VERSION 5.8 ;
BUSBITCHARS "[]" ;
DIVIDERCHAR "/" ;
UNITS
    DATABASE MICRONS 1000 ;
END UNITS

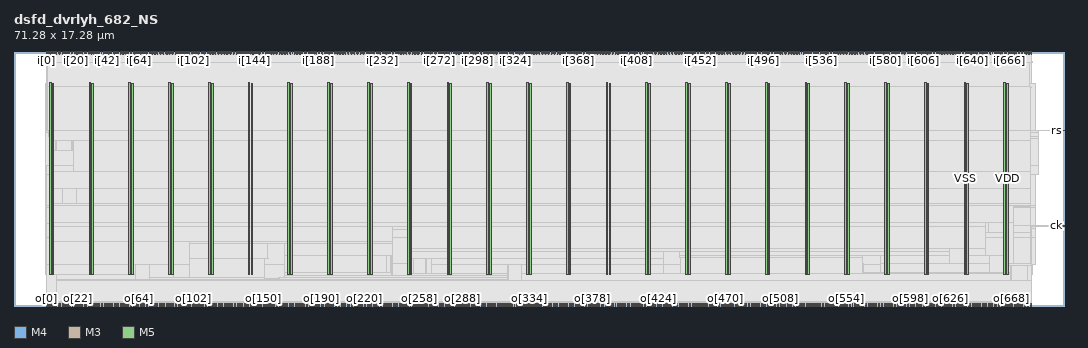
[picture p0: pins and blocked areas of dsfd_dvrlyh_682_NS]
MACRO dsfd_dvrlyh_682_NS
  FOREIGN dsfd_dvrlyh_682_NS 0 0 ;
  CLASS BLOCK ;
  SIZE 71.28 BY 17.28 ;
  PIN ck
    DIRECTION INPUT ;
    USE SIGNAL ;
    PORT
      LAYER M4 ;
        RECT  71.088 5.424 71.28 5.448 ;
    END
  END ck
  PIN ck_o
    DIRECTION OUTPUT ;
    USE SIGNAL ;
    PORT
      LAYER M3 ;
        RECT  69.048 0 69.066 0.144 ;
    END
  END ck_o
  PIN i[0]
    DIRECTION INPUT ;
    USE SIGNAL ;
    PORT
      LAYER M3 ;
        RECT  2.196 17.136 2.214 17.28 ;
    END
  END i[0]
  PIN i[100]
    DIRECTION INPUT ;
    USE SIGNAL ;
    PORT
      LAYER M3 ;
        RECT  12.024 17.136 12.042 17.28 ;
    END
  END i[100]
  PIN i[101]
    DIRECTION INPUT ;
    USE SIGNAL ;
    PORT
      LAYER M5 ;
        RECT  12.096 17.088 12.12 17.28 ;
    END
  END i[101]
  PIN i[102]
    DIRECTION INPUT ;
    USE SIGNAL ;
    PORT
      LAYER M3 ;
        RECT  12.204 17.136 12.222 17.28 ;
    END
  END i[102]
  PIN i[103]
    DIRECTION INPUT ;
    USE SIGNAL ;
    PORT
      LAYER M5 ;
        RECT  12.288 17.088 12.312 17.28 ;
    END
  END i[103]
  PIN i[104]
    DIRECTION INPUT ;
    USE SIGNAL ;
    PORT
      LAYER M3 ;
        RECT  12.42 17.136 12.438 17.28 ;
    END
  END i[104]
  PIN i[105]
    DIRECTION INPUT ;
    USE SIGNAL ;
    PORT
      LAYER M5 ;
        RECT  12.528 17.088 12.552 17.28 ;
    END
  END i[105]
  PIN i[106]
    DIRECTION INPUT ;
    USE SIGNAL ;
    PORT
      LAYER M3 ;
        RECT  12.6 17.136 12.618 17.28 ;
    END
  END i[106]
  PIN i[107]
    DIRECTION INPUT ;
    USE SIGNAL ;
    PORT
      LAYER M5 ;
        RECT  12.72 17.088 12.744 17.28 ;
    END
  END i[107]
  PIN i[108]
    DIRECTION INPUT ;
    USE SIGNAL ;
    PORT
      LAYER M3 ;
        RECT  12.816 17.136 12.834 17.28 ;
    END
  END i[108]
  PIN i[109]
    DIRECTION INPUT ;
    USE SIGNAL ;
    PORT
      LAYER M5 ;
        RECT  12.912 17.088 12.936 17.28 ;
    END
  END i[109]
  PIN i[10]
    DIRECTION INPUT ;
    USE SIGNAL ;
    PORT
      LAYER M3 ;
        RECT  3.168 17.136 3.186 17.28 ;
    END
  END i[10]
  PIN i[110]
    DIRECTION INPUT ;
    USE SIGNAL ;
    PORT
      LAYER M3 ;
        RECT  12.996 17.136 13.014 17.28 ;
    END
  END i[110]
  PIN i[111]
    DIRECTION INPUT ;
    USE SIGNAL ;
    PORT
      LAYER M5 ;
        RECT  13.104 17.088 13.128 17.28 ;
    END
  END i[111]
  PIN i[112]
    DIRECTION INPUT ;
    USE SIGNAL ;
    PORT
      LAYER M3 ;
        RECT  13.212 17.136 13.23 17.28 ;
    END
  END i[112]
  PIN i[113]
    DIRECTION INPUT ;
    USE SIGNAL ;
    PORT
      LAYER M5 ;
        RECT  13.296 17.088 13.32 17.28 ;
    END
  END i[113]
  PIN i[114]
    DIRECTION INPUT ;
    USE SIGNAL ;
    PORT
      LAYER M3 ;
        RECT  13.392 17.136 13.41 17.28 ;
    END
  END i[114]
  PIN i[115]
    DIRECTION INPUT ;
    USE SIGNAL ;
    PORT
      LAYER M5 ;
        RECT  13.488 17.088 13.512 17.28 ;
    END
  END i[115]
  PIN i[116]
    DIRECTION INPUT ;
    USE SIGNAL ;
    PORT
      LAYER M3 ;
        RECT  13.572 17.136 13.59 17.28 ;
    END
  END i[116]
  PIN i[117]
    DIRECTION INPUT ;
    USE SIGNAL ;
    PORT
      LAYER M5 ;
        RECT  13.68 17.088 13.704 17.28 ;
    END
  END i[117]
  PIN i[118]
    DIRECTION INPUT ;
    USE SIGNAL ;
    PORT
      LAYER M3 ;
        RECT  13.788 17.136 13.806 17.28 ;
    END
  END i[118]
  PIN i[119]
    DIRECTION INPUT ;
    USE SIGNAL ;
    PORT
      LAYER M5 ;
        RECT  13.872 17.088 13.896 17.28 ;
    END
  END i[119]
  PIN i[11]
    DIRECTION INPUT ;
    USE SIGNAL ;
    PORT
      LAYER M5 ;
        RECT  3.264 17.088 3.288 17.28 ;
    END
  END i[11]
  PIN i[120]
    DIRECTION INPUT ;
    USE SIGNAL ;
    PORT
      LAYER M3 ;
        RECT  13.968 17.136 13.986 17.28 ;
    END
  END i[120]
  PIN i[121]
    DIRECTION INPUT ;
    USE SIGNAL ;
    PORT
      LAYER M5 ;
        RECT  14.064 17.088 14.088 17.28 ;
    END
  END i[121]
  PIN i[122]
    DIRECTION INPUT ;
    USE SIGNAL ;
    PORT
      LAYER M3 ;
        RECT  14.184 17.136 14.202 17.28 ;
    END
  END i[122]
  PIN i[123]
    DIRECTION INPUT ;
    USE SIGNAL ;
    PORT
      LAYER M5 ;
        RECT  14.256 17.088 14.28 17.28 ;
    END
  END i[123]
  PIN i[124]
    DIRECTION INPUT ;
    USE SIGNAL ;
    PORT
      LAYER M3 ;
        RECT  14.364 17.136 14.382 17.28 ;
    END
  END i[124]
  PIN i[125]
    DIRECTION INPUT ;
    USE SIGNAL ;
    PORT
      LAYER M5 ;
        RECT  14.448 17.088 14.472 17.28 ;
    END
  END i[125]
  PIN i[126]
    DIRECTION INPUT ;
    USE SIGNAL ;
    PORT
      LAYER M3 ;
        RECT  14.58 17.136 14.598 17.28 ;
    END
  END i[126]
  PIN i[127]
    DIRECTION INPUT ;
    USE SIGNAL ;
    PORT
      LAYER M5 ;
        RECT  14.688 17.088 14.712 17.28 ;
    END
  END i[127]
  PIN i[128]
    DIRECTION INPUT ;
    USE SIGNAL ;
    PORT
      LAYER M3 ;
        RECT  14.76 17.136 14.778 17.28 ;
    END
  END i[128]
  PIN i[129]
    DIRECTION INPUT ;
    USE SIGNAL ;
    PORT
      LAYER M5 ;
        RECT  14.88 17.088 14.904 17.28 ;
    END
  END i[129]
  PIN i[12]
    DIRECTION INPUT ;
    USE SIGNAL ;
    PORT
      LAYER M3 ;
        RECT  3.384 17.136 3.402 17.28 ;
    END
  END i[12]
  PIN i[130]
    DIRECTION INPUT ;
    USE SIGNAL ;
    PORT
      LAYER M3 ;
        RECT  14.976 17.136 14.994 17.28 ;
    END
  END i[130]
  PIN i[131]
    DIRECTION INPUT ;
    USE SIGNAL ;
    PORT
      LAYER M5 ;
        RECT  15.072 17.088 15.096 17.28 ;
    END
  END i[131]
  PIN i[132]
    DIRECTION INPUT ;
    USE SIGNAL ;
    PORT
      LAYER M3 ;
        RECT  15.156 17.136 15.174 17.28 ;
    END
  END i[132]
  PIN i[133]
    DIRECTION INPUT ;
    USE SIGNAL ;
    PORT
      LAYER M5 ;
        RECT  15.264 17.088 15.288 17.28 ;
    END
  END i[133]
  PIN i[134]
    DIRECTION INPUT ;
    USE SIGNAL ;
    PORT
      LAYER M3 ;
        RECT  15.372 17.136 15.39 17.28 ;
    END
  END i[134]
  PIN i[135]
    DIRECTION INPUT ;
    USE SIGNAL ;
    PORT
      LAYER M5 ;
        RECT  15.456 17.088 15.48 17.28 ;
    END
  END i[135]
  PIN i[136]
    DIRECTION INPUT ;
    USE SIGNAL ;
    PORT
      LAYER M3 ;
        RECT  15.552 17.136 15.57 17.28 ;
    END
  END i[136]
  PIN i[137]
    DIRECTION INPUT ;
    USE SIGNAL ;
    PORT
      LAYER M5 ;
        RECT  15.648 17.088 15.672 17.28 ;
    END
  END i[137]
  PIN i[138]
    DIRECTION INPUT ;
    USE SIGNAL ;
    PORT
      LAYER M3 ;
        RECT  15.732 17.136 15.75 17.28 ;
    END
  END i[138]
  PIN i[139]
    DIRECTION INPUT ;
    USE SIGNAL ;
    PORT
      LAYER M5 ;
        RECT  15.84 17.088 15.864 17.28 ;
    END
  END i[139]
  PIN i[13]
    DIRECTION INPUT ;
    USE SIGNAL ;
    PORT
      LAYER M5 ;
        RECT  3.456 17.088 3.48 17.28 ;
    END
  END i[13]
  PIN i[140]
    DIRECTION INPUT ;
    USE SIGNAL ;
    PORT
      LAYER M3 ;
        RECT  15.948 17.136 15.966 17.28 ;
    END
  END i[140]
  PIN i[141]
    DIRECTION INPUT ;
    USE SIGNAL ;
    PORT
      LAYER M5 ;
        RECT  16.032 17.088 16.056 17.28 ;
    END
  END i[141]
  PIN i[142]
    DIRECTION INPUT ;
    USE SIGNAL ;
    PORT
      LAYER M3 ;
        RECT  16.128 17.136 16.146 17.28 ;
    END
  END i[142]
  PIN i[143]
    DIRECTION INPUT ;
    USE SIGNAL ;
    PORT
      LAYER M5 ;
        RECT  16.224 17.088 16.248 17.28 ;
    END
  END i[143]
  PIN i[144]
    DIRECTION INPUT ;
    USE SIGNAL ;
    PORT
      LAYER M3 ;
        RECT  16.344 17.136 16.362 17.28 ;
    END
  END i[144]
  PIN i[145]
    DIRECTION INPUT ;
    USE SIGNAL ;
    PORT
      LAYER M5 ;
        RECT  16.416 17.088 16.44 17.28 ;
    END
  END i[145]
  PIN i[146]
    DIRECTION INPUT ;
    USE SIGNAL ;
    PORT
      LAYER M3 ;
        RECT  16.524 17.136 16.542 17.28 ;
    END
  END i[146]
  PIN i[147]
    DIRECTION INPUT ;
    USE SIGNAL ;
    PORT
      LAYER M5 ;
        RECT  16.608 17.088 16.632 17.28 ;
    END
  END i[147]
  PIN i[148]
    DIRECTION INPUT ;
    USE SIGNAL ;
    PORT
      LAYER M3 ;
        RECT  16.74 17.136 16.758 17.28 ;
    END
  END i[148]
  PIN i[149]
    DIRECTION INPUT ;
    USE SIGNAL ;
    PORT
      LAYER M5 ;
        RECT  16.848 17.088 16.872 17.28 ;
    END
  END i[149]
  PIN i[14]
    DIRECTION INPUT ;
    USE SIGNAL ;
    PORT
      LAYER M3 ;
        RECT  3.564 17.136 3.582 17.28 ;
    END
  END i[14]
  PIN i[150]
    DIRECTION INPUT ;
    USE SIGNAL ;
    PORT
      LAYER M3 ;
        RECT  16.92 17.136 16.938 17.28 ;
    END
  END i[150]
  PIN i[151]
    DIRECTION INPUT ;
    USE SIGNAL ;
    PORT
      LAYER M5 ;
        RECT  17.04 17.088 17.064 17.28 ;
    END
  END i[151]
  PIN i[152]
    DIRECTION INPUT ;
    USE SIGNAL ;
    PORT
      LAYER M3 ;
        RECT  17.136 17.136 17.154 17.28 ;
    END
  END i[152]
  PIN i[153]
    DIRECTION INPUT ;
    USE SIGNAL ;
    PORT
      LAYER M5 ;
        RECT  17.232 17.088 17.256 17.28 ;
    END
  END i[153]
  PIN i[154]
    DIRECTION INPUT ;
    USE SIGNAL ;
    PORT
      LAYER M3 ;
        RECT  17.316 17.136 17.334 17.28 ;
    END
  END i[154]
  PIN i[155]
    DIRECTION INPUT ;
    USE SIGNAL ;
    PORT
      LAYER M5 ;
        RECT  17.424 17.088 17.448 17.28 ;
    END
  END i[155]
  PIN i[156]
    DIRECTION INPUT ;
    USE SIGNAL ;
    PORT
      LAYER M3 ;
        RECT  17.532 17.136 17.55 17.28 ;
    END
  END i[156]
  PIN i[157]
    DIRECTION INPUT ;
    USE SIGNAL ;
    PORT
      LAYER M5 ;
        RECT  17.616 17.088 17.64 17.28 ;
    END
  END i[157]
  PIN i[158]
    DIRECTION INPUT ;
    USE SIGNAL ;
    PORT
      LAYER M3 ;
        RECT  17.712 17.136 17.73 17.28 ;
    END
  END i[158]
  PIN i[159]
    DIRECTION INPUT ;
    USE SIGNAL ;
    PORT
      LAYER M5 ;
        RECT  17.808 17.088 17.832 17.28 ;
    END
  END i[159]
  PIN i[15]
    DIRECTION INPUT ;
    USE SIGNAL ;
    PORT
      LAYER M5 ;
        RECT  3.648 17.088 3.672 17.28 ;
    END
  END i[15]
  PIN i[160]
    DIRECTION INPUT ;
    USE SIGNAL ;
    PORT
      LAYER M3 ;
        RECT  17.892 17.136 17.91 17.28 ;
    END
  END i[160]
  PIN i[161]
    DIRECTION INPUT ;
    USE SIGNAL ;
    PORT
      LAYER M5 ;
        RECT  18 17.088 18.024 17.28 ;
    END
  END i[161]
  PIN i[162]
    DIRECTION INPUT ;
    USE SIGNAL ;
    PORT
      LAYER M3 ;
        RECT  18.108 17.136 18.126 17.28 ;
    END
  END i[162]
  PIN i[163]
    DIRECTION INPUT ;
    USE SIGNAL ;
    PORT
      LAYER M5 ;
        RECT  18.192 17.088 18.216 17.28 ;
    END
  END i[163]
  PIN i[164]
    DIRECTION INPUT ;
    USE SIGNAL ;
    PORT
      LAYER M3 ;
        RECT  18.288 17.136 18.306 17.28 ;
    END
  END i[164]
  PIN i[165]
    DIRECTION INPUT ;
    USE SIGNAL ;
    PORT
      LAYER M5 ;
        RECT  18.384 17.088 18.408 17.28 ;
    END
  END i[165]
  PIN i[166]
    DIRECTION INPUT ;
    USE SIGNAL ;
    PORT
      LAYER M3 ;
        RECT  18.504 17.136 18.522 17.28 ;
    END
  END i[166]
  PIN i[167]
    DIRECTION INPUT ;
    USE SIGNAL ;
    PORT
      LAYER M5 ;
        RECT  18.576 17.088 18.6 17.28 ;
    END
  END i[167]
  PIN i[168]
    DIRECTION INPUT ;
    USE SIGNAL ;
    PORT
      LAYER M3 ;
        RECT  18.684 17.136 18.702 17.28 ;
    END
  END i[168]
  PIN i[169]
    DIRECTION INPUT ;
    USE SIGNAL ;
    PORT
      LAYER M5 ;
        RECT  18.768 17.088 18.792 17.28 ;
    END
  END i[169]
  PIN i[16]
    DIRECTION INPUT ;
    USE SIGNAL ;
    PORT
      LAYER M3 ;
        RECT  3.78 17.136 3.798 17.28 ;
    END
  END i[16]
  PIN i[170]
    DIRECTION INPUT ;
    USE SIGNAL ;
    PORT
      LAYER M3 ;
        RECT  18.9 17.136 18.918 17.28 ;
    END
  END i[170]
  PIN i[171]
    DIRECTION INPUT ;
    USE SIGNAL ;
    PORT
      LAYER M5 ;
        RECT  19.008 17.088 19.032 17.28 ;
    END
  END i[171]
  PIN i[172]
    DIRECTION INPUT ;
    USE SIGNAL ;
    PORT
      LAYER M3 ;
        RECT  19.08 17.136 19.098 17.28 ;
    END
  END i[172]
  PIN i[173]
    DIRECTION INPUT ;
    USE SIGNAL ;
    PORT
      LAYER M5 ;
        RECT  19.2 17.088 19.224 17.28 ;
    END
  END i[173]
  PIN i[174]
    DIRECTION INPUT ;
    USE SIGNAL ;
    PORT
      LAYER M3 ;
        RECT  19.296 17.136 19.314 17.28 ;
    END
  END i[174]
  PIN i[175]
    DIRECTION INPUT ;
    USE SIGNAL ;
    PORT
      LAYER M5 ;
        RECT  19.392 17.088 19.416 17.28 ;
    END
  END i[175]
  PIN i[176]
    DIRECTION INPUT ;
    USE SIGNAL ;
    PORT
      LAYER M3 ;
        RECT  19.476 17.136 19.494 17.28 ;
    END
  END i[176]
  PIN i[177]
    DIRECTION INPUT ;
    USE SIGNAL ;
    PORT
      LAYER M5 ;
        RECT  19.584 17.088 19.608 17.28 ;
    END
  END i[177]
  PIN i[178]
    DIRECTION INPUT ;
    USE SIGNAL ;
    PORT
      LAYER M3 ;
        RECT  19.692 17.136 19.71 17.28 ;
    END
  END i[178]
  PIN i[179]
    DIRECTION INPUT ;
    USE SIGNAL ;
    PORT
      LAYER M5 ;
        RECT  19.776 17.088 19.8 17.28 ;
    END
  END i[179]
  PIN i[17]
    DIRECTION INPUT ;
    USE SIGNAL ;
    PORT
      LAYER M5 ;
        RECT  3.888 17.088 3.912 17.28 ;
    END
  END i[17]
  PIN i[180]
    DIRECTION INPUT ;
    USE SIGNAL ;
    PORT
      LAYER M3 ;
        RECT  19.872 17.136 19.89 17.28 ;
    END
  END i[180]
  PIN i[181]
    DIRECTION INPUT ;
    USE SIGNAL ;
    PORT
      LAYER M5 ;
        RECT  19.968 17.088 19.992 17.28 ;
    END
  END i[181]
  PIN i[182]
    DIRECTION INPUT ;
    USE SIGNAL ;
    PORT
      LAYER M3 ;
        RECT  20.052 17.136 20.07 17.28 ;
    END
  END i[182]
  PIN i[183]
    DIRECTION INPUT ;
    USE SIGNAL ;
    PORT
      LAYER M5 ;
        RECT  20.16 17.088 20.184 17.28 ;
    END
  END i[183]
  PIN i[184]
    DIRECTION INPUT ;
    USE SIGNAL ;
    PORT
      LAYER M3 ;
        RECT  20.268 17.136 20.286 17.28 ;
    END
  END i[184]
  PIN i[185]
    DIRECTION INPUT ;
    USE SIGNAL ;
    PORT
      LAYER M5 ;
        RECT  20.352 17.088 20.376 17.28 ;
    END
  END i[185]
  PIN i[186]
    DIRECTION INPUT ;
    USE SIGNAL ;
    PORT
      LAYER M3 ;
        RECT  20.448 17.136 20.466 17.28 ;
    END
  END i[186]
  PIN i[187]
    DIRECTION INPUT ;
    USE SIGNAL ;
    PORT
      LAYER M5 ;
        RECT  20.544 17.088 20.568 17.28 ;
    END
  END i[187]
  PIN i[188]
    DIRECTION INPUT ;
    USE SIGNAL ;
    PORT
      LAYER M3 ;
        RECT  20.664 17.136 20.682 17.28 ;
    END
  END i[188]
  PIN i[189]
    DIRECTION INPUT ;
    USE SIGNAL ;
    PORT
      LAYER M5 ;
        RECT  20.736 17.088 20.76 17.28 ;
    END
  END i[189]
  PIN i[18]
    DIRECTION INPUT ;
    USE SIGNAL ;
    PORT
      LAYER M3 ;
        RECT  3.96 17.136 3.978 17.28 ;
    END
  END i[18]
  PIN i[190]
    DIRECTION INPUT ;
    USE SIGNAL ;
    PORT
      LAYER M3 ;
        RECT  20.844 17.136 20.862 17.28 ;
    END
  END i[190]
  PIN i[191]
    DIRECTION INPUT ;
    USE SIGNAL ;
    PORT
      LAYER M5 ;
        RECT  20.928 17.088 20.952 17.28 ;
    END
  END i[191]
  PIN i[192]
    DIRECTION INPUT ;
    USE SIGNAL ;
    PORT
      LAYER M3 ;
        RECT  21.06 17.136 21.078 17.28 ;
    END
  END i[192]
  PIN i[193]
    DIRECTION INPUT ;
    USE SIGNAL ;
    PORT
      LAYER M5 ;
        RECT  21.168 17.088 21.192 17.28 ;
    END
  END i[193]
  PIN i[194]
    DIRECTION INPUT ;
    USE SIGNAL ;
    PORT
      LAYER M3 ;
        RECT  21.24 17.136 21.258 17.28 ;
    END
  END i[194]
  PIN i[195]
    DIRECTION INPUT ;
    USE SIGNAL ;
    PORT
      LAYER M5 ;
        RECT  21.36 17.088 21.384 17.28 ;
    END
  END i[195]
  PIN i[196]
    DIRECTION INPUT ;
    USE SIGNAL ;
    PORT
      LAYER M3 ;
        RECT  21.456 17.136 21.474 17.28 ;
    END
  END i[196]
  PIN i[197]
    DIRECTION INPUT ;
    USE SIGNAL ;
    PORT
      LAYER M5 ;
        RECT  21.552 17.088 21.576 17.28 ;
    END
  END i[197]
  PIN i[198]
    DIRECTION INPUT ;
    USE SIGNAL ;
    PORT
      LAYER M3 ;
        RECT  21.636 17.136 21.654 17.28 ;
    END
  END i[198]
  PIN i[199]
    DIRECTION INPUT ;
    USE SIGNAL ;
    PORT
      LAYER M5 ;
        RECT  21.744 17.088 21.768 17.28 ;
    END
  END i[199]
  PIN i[19]
    DIRECTION INPUT ;
    USE SIGNAL ;
    PORT
      LAYER M5 ;
        RECT  4.08 17.088 4.104 17.28 ;
    END
  END i[19]
  PIN i[1]
    DIRECTION INPUT ;
    USE SIGNAL ;
    PORT
      LAYER M5 ;
        RECT  2.304 17.088 2.328 17.28 ;
    END
  END i[1]
  PIN i[200]
    DIRECTION INPUT ;
    USE SIGNAL ;
    PORT
      LAYER M3 ;
        RECT  21.852 17.136 21.87 17.28 ;
    END
  END i[200]
  PIN i[201]
    DIRECTION INPUT ;
    USE SIGNAL ;
    PORT
      LAYER M5 ;
        RECT  21.936 17.088 21.96 17.28 ;
    END
  END i[201]
  PIN i[202]
    DIRECTION INPUT ;
    USE SIGNAL ;
    PORT
      LAYER M3 ;
        RECT  22.032 17.136 22.05 17.28 ;
    END
  END i[202]
  PIN i[203]
    DIRECTION INPUT ;
    USE SIGNAL ;
    PORT
      LAYER M5 ;
        RECT  22.128 17.088 22.152 17.28 ;
    END
  END i[203]
  PIN i[204]
    DIRECTION INPUT ;
    USE SIGNAL ;
    PORT
      LAYER M3 ;
        RECT  22.212 17.136 22.23 17.28 ;
    END
  END i[204]
  PIN i[205]
    DIRECTION INPUT ;
    USE SIGNAL ;
    PORT
      LAYER M5 ;
        RECT  22.32 17.088 22.344 17.28 ;
    END
  END i[205]
  PIN i[206]
    DIRECTION INPUT ;
    USE SIGNAL ;
    PORT
      LAYER M3 ;
        RECT  22.428 17.136 22.446 17.28 ;
    END
  END i[206]
  PIN i[207]
    DIRECTION INPUT ;
    USE SIGNAL ;
    PORT
      LAYER M5 ;
        RECT  22.512 17.088 22.536 17.28 ;
    END
  END i[207]
  PIN i[208]
    DIRECTION INPUT ;
    USE SIGNAL ;
    PORT
      LAYER M3 ;
        RECT  22.608 17.136 22.626 17.28 ;
    END
  END i[208]
  PIN i[209]
    DIRECTION INPUT ;
    USE SIGNAL ;
    PORT
      LAYER M5 ;
        RECT  22.704 17.088 22.728 17.28 ;
    END
  END i[209]
  PIN i[20]
    DIRECTION INPUT ;
    USE SIGNAL ;
    PORT
      LAYER M3 ;
        RECT  4.176 17.136 4.194 17.28 ;
    END
  END i[20]
  PIN i[210]
    DIRECTION INPUT ;
    USE SIGNAL ;
    PORT
      LAYER M3 ;
        RECT  22.824 17.136 22.842 17.28 ;
    END
  END i[210]
  PIN i[211]
    DIRECTION INPUT ;
    USE SIGNAL ;
    PORT
      LAYER M5 ;
        RECT  22.896 17.088 22.92 17.28 ;
    END
  END i[211]
  PIN i[212]
    DIRECTION INPUT ;
    USE SIGNAL ;
    PORT
      LAYER M3 ;
        RECT  23.004 17.136 23.022 17.28 ;
    END
  END i[212]
  PIN i[213]
    DIRECTION INPUT ;
    USE SIGNAL ;
    PORT
      LAYER M5 ;
        RECT  23.088 17.088 23.112 17.28 ;
    END
  END i[213]
  PIN i[214]
    DIRECTION INPUT ;
    USE SIGNAL ;
    PORT
      LAYER M3 ;
        RECT  23.22 17.136 23.238 17.28 ;
    END
  END i[214]
  PIN i[215]
    DIRECTION INPUT ;
    USE SIGNAL ;
    PORT
      LAYER M5 ;
        RECT  23.328 17.088 23.352 17.28 ;
    END
  END i[215]
  PIN i[216]
    DIRECTION INPUT ;
    USE SIGNAL ;
    PORT
      LAYER M3 ;
        RECT  23.4 17.136 23.418 17.28 ;
    END
  END i[216]
  PIN i[217]
    DIRECTION INPUT ;
    USE SIGNAL ;
    PORT
      LAYER M5 ;
        RECT  23.52 17.088 23.544 17.28 ;
    END
  END i[217]
  PIN i[218]
    DIRECTION INPUT ;
    USE SIGNAL ;
    PORT
      LAYER M3 ;
        RECT  23.616 17.136 23.634 17.28 ;
    END
  END i[218]
  PIN i[219]
    DIRECTION INPUT ;
    USE SIGNAL ;
    PORT
      LAYER M5 ;
        RECT  23.712 17.088 23.736 17.28 ;
    END
  END i[219]
  PIN i[21]
    DIRECTION INPUT ;
    USE SIGNAL ;
    PORT
      LAYER M5 ;
        RECT  4.272 17.088 4.296 17.28 ;
    END
  END i[21]
  PIN i[220]
    DIRECTION INPUT ;
    USE SIGNAL ;
    PORT
      LAYER M3 ;
        RECT  23.796 17.136 23.814 17.28 ;
    END
  END i[220]
  PIN i[221]
    DIRECTION INPUT ;
    USE SIGNAL ;
    PORT
      LAYER M5 ;
        RECT  23.904 17.088 23.928 17.28 ;
    END
  END i[221]
  PIN i[222]
    DIRECTION INPUT ;
    USE SIGNAL ;
    PORT
      LAYER M3 ;
        RECT  24.012 17.136 24.03 17.28 ;
    END
  END i[222]
  PIN i[223]
    DIRECTION INPUT ;
    USE SIGNAL ;
    PORT
      LAYER M5 ;
        RECT  24.096 17.088 24.12 17.28 ;
    END
  END i[223]
  PIN i[224]
    DIRECTION INPUT ;
    USE SIGNAL ;
    PORT
      LAYER M3 ;
        RECT  24.192 17.136 24.21 17.28 ;
    END
  END i[224]
  PIN i[225]
    DIRECTION INPUT ;
    USE SIGNAL ;
    PORT
      LAYER M5 ;
        RECT  24.288 17.088 24.312 17.28 ;
    END
  END i[225]
  PIN i[226]
    DIRECTION INPUT ;
    USE SIGNAL ;
    PORT
      LAYER M3 ;
        RECT  24.372 17.136 24.39 17.28 ;
    END
  END i[226]
  PIN i[227]
    DIRECTION INPUT ;
    USE SIGNAL ;
    PORT
      LAYER M5 ;
        RECT  24.48 17.088 24.504 17.28 ;
    END
  END i[227]
  PIN i[228]
    DIRECTION INPUT ;
    USE SIGNAL ;
    PORT
      LAYER M3 ;
        RECT  24.588 17.136 24.606 17.28 ;
    END
  END i[228]
  PIN i[229]
    DIRECTION INPUT ;
    USE SIGNAL ;
    PORT
      LAYER M5 ;
        RECT  24.672 17.088 24.696 17.28 ;
    END
  END i[229]
  PIN i[22]
    DIRECTION INPUT ;
    USE SIGNAL ;
    PORT
      LAYER M3 ;
        RECT  4.356 17.136 4.374 17.28 ;
    END
  END i[22]
  PIN i[230]
    DIRECTION INPUT ;
    USE SIGNAL ;
    PORT
      LAYER M3 ;
        RECT  24.768 17.136 24.786 17.28 ;
    END
  END i[230]
  PIN i[231]
    DIRECTION INPUT ;
    USE SIGNAL ;
    PORT
      LAYER M5 ;
        RECT  24.864 17.088 24.888 17.28 ;
    END
  END i[231]
  PIN i[232]
    DIRECTION INPUT ;
    USE SIGNAL ;
    PORT
      LAYER M3 ;
        RECT  24.984 17.136 25.002 17.28 ;
    END
  END i[232]
  PIN i[233]
    DIRECTION INPUT ;
    USE SIGNAL ;
    PORT
      LAYER M5 ;
        RECT  25.056 17.088 25.08 17.28 ;
    END
  END i[233]
  PIN i[234]
    DIRECTION INPUT ;
    USE SIGNAL ;
    PORT
      LAYER M3 ;
        RECT  25.164 17.136 25.182 17.28 ;
    END
  END i[234]
  PIN i[235]
    DIRECTION INPUT ;
    USE SIGNAL ;
    PORT
      LAYER M5 ;
        RECT  25.248 17.088 25.272 17.28 ;
    END
  END i[235]
  PIN i[236]
    DIRECTION INPUT ;
    USE SIGNAL ;
    PORT
      LAYER M3 ;
        RECT  25.38 17.136 25.398 17.28 ;
    END
  END i[236]
  PIN i[237]
    DIRECTION INPUT ;
    USE SIGNAL ;
    PORT
      LAYER M5 ;
        RECT  25.488 17.088 25.512 17.28 ;
    END
  END i[237]
  PIN i[238]
    DIRECTION INPUT ;
    USE SIGNAL ;
    PORT
      LAYER M3 ;
        RECT  25.56 17.136 25.578 17.28 ;
    END
  END i[238]
  PIN i[239]
    DIRECTION INPUT ;
    USE SIGNAL ;
    PORT
      LAYER M5 ;
        RECT  25.68 17.088 25.704 17.28 ;
    END
  END i[239]
  PIN i[23]
    DIRECTION INPUT ;
    USE SIGNAL ;
    PORT
      LAYER M5 ;
        RECT  4.464 17.088 4.488 17.28 ;
    END
  END i[23]
  PIN i[240]
    DIRECTION INPUT ;
    USE SIGNAL ;
    PORT
      LAYER M3 ;
        RECT  25.776 17.136 25.794 17.28 ;
    END
  END i[240]
  PIN i[241]
    DIRECTION INPUT ;
    USE SIGNAL ;
    PORT
      LAYER M5 ;
        RECT  25.872 17.088 25.896 17.28 ;
    END
  END i[241]
  PIN i[242]
    DIRECTION INPUT ;
    USE SIGNAL ;
    PORT
      LAYER M3 ;
        RECT  25.956 17.136 25.974 17.28 ;
    END
  END i[242]
  PIN i[243]
    DIRECTION INPUT ;
    USE SIGNAL ;
    PORT
      LAYER M5 ;
        RECT  26.064 17.088 26.088 17.28 ;
    END
  END i[243]
  PIN i[244]
    DIRECTION INPUT ;
    USE SIGNAL ;
    PORT
      LAYER M3 ;
        RECT  26.172 17.136 26.19 17.28 ;
    END
  END i[244]
  PIN i[245]
    DIRECTION INPUT ;
    USE SIGNAL ;
    PORT
      LAYER M5 ;
        RECT  26.256 17.088 26.28 17.28 ;
    END
  END i[245]
  PIN i[246]
    DIRECTION INPUT ;
    USE SIGNAL ;
    PORT
      LAYER M3 ;
        RECT  26.352 17.136 26.37 17.28 ;
    END
  END i[246]
  PIN i[247]
    DIRECTION INPUT ;
    USE SIGNAL ;
    PORT
      LAYER M5 ;
        RECT  26.448 17.088 26.472 17.28 ;
    END
  END i[247]
  PIN i[248]
    DIRECTION INPUT ;
    USE SIGNAL ;
    PORT
      LAYER M3 ;
        RECT  26.532 17.136 26.55 17.28 ;
    END
  END i[248]
  PIN i[249]
    DIRECTION INPUT ;
    USE SIGNAL ;
    PORT
      LAYER M5 ;
        RECT  26.64 17.088 26.664 17.28 ;
    END
  END i[249]
  PIN i[24]
    DIRECTION INPUT ;
    USE SIGNAL ;
    PORT
      LAYER M3 ;
        RECT  4.572 17.136 4.59 17.28 ;
    END
  END i[24]
  PIN i[250]
    DIRECTION INPUT ;
    USE SIGNAL ;
    PORT
      LAYER M3 ;
        RECT  26.748 17.136 26.766 17.28 ;
    END
  END i[250]
  PIN i[251]
    DIRECTION INPUT ;
    USE SIGNAL ;
    PORT
      LAYER M5 ;
        RECT  26.832 17.088 26.856 17.28 ;
    END
  END i[251]
  PIN i[252]
    DIRECTION INPUT ;
    USE SIGNAL ;
    PORT
      LAYER M3 ;
        RECT  26.928 17.136 26.946 17.28 ;
    END
  END i[252]
  PIN i[253]
    DIRECTION INPUT ;
    USE SIGNAL ;
    PORT
      LAYER M5 ;
        RECT  27.024 17.088 27.048 17.28 ;
    END
  END i[253]
  PIN i[254]
    DIRECTION INPUT ;
    USE SIGNAL ;
    PORT
      LAYER M3 ;
        RECT  27.144 17.136 27.162 17.28 ;
    END
  END i[254]
  PIN i[255]
    DIRECTION INPUT ;
    USE SIGNAL ;
    PORT
      LAYER M5 ;
        RECT  27.216 17.088 27.24 17.28 ;
    END
  END i[255]
  PIN i[256]
    DIRECTION INPUT ;
    USE SIGNAL ;
    PORT
      LAYER M3 ;
        RECT  27.324 17.136 27.342 17.28 ;
    END
  END i[256]
  PIN i[257]
    DIRECTION INPUT ;
    USE SIGNAL ;
    PORT
      LAYER M5 ;
        RECT  27.408 17.088 27.432 17.28 ;
    END
  END i[257]
  PIN i[258]
    DIRECTION INPUT ;
    USE SIGNAL ;
    PORT
      LAYER M3 ;
        RECT  27.54 17.136 27.558 17.28 ;
    END
  END i[258]
  PIN i[259]
    DIRECTION INPUT ;
    USE SIGNAL ;
    PORT
      LAYER M5 ;
        RECT  27.648 17.088 27.672 17.28 ;
    END
  END i[259]
  PIN i[25]
    DIRECTION INPUT ;
    USE SIGNAL ;
    PORT
      LAYER M5 ;
        RECT  4.656 17.088 4.68 17.28 ;
    END
  END i[25]
  PIN i[260]
    DIRECTION INPUT ;
    USE SIGNAL ;
    PORT
      LAYER M3 ;
        RECT  27.72 17.136 27.738 17.28 ;
    END
  END i[260]
  PIN i[261]
    DIRECTION INPUT ;
    USE SIGNAL ;
    PORT
      LAYER M5 ;
        RECT  27.84 17.088 27.864 17.28 ;
    END
  END i[261]
  PIN i[262]
    DIRECTION INPUT ;
    USE SIGNAL ;
    PORT
      LAYER M3 ;
        RECT  27.936 17.136 27.954 17.28 ;
    END
  END i[262]
  PIN i[263]
    DIRECTION INPUT ;
    USE SIGNAL ;
    PORT
      LAYER M5 ;
        RECT  28.032 17.088 28.056 17.28 ;
    END
  END i[263]
  PIN i[264]
    DIRECTION INPUT ;
    USE SIGNAL ;
    PORT
      LAYER M3 ;
        RECT  28.116 17.136 28.134 17.28 ;
    END
  END i[264]
  PIN i[265]
    DIRECTION INPUT ;
    USE SIGNAL ;
    PORT
      LAYER M5 ;
        RECT  28.224 17.088 28.248 17.28 ;
    END
  END i[265]
  PIN i[266]
    DIRECTION INPUT ;
    USE SIGNAL ;
    PORT
      LAYER M3 ;
        RECT  28.332 17.136 28.35 17.28 ;
    END
  END i[266]
  PIN i[267]
    DIRECTION INPUT ;
    USE SIGNAL ;
    PORT
      LAYER M5 ;
        RECT  28.416 17.088 28.44 17.28 ;
    END
  END i[267]
  PIN i[268]
    DIRECTION INPUT ;
    USE SIGNAL ;
    PORT
      LAYER M3 ;
        RECT  28.512 17.136 28.53 17.28 ;
    END
  END i[268]
  PIN i[269]
    DIRECTION INPUT ;
    USE SIGNAL ;
    PORT
      LAYER M5 ;
        RECT  28.608 17.088 28.632 17.28 ;
    END
  END i[269]
  PIN i[26]
    DIRECTION INPUT ;
    USE SIGNAL ;
    PORT
      LAYER M3 ;
        RECT  4.752 17.136 4.77 17.28 ;
    END
  END i[26]
  PIN i[270]
    DIRECTION INPUT ;
    USE SIGNAL ;
    PORT
      LAYER M3 ;
        RECT  28.692 17.136 28.71 17.28 ;
    END
  END i[270]
  PIN i[271]
    DIRECTION INPUT ;
    USE SIGNAL ;
    PORT
      LAYER M5 ;
        RECT  28.8 17.088 28.824 17.28 ;
    END
  END i[271]
  PIN i[272]
    DIRECTION INPUT ;
    USE SIGNAL ;
    PORT
      LAYER M3 ;
        RECT  28.908 17.136 28.926 17.28 ;
    END
  END i[272]
  PIN i[273]
    DIRECTION INPUT ;
    USE SIGNAL ;
    PORT
      LAYER M5 ;
        RECT  28.992 17.088 29.016 17.28 ;
    END
  END i[273]
  PIN i[274]
    DIRECTION INPUT ;
    USE SIGNAL ;
    PORT
      LAYER M3 ;
        RECT  29.088 17.136 29.106 17.28 ;
    END
  END i[274]
  PIN i[275]
    DIRECTION INPUT ;
    USE SIGNAL ;
    PORT
      LAYER M5 ;
        RECT  29.184 17.088 29.208 17.28 ;
    END
  END i[275]
  PIN i[276]
    DIRECTION INPUT ;
    USE SIGNAL ;
    PORT
      LAYER M3 ;
        RECT  29.304 17.136 29.322 17.28 ;
    END
  END i[276]
  PIN i[277]
    DIRECTION INPUT ;
    USE SIGNAL ;
    PORT
      LAYER M5 ;
        RECT  29.376 17.088 29.4 17.28 ;
    END
  END i[277]
  PIN i[278]
    DIRECTION INPUT ;
    USE SIGNAL ;
    PORT
      LAYER M3 ;
        RECT  29.484 17.136 29.502 17.28 ;
    END
  END i[278]
  PIN i[279]
    DIRECTION INPUT ;
    USE SIGNAL ;
    PORT
      LAYER M5 ;
        RECT  29.568 17.088 29.592 17.28 ;
    END
  END i[279]
  PIN i[27]
    DIRECTION INPUT ;
    USE SIGNAL ;
    PORT
      LAYER M5 ;
        RECT  4.848 17.088 4.872 17.28 ;
    END
  END i[27]
  PIN i[280]
    DIRECTION INPUT ;
    USE SIGNAL ;
    PORT
      LAYER M3 ;
        RECT  29.7 17.136 29.718 17.28 ;
    END
  END i[280]
  PIN i[281]
    DIRECTION INPUT ;
    USE SIGNAL ;
    PORT
      LAYER M5 ;
        RECT  29.808 17.088 29.832 17.28 ;
    END
  END i[281]
  PIN i[282]
    DIRECTION INPUT ;
    USE SIGNAL ;
    PORT
      LAYER M3 ;
        RECT  29.88 17.136 29.898 17.28 ;
    END
  END i[282]
  PIN i[283]
    DIRECTION INPUT ;
    USE SIGNAL ;
    PORT
      LAYER M5 ;
        RECT  30 17.088 30.024 17.28 ;
    END
  END i[283]
  PIN i[284]
    DIRECTION INPUT ;
    USE SIGNAL ;
    PORT
      LAYER M3 ;
        RECT  30.096 17.136 30.114 17.28 ;
    END
  END i[284]
  PIN i[285]
    DIRECTION INPUT ;
    USE SIGNAL ;
    PORT
      LAYER M5 ;
        RECT  30.192 17.088 30.216 17.28 ;
    END
  END i[285]
  PIN i[286]
    DIRECTION INPUT ;
    USE SIGNAL ;
    PORT
      LAYER M3 ;
        RECT  30.276 17.136 30.294 17.28 ;
    END
  END i[286]
  PIN i[287]
    DIRECTION INPUT ;
    USE SIGNAL ;
    PORT
      LAYER M5 ;
        RECT  30.384 17.088 30.408 17.28 ;
    END
  END i[287]
  PIN i[288]
    DIRECTION INPUT ;
    USE SIGNAL ;
    PORT
      LAYER M3 ;
        RECT  30.492 17.136 30.51 17.28 ;
    END
  END i[288]
  PIN i[289]
    DIRECTION INPUT ;
    USE SIGNAL ;
    PORT
      LAYER M5 ;
        RECT  30.576 17.088 30.6 17.28 ;
    END
  END i[289]
  PIN i[28]
    DIRECTION INPUT ;
    USE SIGNAL ;
    PORT
      LAYER M3 ;
        RECT  4.932 17.136 4.95 17.28 ;
    END
  END i[28]
  PIN i[290]
    DIRECTION INPUT ;
    USE SIGNAL ;
    PORT
      LAYER M3 ;
        RECT  30.672 17.136 30.69 17.28 ;
    END
  END i[290]
  PIN i[291]
    DIRECTION INPUT ;
    USE SIGNAL ;
    PORT
      LAYER M5 ;
        RECT  30.768 17.088 30.792 17.28 ;
    END
  END i[291]
  PIN i[292]
    DIRECTION INPUT ;
    USE SIGNAL ;
    PORT
      LAYER M3 ;
        RECT  30.852 17.136 30.87 17.28 ;
    END
  END i[292]
  PIN i[293]
    DIRECTION INPUT ;
    USE SIGNAL ;
    PORT
      LAYER M5 ;
        RECT  30.96 17.088 30.984 17.28 ;
    END
  END i[293]
  PIN i[294]
    DIRECTION INPUT ;
    USE SIGNAL ;
    PORT
      LAYER M3 ;
        RECT  31.068 17.136 31.086 17.28 ;
    END
  END i[294]
  PIN i[295]
    DIRECTION INPUT ;
    USE SIGNAL ;
    PORT
      LAYER M5 ;
        RECT  31.152 17.088 31.176 17.28 ;
    END
  END i[295]
  PIN i[296]
    DIRECTION INPUT ;
    USE SIGNAL ;
    PORT
      LAYER M3 ;
        RECT  31.248 17.136 31.266 17.28 ;
    END
  END i[296]
  PIN i[297]
    DIRECTION INPUT ;
    USE SIGNAL ;
    PORT
      LAYER M5 ;
        RECT  31.344 17.088 31.368 17.28 ;
    END
  END i[297]
  PIN i[298]
    DIRECTION INPUT ;
    USE SIGNAL ;
    PORT
      LAYER M3 ;
        RECT  31.464 17.136 31.482 17.28 ;
    END
  END i[298]
  PIN i[299]
    DIRECTION INPUT ;
    USE SIGNAL ;
    PORT
      LAYER M5 ;
        RECT  31.536 17.088 31.56 17.28 ;
    END
  END i[299]
  PIN i[29]
    DIRECTION INPUT ;
    USE SIGNAL ;
    PORT
      LAYER M5 ;
        RECT  5.04 17.088 5.064 17.28 ;
    END
  END i[29]
  PIN i[2]
    DIRECTION INPUT ;
    USE SIGNAL ;
    PORT
      LAYER M3 ;
        RECT  2.412 17.136 2.43 17.28 ;
    END
  END i[2]
  PIN i[300]
    DIRECTION INPUT ;
    USE SIGNAL ;
    PORT
      LAYER M3 ;
        RECT  31.644 17.136 31.662 17.28 ;
    END
  END i[300]
  PIN i[301]
    DIRECTION INPUT ;
    USE SIGNAL ;
    PORT
      LAYER M5 ;
        RECT  31.728 17.088 31.752 17.28 ;
    END
  END i[301]
  PIN i[302]
    DIRECTION INPUT ;
    USE SIGNAL ;
    PORT
      LAYER M3 ;
        RECT  31.86 17.136 31.878 17.28 ;
    END
  END i[302]
  PIN i[303]
    DIRECTION INPUT ;
    USE SIGNAL ;
    PORT
      LAYER M5 ;
        RECT  31.968 17.088 31.992 17.28 ;
    END
  END i[303]
  PIN i[304]
    DIRECTION INPUT ;
    USE SIGNAL ;
    PORT
      LAYER M3 ;
        RECT  32.04 17.136 32.058 17.28 ;
    END
  END i[304]
  PIN i[305]
    DIRECTION INPUT ;
    USE SIGNAL ;
    PORT
      LAYER M5 ;
        RECT  32.16 17.088 32.184 17.28 ;
    END
  END i[305]
  PIN i[306]
    DIRECTION INPUT ;
    USE SIGNAL ;
    PORT
      LAYER M3 ;
        RECT  32.256 17.136 32.274 17.28 ;
    END
  END i[306]
  PIN i[307]
    DIRECTION INPUT ;
    USE SIGNAL ;
    PORT
      LAYER M5 ;
        RECT  32.352 17.088 32.376 17.28 ;
    END
  END i[307]
  PIN i[308]
    DIRECTION INPUT ;
    USE SIGNAL ;
    PORT
      LAYER M3 ;
        RECT  32.436 17.136 32.454 17.28 ;
    END
  END i[308]
  PIN i[309]
    DIRECTION INPUT ;
    USE SIGNAL ;
    PORT
      LAYER M5 ;
        RECT  32.544 17.088 32.568 17.28 ;
    END
  END i[309]
  PIN i[30]
    DIRECTION INPUT ;
    USE SIGNAL ;
    PORT
      LAYER M3 ;
        RECT  5.148 17.136 5.166 17.28 ;
    END
  END i[30]
  PIN i[310]
    DIRECTION INPUT ;
    USE SIGNAL ;
    PORT
      LAYER M3 ;
        RECT  32.652 17.136 32.67 17.28 ;
    END
  END i[310]
  PIN i[311]
    DIRECTION INPUT ;
    USE SIGNAL ;
    PORT
      LAYER M5 ;
        RECT  32.736 17.088 32.76 17.28 ;
    END
  END i[311]
  PIN i[312]
    DIRECTION INPUT ;
    USE SIGNAL ;
    PORT
      LAYER M3 ;
        RECT  32.832 17.136 32.85 17.28 ;
    END
  END i[312]
  PIN i[313]
    DIRECTION INPUT ;
    USE SIGNAL ;
    PORT
      LAYER M5 ;
        RECT  32.928 17.088 32.952 17.28 ;
    END
  END i[313]
  PIN i[314]
    DIRECTION INPUT ;
    USE SIGNAL ;
    PORT
      LAYER M3 ;
        RECT  33.012 17.136 33.03 17.28 ;
    END
  END i[314]
  PIN i[315]
    DIRECTION INPUT ;
    USE SIGNAL ;
    PORT
      LAYER M5 ;
        RECT  33.12 17.088 33.144 17.28 ;
    END
  END i[315]
  PIN i[316]
    DIRECTION INPUT ;
    USE SIGNAL ;
    PORT
      LAYER M3 ;
        RECT  33.228 17.136 33.246 17.28 ;
    END
  END i[316]
  PIN i[317]
    DIRECTION INPUT ;
    USE SIGNAL ;
    PORT
      LAYER M5 ;
        RECT  33.312 17.088 33.336 17.28 ;
    END
  END i[317]
  PIN i[318]
    DIRECTION INPUT ;
    USE SIGNAL ;
    PORT
      LAYER M3 ;
        RECT  33.408 17.136 33.426 17.28 ;
    END
  END i[318]
  PIN i[319]
    DIRECTION INPUT ;
    USE SIGNAL ;
    PORT
      LAYER M5 ;
        RECT  33.504 17.088 33.528 17.28 ;
    END
  END i[319]
  PIN i[31]
    DIRECTION INPUT ;
    USE SIGNAL ;
    PORT
      LAYER M5 ;
        RECT  5.232 17.088 5.256 17.28 ;
    END
  END i[31]
  PIN i[320]
    DIRECTION INPUT ;
    USE SIGNAL ;
    PORT
      LAYER M3 ;
        RECT  33.624 17.136 33.642 17.28 ;
    END
  END i[320]
  PIN i[321]
    DIRECTION INPUT ;
    USE SIGNAL ;
    PORT
      LAYER M5 ;
        RECT  33.696 17.088 33.72 17.28 ;
    END
  END i[321]
  PIN i[322]
    DIRECTION INPUT ;
    USE SIGNAL ;
    PORT
      LAYER M3 ;
        RECT  33.804 17.136 33.822 17.28 ;
    END
  END i[322]
  PIN i[323]
    DIRECTION INPUT ;
    USE SIGNAL ;
    PORT
      LAYER M5 ;
        RECT  33.888 17.088 33.912 17.28 ;
    END
  END i[323]
  PIN i[324]
    DIRECTION INPUT ;
    USE SIGNAL ;
    PORT
      LAYER M3 ;
        RECT  34.02 17.136 34.038 17.28 ;
    END
  END i[324]
  PIN i[325]
    DIRECTION INPUT ;
    USE SIGNAL ;
    PORT
      LAYER M5 ;
        RECT  34.128 17.088 34.152 17.28 ;
    END
  END i[325]
  PIN i[326]
    DIRECTION INPUT ;
    USE SIGNAL ;
    PORT
      LAYER M3 ;
        RECT  34.2 17.136 34.218 17.28 ;
    END
  END i[326]
  PIN i[327]
    DIRECTION INPUT ;
    USE SIGNAL ;
    PORT
      LAYER M5 ;
        RECT  34.32 17.088 34.344 17.28 ;
    END
  END i[327]
  PIN i[328]
    DIRECTION INPUT ;
    USE SIGNAL ;
    PORT
      LAYER M3 ;
        RECT  34.416 17.136 34.434 17.28 ;
    END
  END i[328]
  PIN i[329]
    DIRECTION INPUT ;
    USE SIGNAL ;
    PORT
      LAYER M5 ;
        RECT  34.512 17.088 34.536 17.28 ;
    END
  END i[329]
  PIN i[32]
    DIRECTION INPUT ;
    USE SIGNAL ;
    PORT
      LAYER M3 ;
        RECT  5.328 17.136 5.346 17.28 ;
    END
  END i[32]
  PIN i[330]
    DIRECTION INPUT ;
    USE SIGNAL ;
    PORT
      LAYER M3 ;
        RECT  34.596 17.136 34.614 17.28 ;
    END
  END i[330]
  PIN i[331]
    DIRECTION INPUT ;
    USE SIGNAL ;
    PORT
      LAYER M5 ;
        RECT  34.704 17.088 34.728 17.28 ;
    END
  END i[331]
  PIN i[332]
    DIRECTION INPUT ;
    USE SIGNAL ;
    PORT
      LAYER M3 ;
        RECT  34.812 17.136 34.83 17.28 ;
    END
  END i[332]
  PIN i[333]
    DIRECTION INPUT ;
    USE SIGNAL ;
    PORT
      LAYER M5 ;
        RECT  34.896 17.088 34.92 17.28 ;
    END
  END i[333]
  PIN i[334]
    DIRECTION INPUT ;
    USE SIGNAL ;
    PORT
      LAYER M3 ;
        RECT  34.992 17.136 35.01 17.28 ;
    END
  END i[334]
  PIN i[335]
    DIRECTION INPUT ;
    USE SIGNAL ;
    PORT
      LAYER M5 ;
        RECT  35.088 17.088 35.112 17.28 ;
    END
  END i[335]
  PIN i[336]
    DIRECTION INPUT ;
    USE SIGNAL ;
    PORT
      LAYER M3 ;
        RECT  35.172 17.136 35.19 17.28 ;
    END
  END i[336]
  PIN i[337]
    DIRECTION INPUT ;
    USE SIGNAL ;
    PORT
      LAYER M5 ;
        RECT  35.28 17.088 35.304 17.28 ;
    END
  END i[337]
  PIN i[338]
    DIRECTION INPUT ;
    USE SIGNAL ;
    PORT
      LAYER M3 ;
        RECT  35.388 17.136 35.406 17.28 ;
    END
  END i[338]
  PIN i[339]
    DIRECTION INPUT ;
    USE SIGNAL ;
    PORT
      LAYER M5 ;
        RECT  35.472 17.088 35.496 17.28 ;
    END
  END i[339]
  PIN i[33]
    DIRECTION INPUT ;
    USE SIGNAL ;
    PORT
      LAYER M5 ;
        RECT  5.424 17.088 5.448 17.28 ;
    END
  END i[33]
  PIN i[340]
    DIRECTION INPUT ;
    USE SIGNAL ;
    PORT
      LAYER M3 ;
        RECT  35.568 17.136 35.586 17.28 ;
    END
  END i[340]
  PIN i[341]
    DIRECTION INPUT ;
    USE SIGNAL ;
    PORT
      LAYER M5 ;
        RECT  35.664 17.088 35.688 17.28 ;
    END
  END i[341]
  PIN i[342]
    DIRECTION INPUT ;
    USE SIGNAL ;
    PORT
      LAYER M3 ;
        RECT  35.784 17.136 35.802 17.28 ;
    END
  END i[342]
  PIN i[343]
    DIRECTION INPUT ;
    USE SIGNAL ;
    PORT
      LAYER M5 ;
        RECT  35.856 17.088 35.88 17.28 ;
    END
  END i[343]
  PIN i[344]
    DIRECTION INPUT ;
    USE SIGNAL ;
    PORT
      LAYER M3 ;
        RECT  35.964 17.136 35.982 17.28 ;
    END
  END i[344]
  PIN i[345]
    DIRECTION INPUT ;
    USE SIGNAL ;
    PORT
      LAYER M5 ;
        RECT  36.048 17.088 36.072 17.28 ;
    END
  END i[345]
  PIN i[346]
    DIRECTION INPUT ;
    USE SIGNAL ;
    PORT
      LAYER M3 ;
        RECT  36.18 17.136 36.198 17.28 ;
    END
  END i[346]
  PIN i[347]
    DIRECTION INPUT ;
    USE SIGNAL ;
    PORT
      LAYER M5 ;
        RECT  36.288 17.088 36.312 17.28 ;
    END
  END i[347]
  PIN i[348]
    DIRECTION INPUT ;
    USE SIGNAL ;
    PORT
      LAYER M3 ;
        RECT  36.36 17.136 36.378 17.28 ;
    END
  END i[348]
  PIN i[349]
    DIRECTION INPUT ;
    USE SIGNAL ;
    PORT
      LAYER M5 ;
        RECT  36.48 17.088 36.504 17.28 ;
    END
  END i[349]
  PIN i[34]
    DIRECTION INPUT ;
    USE SIGNAL ;
    PORT
      LAYER M3 ;
        RECT  5.544 17.136 5.562 17.28 ;
    END
  END i[34]
  PIN i[350]
    DIRECTION INPUT ;
    USE SIGNAL ;
    PORT
      LAYER M3 ;
        RECT  36.576 17.136 36.594 17.28 ;
    END
  END i[350]
  PIN i[351]
    DIRECTION INPUT ;
    USE SIGNAL ;
    PORT
      LAYER M5 ;
        RECT  36.672 17.088 36.696 17.28 ;
    END
  END i[351]
  PIN i[352]
    DIRECTION INPUT ;
    USE SIGNAL ;
    PORT
      LAYER M3 ;
        RECT  36.756 17.136 36.774 17.28 ;
    END
  END i[352]
  PIN i[353]
    DIRECTION INPUT ;
    USE SIGNAL ;
    PORT
      LAYER M5 ;
        RECT  36.864 17.088 36.888 17.28 ;
    END
  END i[353]
  PIN i[354]
    DIRECTION INPUT ;
    USE SIGNAL ;
    PORT
      LAYER M3 ;
        RECT  36.972 17.136 36.99 17.28 ;
    END
  END i[354]
  PIN i[355]
    DIRECTION INPUT ;
    USE SIGNAL ;
    PORT
      LAYER M5 ;
        RECT  37.056 17.088 37.08 17.28 ;
    END
  END i[355]
  PIN i[356]
    DIRECTION INPUT ;
    USE SIGNAL ;
    PORT
      LAYER M3 ;
        RECT  37.152 17.136 37.17 17.28 ;
    END
  END i[356]
  PIN i[357]
    DIRECTION INPUT ;
    USE SIGNAL ;
    PORT
      LAYER M5 ;
        RECT  37.248 17.088 37.272 17.28 ;
    END
  END i[357]
  PIN i[358]
    DIRECTION INPUT ;
    USE SIGNAL ;
    PORT
      LAYER M3 ;
        RECT  37.332 17.136 37.35 17.28 ;
    END
  END i[358]
  PIN i[359]
    DIRECTION INPUT ;
    USE SIGNAL ;
    PORT
      LAYER M5 ;
        RECT  37.44 17.088 37.464 17.28 ;
    END
  END i[359]
  PIN i[35]
    DIRECTION INPUT ;
    USE SIGNAL ;
    PORT
      LAYER M5 ;
        RECT  5.616 17.088 5.64 17.28 ;
    END
  END i[35]
  PIN i[360]
    DIRECTION INPUT ;
    USE SIGNAL ;
    PORT
      LAYER M3 ;
        RECT  37.548 17.136 37.566 17.28 ;
    END
  END i[360]
  PIN i[361]
    DIRECTION INPUT ;
    USE SIGNAL ;
    PORT
      LAYER M5 ;
        RECT  37.632 17.088 37.656 17.28 ;
    END
  END i[361]
  PIN i[362]
    DIRECTION INPUT ;
    USE SIGNAL ;
    PORT
      LAYER M3 ;
        RECT  37.728 17.136 37.746 17.28 ;
    END
  END i[362]
  PIN i[363]
    DIRECTION INPUT ;
    USE SIGNAL ;
    PORT
      LAYER M5 ;
        RECT  37.824 17.088 37.848 17.28 ;
    END
  END i[363]
  PIN i[364]
    DIRECTION INPUT ;
    USE SIGNAL ;
    PORT
      LAYER M3 ;
        RECT  37.944 17.136 37.962 17.28 ;
    END
  END i[364]
  PIN i[365]
    DIRECTION INPUT ;
    USE SIGNAL ;
    PORT
      LAYER M5 ;
        RECT  38.016 17.088 38.04 17.28 ;
    END
  END i[365]
  PIN i[366]
    DIRECTION INPUT ;
    USE SIGNAL ;
    PORT
      LAYER M3 ;
        RECT  38.124 17.136 38.142 17.28 ;
    END
  END i[366]
  PIN i[367]
    DIRECTION INPUT ;
    USE SIGNAL ;
    PORT
      LAYER M5 ;
        RECT  38.208 17.088 38.232 17.28 ;
    END
  END i[367]
  PIN i[368]
    DIRECTION INPUT ;
    USE SIGNAL ;
    PORT
      LAYER M3 ;
        RECT  38.34 17.136 38.358 17.28 ;
    END
  END i[368]
  PIN i[369]
    DIRECTION INPUT ;
    USE SIGNAL ;
    PORT
      LAYER M5 ;
        RECT  38.448 17.088 38.472 17.28 ;
    END
  END i[369]
  PIN i[36]
    DIRECTION INPUT ;
    USE SIGNAL ;
    PORT
      LAYER M3 ;
        RECT  5.724 17.136 5.742 17.28 ;
    END
  END i[36]
  PIN i[370]
    DIRECTION INPUT ;
    USE SIGNAL ;
    PORT
      LAYER M3 ;
        RECT  38.52 17.136 38.538 17.28 ;
    END
  END i[370]
  PIN i[371]
    DIRECTION INPUT ;
    USE SIGNAL ;
    PORT
      LAYER M5 ;
        RECT  38.64 17.088 38.664 17.28 ;
    END
  END i[371]
  PIN i[372]
    DIRECTION INPUT ;
    USE SIGNAL ;
    PORT
      LAYER M3 ;
        RECT  38.736 17.136 38.754 17.28 ;
    END
  END i[372]
  PIN i[373]
    DIRECTION INPUT ;
    USE SIGNAL ;
    PORT
      LAYER M5 ;
        RECT  38.832 17.088 38.856 17.28 ;
    END
  END i[373]
  PIN i[374]
    DIRECTION INPUT ;
    USE SIGNAL ;
    PORT
      LAYER M3 ;
        RECT  38.916 17.136 38.934 17.28 ;
    END
  END i[374]
  PIN i[375]
    DIRECTION INPUT ;
    USE SIGNAL ;
    PORT
      LAYER M5 ;
        RECT  39.024 17.088 39.048 17.28 ;
    END
  END i[375]
  PIN i[376]
    DIRECTION INPUT ;
    USE SIGNAL ;
    PORT
      LAYER M3 ;
        RECT  39.132 17.136 39.15 17.28 ;
    END
  END i[376]
  PIN i[377]
    DIRECTION INPUT ;
    USE SIGNAL ;
    PORT
      LAYER M5 ;
        RECT  39.216 17.088 39.24 17.28 ;
    END
  END i[377]
  PIN i[378]
    DIRECTION INPUT ;
    USE SIGNAL ;
    PORT
      LAYER M3 ;
        RECT  39.312 17.136 39.33 17.28 ;
    END
  END i[378]
  PIN i[379]
    DIRECTION INPUT ;
    USE SIGNAL ;
    PORT
      LAYER M5 ;
        RECT  39.408 17.088 39.432 17.28 ;
    END
  END i[379]
  PIN i[37]
    DIRECTION INPUT ;
    USE SIGNAL ;
    PORT
      LAYER M5 ;
        RECT  5.808 17.088 5.832 17.28 ;
    END
  END i[37]
  PIN i[380]
    DIRECTION INPUT ;
    USE SIGNAL ;
    PORT
      LAYER M3 ;
        RECT  39.492 17.136 39.51 17.28 ;
    END
  END i[380]
  PIN i[381]
    DIRECTION INPUT ;
    USE SIGNAL ;
    PORT
      LAYER M5 ;
        RECT  39.6 17.088 39.624 17.28 ;
    END
  END i[381]
  PIN i[382]
    DIRECTION INPUT ;
    USE SIGNAL ;
    PORT
      LAYER M3 ;
        RECT  39.708 17.136 39.726 17.28 ;
    END
  END i[382]
  PIN i[383]
    DIRECTION INPUT ;
    USE SIGNAL ;
    PORT
      LAYER M5 ;
        RECT  39.792 17.088 39.816 17.28 ;
    END
  END i[383]
  PIN i[384]
    DIRECTION INPUT ;
    USE SIGNAL ;
    PORT
      LAYER M3 ;
        RECT  39.888 17.136 39.906 17.28 ;
    END
  END i[384]
  PIN i[385]
    DIRECTION INPUT ;
    USE SIGNAL ;
    PORT
      LAYER M5 ;
        RECT  39.984 17.088 40.008 17.28 ;
    END
  END i[385]
  PIN i[386]
    DIRECTION INPUT ;
    USE SIGNAL ;
    PORT
      LAYER M3 ;
        RECT  40.104 17.136 40.122 17.28 ;
    END
  END i[386]
  PIN i[387]
    DIRECTION INPUT ;
    USE SIGNAL ;
    PORT
      LAYER M5 ;
        RECT  40.176 17.088 40.2 17.28 ;
    END
  END i[387]
  PIN i[388]
    DIRECTION INPUT ;
    USE SIGNAL ;
    PORT
      LAYER M3 ;
        RECT  40.284 17.136 40.302 17.28 ;
    END
  END i[388]
  PIN i[389]
    DIRECTION INPUT ;
    USE SIGNAL ;
    PORT
      LAYER M5 ;
        RECT  40.368 17.088 40.392 17.28 ;
    END
  END i[389]
  PIN i[38]
    DIRECTION INPUT ;
    USE SIGNAL ;
    PORT
      LAYER M3 ;
        RECT  5.94 17.136 5.958 17.28 ;
    END
  END i[38]
  PIN i[390]
    DIRECTION INPUT ;
    USE SIGNAL ;
    PORT
      LAYER M3 ;
        RECT  40.5 17.136 40.518 17.28 ;
    END
  END i[390]
  PIN i[391]
    DIRECTION INPUT ;
    USE SIGNAL ;
    PORT
      LAYER M5 ;
        RECT  40.608 17.088 40.632 17.28 ;
    END
  END i[391]
  PIN i[392]
    DIRECTION INPUT ;
    USE SIGNAL ;
    PORT
      LAYER M3 ;
        RECT  40.68 17.136 40.698 17.28 ;
    END
  END i[392]
  PIN i[393]
    DIRECTION INPUT ;
    USE SIGNAL ;
    PORT
      LAYER M5 ;
        RECT  40.8 17.088 40.824 17.28 ;
    END
  END i[393]
  PIN i[394]
    DIRECTION INPUT ;
    USE SIGNAL ;
    PORT
      LAYER M3 ;
        RECT  40.896 17.136 40.914 17.28 ;
    END
  END i[394]
  PIN i[395]
    DIRECTION INPUT ;
    USE SIGNAL ;
    PORT
      LAYER M5 ;
        RECT  40.992 17.088 41.016 17.28 ;
    END
  END i[395]
  PIN i[396]
    DIRECTION INPUT ;
    USE SIGNAL ;
    PORT
      LAYER M3 ;
        RECT  41.076 17.136 41.094 17.28 ;
    END
  END i[396]
  PIN i[397]
    DIRECTION INPUT ;
    USE SIGNAL ;
    PORT
      LAYER M5 ;
        RECT  41.184 17.088 41.208 17.28 ;
    END
  END i[397]
  PIN i[398]
    DIRECTION INPUT ;
    USE SIGNAL ;
    PORT
      LAYER M3 ;
        RECT  41.292 17.136 41.31 17.28 ;
    END
  END i[398]
  PIN i[399]
    DIRECTION INPUT ;
    USE SIGNAL ;
    PORT
      LAYER M5 ;
        RECT  41.376 17.088 41.4 17.28 ;
    END
  END i[399]
  PIN i[39]
    DIRECTION INPUT ;
    USE SIGNAL ;
    PORT
      LAYER M5 ;
        RECT  6.048 17.088 6.072 17.28 ;
    END
  END i[39]
  PIN i[3]
    DIRECTION INPUT ;
    USE SIGNAL ;
    PORT
      LAYER M5 ;
        RECT  2.496 17.088 2.52 17.28 ;
    END
  END i[3]
  PIN i[400]
    DIRECTION INPUT ;
    USE SIGNAL ;
    PORT
      LAYER M3 ;
        RECT  41.472 17.136 41.49 17.28 ;
    END
  END i[400]
  PIN i[401]
    DIRECTION INPUT ;
    USE SIGNAL ;
    PORT
      LAYER M5 ;
        RECT  41.568 17.088 41.592 17.28 ;
    END
  END i[401]
  PIN i[402]
    DIRECTION INPUT ;
    USE SIGNAL ;
    PORT
      LAYER M3 ;
        RECT  41.652 17.136 41.67 17.28 ;
    END
  END i[402]
  PIN i[403]
    DIRECTION INPUT ;
    USE SIGNAL ;
    PORT
      LAYER M5 ;
        RECT  41.76 17.088 41.784 17.28 ;
    END
  END i[403]
  PIN i[404]
    DIRECTION INPUT ;
    USE SIGNAL ;
    PORT
      LAYER M3 ;
        RECT  41.868 17.136 41.886 17.28 ;
    END
  END i[404]
  PIN i[405]
    DIRECTION INPUT ;
    USE SIGNAL ;
    PORT
      LAYER M5 ;
        RECT  41.952 17.088 41.976 17.28 ;
    END
  END i[405]
  PIN i[406]
    DIRECTION INPUT ;
    USE SIGNAL ;
    PORT
      LAYER M3 ;
        RECT  42.048 17.136 42.066 17.28 ;
    END
  END i[406]
  PIN i[407]
    DIRECTION INPUT ;
    USE SIGNAL ;
    PORT
      LAYER M5 ;
        RECT  42.144 17.088 42.168 17.28 ;
    END
  END i[407]
  PIN i[408]
    DIRECTION INPUT ;
    USE SIGNAL ;
    PORT
      LAYER M3 ;
        RECT  42.264 17.136 42.282 17.28 ;
    END
  END i[408]
  PIN i[409]
    DIRECTION INPUT ;
    USE SIGNAL ;
    PORT
      LAYER M5 ;
        RECT  42.336 17.088 42.36 17.28 ;
    END
  END i[409]
  PIN i[40]
    DIRECTION INPUT ;
    USE SIGNAL ;
    PORT
      LAYER M3 ;
        RECT  6.12 17.136 6.138 17.28 ;
    END
  END i[40]
  PIN i[410]
    DIRECTION INPUT ;
    USE SIGNAL ;
    PORT
      LAYER M3 ;
        RECT  42.444 17.136 42.462 17.28 ;
    END
  END i[410]
  PIN i[411]
    DIRECTION INPUT ;
    USE SIGNAL ;
    PORT
      LAYER M5 ;
        RECT  42.528 17.088 42.552 17.28 ;
    END
  END i[411]
  PIN i[412]
    DIRECTION INPUT ;
    USE SIGNAL ;
    PORT
      LAYER M3 ;
        RECT  42.66 17.136 42.678 17.28 ;
    END
  END i[412]
  PIN i[413]
    DIRECTION INPUT ;
    USE SIGNAL ;
    PORT
      LAYER M5 ;
        RECT  42.768 17.088 42.792 17.28 ;
    END
  END i[413]
  PIN i[414]
    DIRECTION INPUT ;
    USE SIGNAL ;
    PORT
      LAYER M3 ;
        RECT  42.84 17.136 42.858 17.28 ;
    END
  END i[414]
  PIN i[415]
    DIRECTION INPUT ;
    USE SIGNAL ;
    PORT
      LAYER M5 ;
        RECT  42.96 17.088 42.984 17.28 ;
    END
  END i[415]
  PIN i[416]
    DIRECTION INPUT ;
    USE SIGNAL ;
    PORT
      LAYER M3 ;
        RECT  43.056 17.136 43.074 17.28 ;
    END
  END i[416]
  PIN i[417]
    DIRECTION INPUT ;
    USE SIGNAL ;
    PORT
      LAYER M5 ;
        RECT  43.152 17.088 43.176 17.28 ;
    END
  END i[417]
  PIN i[418]
    DIRECTION INPUT ;
    USE SIGNAL ;
    PORT
      LAYER M3 ;
        RECT  43.236 17.136 43.254 17.28 ;
    END
  END i[418]
  PIN i[419]
    DIRECTION INPUT ;
    USE SIGNAL ;
    PORT
      LAYER M5 ;
        RECT  43.344 17.088 43.368 17.28 ;
    END
  END i[419]
  PIN i[41]
    DIRECTION INPUT ;
    USE SIGNAL ;
    PORT
      LAYER M5 ;
        RECT  6.24 17.088 6.264 17.28 ;
    END
  END i[41]
  PIN i[420]
    DIRECTION INPUT ;
    USE SIGNAL ;
    PORT
      LAYER M3 ;
        RECT  43.452 17.136 43.47 17.28 ;
    END
  END i[420]
  PIN i[421]
    DIRECTION INPUT ;
    USE SIGNAL ;
    PORT
      LAYER M5 ;
        RECT  43.536 17.088 43.56 17.28 ;
    END
  END i[421]
  PIN i[422]
    DIRECTION INPUT ;
    USE SIGNAL ;
    PORT
      LAYER M3 ;
        RECT  43.632 17.136 43.65 17.28 ;
    END
  END i[422]
  PIN i[423]
    DIRECTION INPUT ;
    USE SIGNAL ;
    PORT
      LAYER M5 ;
        RECT  43.728 17.088 43.752 17.28 ;
    END
  END i[423]
  PIN i[424]
    DIRECTION INPUT ;
    USE SIGNAL ;
    PORT
      LAYER M3 ;
        RECT  43.812 17.136 43.83 17.28 ;
    END
  END i[424]
  PIN i[425]
    DIRECTION INPUT ;
    USE SIGNAL ;
    PORT
      LAYER M5 ;
        RECT  43.92 17.088 43.944 17.28 ;
    END
  END i[425]
  PIN i[426]
    DIRECTION INPUT ;
    USE SIGNAL ;
    PORT
      LAYER M3 ;
        RECT  44.028 17.136 44.046 17.28 ;
    END
  END i[426]
  PIN i[427]
    DIRECTION INPUT ;
    USE SIGNAL ;
    PORT
      LAYER M5 ;
        RECT  44.112 17.088 44.136 17.28 ;
    END
  END i[427]
  PIN i[428]
    DIRECTION INPUT ;
    USE SIGNAL ;
    PORT
      LAYER M3 ;
        RECT  44.208 17.136 44.226 17.28 ;
    END
  END i[428]
  PIN i[429]
    DIRECTION INPUT ;
    USE SIGNAL ;
    PORT
      LAYER M5 ;
        RECT  44.304 17.088 44.328 17.28 ;
    END
  END i[429]
  PIN i[42]
    DIRECTION INPUT ;
    USE SIGNAL ;
    PORT
      LAYER M3 ;
        RECT  6.336 17.136 6.354 17.28 ;
    END
  END i[42]
  PIN i[430]
    DIRECTION INPUT ;
    USE SIGNAL ;
    PORT
      LAYER M3 ;
        RECT  44.424 17.136 44.442 17.28 ;
    END
  END i[430]
  PIN i[431]
    DIRECTION INPUT ;
    USE SIGNAL ;
    PORT
      LAYER M5 ;
        RECT  44.496 17.088 44.52 17.28 ;
    END
  END i[431]
  PIN i[432]
    DIRECTION INPUT ;
    USE SIGNAL ;
    PORT
      LAYER M3 ;
        RECT  44.604 17.136 44.622 17.28 ;
    END
  END i[432]
  PIN i[433]
    DIRECTION INPUT ;
    USE SIGNAL ;
    PORT
      LAYER M5 ;
        RECT  44.688 17.088 44.712 17.28 ;
    END
  END i[433]
  PIN i[434]
    DIRECTION INPUT ;
    USE SIGNAL ;
    PORT
      LAYER M3 ;
        RECT  44.82 17.136 44.838 17.28 ;
    END
  END i[434]
  PIN i[435]
    DIRECTION INPUT ;
    USE SIGNAL ;
    PORT
      LAYER M5 ;
        RECT  44.928 17.088 44.952 17.28 ;
    END
  END i[435]
  PIN i[436]
    DIRECTION INPUT ;
    USE SIGNAL ;
    PORT
      LAYER M3 ;
        RECT  45 17.136 45.018 17.28 ;
    END
  END i[436]
  PIN i[437]
    DIRECTION INPUT ;
    USE SIGNAL ;
    PORT
      LAYER M5 ;
        RECT  45.12 17.088 45.144 17.28 ;
    END
  END i[437]
  PIN i[438]
    DIRECTION INPUT ;
    USE SIGNAL ;
    PORT
      LAYER M3 ;
        RECT  45.216 17.136 45.234 17.28 ;
    END
  END i[438]
  PIN i[439]
    DIRECTION INPUT ;
    USE SIGNAL ;
    PORT
      LAYER M5 ;
        RECT  45.312 17.088 45.336 17.28 ;
    END
  END i[439]
  PIN i[43]
    DIRECTION INPUT ;
    USE SIGNAL ;
    PORT
      LAYER M5 ;
        RECT  6.432 17.088 6.456 17.28 ;
    END
  END i[43]
  PIN i[440]
    DIRECTION INPUT ;
    USE SIGNAL ;
    PORT
      LAYER M3 ;
        RECT  45.396 17.136 45.414 17.28 ;
    END
  END i[440]
  PIN i[441]
    DIRECTION INPUT ;
    USE SIGNAL ;
    PORT
      LAYER M5 ;
        RECT  45.504 17.088 45.528 17.28 ;
    END
  END i[441]
  PIN i[442]
    DIRECTION INPUT ;
    USE SIGNAL ;
    PORT
      LAYER M3 ;
        RECT  45.612 17.136 45.63 17.28 ;
    END
  END i[442]
  PIN i[443]
    DIRECTION INPUT ;
    USE SIGNAL ;
    PORT
      LAYER M5 ;
        RECT  45.696 17.088 45.72 17.28 ;
    END
  END i[443]
  PIN i[444]
    DIRECTION INPUT ;
    USE SIGNAL ;
    PORT
      LAYER M3 ;
        RECT  45.792 17.136 45.81 17.28 ;
    END
  END i[444]
  PIN i[445]
    DIRECTION INPUT ;
    USE SIGNAL ;
    PORT
      LAYER M5 ;
        RECT  45.888 17.088 45.912 17.28 ;
    END
  END i[445]
  PIN i[446]
    DIRECTION INPUT ;
    USE SIGNAL ;
    PORT
      LAYER M3 ;
        RECT  45.972 17.136 45.99 17.28 ;
    END
  END i[446]
  PIN i[447]
    DIRECTION INPUT ;
    USE SIGNAL ;
    PORT
      LAYER M5 ;
        RECT  46.08 17.088 46.104 17.28 ;
    END
  END i[447]
  PIN i[448]
    DIRECTION INPUT ;
    USE SIGNAL ;
    PORT
      LAYER M3 ;
        RECT  46.188 17.136 46.206 17.28 ;
    END
  END i[448]
  PIN i[449]
    DIRECTION INPUT ;
    USE SIGNAL ;
    PORT
      LAYER M5 ;
        RECT  46.272 17.088 46.296 17.28 ;
    END
  END i[449]
  PIN i[44]
    DIRECTION INPUT ;
    USE SIGNAL ;
    PORT
      LAYER M3 ;
        RECT  6.516 17.136 6.534 17.28 ;
    END
  END i[44]
  PIN i[450]
    DIRECTION INPUT ;
    USE SIGNAL ;
    PORT
      LAYER M3 ;
        RECT  46.368 17.136 46.386 17.28 ;
    END
  END i[450]
  PIN i[451]
    DIRECTION INPUT ;
    USE SIGNAL ;
    PORT
      LAYER M5 ;
        RECT  46.464 17.088 46.488 17.28 ;
    END
  END i[451]
  PIN i[452]
    DIRECTION INPUT ;
    USE SIGNAL ;
    PORT
      LAYER M3 ;
        RECT  46.584 17.136 46.602 17.28 ;
    END
  END i[452]
  PIN i[453]
    DIRECTION INPUT ;
    USE SIGNAL ;
    PORT
      LAYER M5 ;
        RECT  46.656 17.088 46.68 17.28 ;
    END
  END i[453]
  PIN i[454]
    DIRECTION INPUT ;
    USE SIGNAL ;
    PORT
      LAYER M3 ;
        RECT  46.764 17.136 46.782 17.28 ;
    END
  END i[454]
  PIN i[455]
    DIRECTION INPUT ;
    USE SIGNAL ;
    PORT
      LAYER M5 ;
        RECT  46.848 17.088 46.872 17.28 ;
    END
  END i[455]
  PIN i[456]
    DIRECTION INPUT ;
    USE SIGNAL ;
    PORT
      LAYER M3 ;
        RECT  46.98 17.136 46.998 17.28 ;
    END
  END i[456]
  PIN i[457]
    DIRECTION INPUT ;
    USE SIGNAL ;
    PORT
      LAYER M5 ;
        RECT  47.088 17.088 47.112 17.28 ;
    END
  END i[457]
  PIN i[458]
    DIRECTION INPUT ;
    USE SIGNAL ;
    PORT
      LAYER M3 ;
        RECT  47.16 17.136 47.178 17.28 ;
    END
  END i[458]
  PIN i[459]
    DIRECTION INPUT ;
    USE SIGNAL ;
    PORT
      LAYER M5 ;
        RECT  47.28 17.088 47.304 17.28 ;
    END
  END i[459]
  PIN i[45]
    DIRECTION INPUT ;
    USE SIGNAL ;
    PORT
      LAYER M5 ;
        RECT  6.624 17.088 6.648 17.28 ;
    END
  END i[45]
  PIN i[460]
    DIRECTION INPUT ;
    USE SIGNAL ;
    PORT
      LAYER M3 ;
        RECT  47.376 17.136 47.394 17.28 ;
    END
  END i[460]
  PIN i[461]
    DIRECTION INPUT ;
    USE SIGNAL ;
    PORT
      LAYER M5 ;
        RECT  47.472 17.088 47.496 17.28 ;
    END
  END i[461]
  PIN i[462]
    DIRECTION INPUT ;
    USE SIGNAL ;
    PORT
      LAYER M3 ;
        RECT  47.556 17.136 47.574 17.28 ;
    END
  END i[462]
  PIN i[463]
    DIRECTION INPUT ;
    USE SIGNAL ;
    PORT
      LAYER M5 ;
        RECT  47.664 17.088 47.688 17.28 ;
    END
  END i[463]
  PIN i[464]
    DIRECTION INPUT ;
    USE SIGNAL ;
    PORT
      LAYER M3 ;
        RECT  47.772 17.136 47.79 17.28 ;
    END
  END i[464]
  PIN i[465]
    DIRECTION INPUT ;
    USE SIGNAL ;
    PORT
      LAYER M5 ;
        RECT  47.856 17.088 47.88 17.28 ;
    END
  END i[465]
  PIN i[466]
    DIRECTION INPUT ;
    USE SIGNAL ;
    PORT
      LAYER M3 ;
        RECT  47.952 17.136 47.97 17.28 ;
    END
  END i[466]
  PIN i[467]
    DIRECTION INPUT ;
    USE SIGNAL ;
    PORT
      LAYER M5 ;
        RECT  48.048 17.088 48.072 17.28 ;
    END
  END i[467]
  PIN i[468]
    DIRECTION INPUT ;
    USE SIGNAL ;
    PORT
      LAYER M3 ;
        RECT  48.132 17.136 48.15 17.28 ;
    END
  END i[468]
  PIN i[469]
    DIRECTION INPUT ;
    USE SIGNAL ;
    PORT
      LAYER M5 ;
        RECT  48.24 17.088 48.264 17.28 ;
    END
  END i[469]
  PIN i[46]
    DIRECTION INPUT ;
    USE SIGNAL ;
    PORT
      LAYER M3 ;
        RECT  6.732 17.136 6.75 17.28 ;
    END
  END i[46]
  PIN i[470]
    DIRECTION INPUT ;
    USE SIGNAL ;
    PORT
      LAYER M3 ;
        RECT  48.348 17.136 48.366 17.28 ;
    END
  END i[470]
  PIN i[471]
    DIRECTION INPUT ;
    USE SIGNAL ;
    PORT
      LAYER M5 ;
        RECT  48.432 17.088 48.456 17.28 ;
    END
  END i[471]
  PIN i[472]
    DIRECTION INPUT ;
    USE SIGNAL ;
    PORT
      LAYER M3 ;
        RECT  48.528 17.136 48.546 17.28 ;
    END
  END i[472]
  PIN i[473]
    DIRECTION INPUT ;
    USE SIGNAL ;
    PORT
      LAYER M5 ;
        RECT  48.624 17.088 48.648 17.28 ;
    END
  END i[473]
  PIN i[474]
    DIRECTION INPUT ;
    USE SIGNAL ;
    PORT
      LAYER M3 ;
        RECT  48.744 17.136 48.762 17.28 ;
    END
  END i[474]
  PIN i[475]
    DIRECTION INPUT ;
    USE SIGNAL ;
    PORT
      LAYER M5 ;
        RECT  48.816 17.088 48.84 17.28 ;
    END
  END i[475]
  PIN i[476]
    DIRECTION INPUT ;
    USE SIGNAL ;
    PORT
      LAYER M3 ;
        RECT  48.924 17.136 48.942 17.28 ;
    END
  END i[476]
  PIN i[477]
    DIRECTION INPUT ;
    USE SIGNAL ;
    PORT
      LAYER M5 ;
        RECT  49.008 17.088 49.032 17.28 ;
    END
  END i[477]
  PIN i[478]
    DIRECTION INPUT ;
    USE SIGNAL ;
    PORT
      LAYER M3 ;
        RECT  49.14 17.136 49.158 17.28 ;
    END
  END i[478]
  PIN i[479]
    DIRECTION INPUT ;
    USE SIGNAL ;
    PORT
      LAYER M5 ;
        RECT  49.248 17.088 49.272 17.28 ;
    END
  END i[479]
  PIN i[47]
    DIRECTION INPUT ;
    USE SIGNAL ;
    PORT
      LAYER M5 ;
        RECT  6.816 17.088 6.84 17.28 ;
    END
  END i[47]
  PIN i[480]
    DIRECTION INPUT ;
    USE SIGNAL ;
    PORT
      LAYER M3 ;
        RECT  49.32 17.136 49.338 17.28 ;
    END
  END i[480]
  PIN i[481]
    DIRECTION INPUT ;
    USE SIGNAL ;
    PORT
      LAYER M5 ;
        RECT  49.44 17.088 49.464 17.28 ;
    END
  END i[481]
  PIN i[482]
    DIRECTION INPUT ;
    USE SIGNAL ;
    PORT
      LAYER M3 ;
        RECT  49.536 17.136 49.554 17.28 ;
    END
  END i[482]
  PIN i[483]
    DIRECTION INPUT ;
    USE SIGNAL ;
    PORT
      LAYER M5 ;
        RECT  49.632 17.088 49.656 17.28 ;
    END
  END i[483]
  PIN i[484]
    DIRECTION INPUT ;
    USE SIGNAL ;
    PORT
      LAYER M3 ;
        RECT  49.716 17.136 49.734 17.28 ;
    END
  END i[484]
  PIN i[485]
    DIRECTION INPUT ;
    USE SIGNAL ;
    PORT
      LAYER M5 ;
        RECT  49.824 17.088 49.848 17.28 ;
    END
  END i[485]
  PIN i[486]
    DIRECTION INPUT ;
    USE SIGNAL ;
    PORT
      LAYER M3 ;
        RECT  49.932 17.136 49.95 17.28 ;
    END
  END i[486]
  PIN i[487]
    DIRECTION INPUT ;
    USE SIGNAL ;
    PORT
      LAYER M5 ;
        RECT  50.016 17.088 50.04 17.28 ;
    END
  END i[487]
  PIN i[488]
    DIRECTION INPUT ;
    USE SIGNAL ;
    PORT
      LAYER M3 ;
        RECT  50.112 17.136 50.13 17.28 ;
    END
  END i[488]
  PIN i[489]
    DIRECTION INPUT ;
    USE SIGNAL ;
    PORT
      LAYER M5 ;
        RECT  50.208 17.088 50.232 17.28 ;
    END
  END i[489]
  PIN i[48]
    DIRECTION INPUT ;
    USE SIGNAL ;
    PORT
      LAYER M3 ;
        RECT  6.912 17.136 6.93 17.28 ;
    END
  END i[48]
  PIN i[490]
    DIRECTION INPUT ;
    USE SIGNAL ;
    PORT
      LAYER M3 ;
        RECT  50.292 17.136 50.31 17.28 ;
    END
  END i[490]
  PIN i[491]
    DIRECTION INPUT ;
    USE SIGNAL ;
    PORT
      LAYER M5 ;
        RECT  50.4 17.088 50.424 17.28 ;
    END
  END i[491]
  PIN i[492]
    DIRECTION INPUT ;
    USE SIGNAL ;
    PORT
      LAYER M3 ;
        RECT  50.508 17.136 50.526 17.28 ;
    END
  END i[492]
  PIN i[493]
    DIRECTION INPUT ;
    USE SIGNAL ;
    PORT
      LAYER M5 ;
        RECT  50.592 17.088 50.616 17.28 ;
    END
  END i[493]
  PIN i[494]
    DIRECTION INPUT ;
    USE SIGNAL ;
    PORT
      LAYER M3 ;
        RECT  50.688 17.136 50.706 17.28 ;
    END
  END i[494]
  PIN i[495]
    DIRECTION INPUT ;
    USE SIGNAL ;
    PORT
      LAYER M5 ;
        RECT  50.784 17.088 50.808 17.28 ;
    END
  END i[495]
  PIN i[496]
    DIRECTION INPUT ;
    USE SIGNAL ;
    PORT
      LAYER M3 ;
        RECT  50.904 17.136 50.922 17.28 ;
    END
  END i[496]
  PIN i[497]
    DIRECTION INPUT ;
    USE SIGNAL ;
    PORT
      LAYER M5 ;
        RECT  50.976 17.088 51 17.28 ;
    END
  END i[497]
  PIN i[498]
    DIRECTION INPUT ;
    USE SIGNAL ;
    PORT
      LAYER M3 ;
        RECT  51.084 17.136 51.102 17.28 ;
    END
  END i[498]
  PIN i[499]
    DIRECTION INPUT ;
    USE SIGNAL ;
    PORT
      LAYER M5 ;
        RECT  51.168 17.088 51.192 17.28 ;
    END
  END i[499]
  PIN i[49]
    DIRECTION INPUT ;
    USE SIGNAL ;
    PORT
      LAYER M5 ;
        RECT  7.008 17.088 7.032 17.28 ;
    END
  END i[49]
  PIN i[4]
    DIRECTION INPUT ;
    USE SIGNAL ;
    PORT
      LAYER M3 ;
        RECT  2.592 17.136 2.61 17.28 ;
    END
  END i[4]
  PIN i[500]
    DIRECTION INPUT ;
    USE SIGNAL ;
    PORT
      LAYER M3 ;
        RECT  51.3 17.136 51.318 17.28 ;
    END
  END i[500]
  PIN i[501]
    DIRECTION INPUT ;
    USE SIGNAL ;
    PORT
      LAYER M5 ;
        RECT  51.408 17.088 51.432 17.28 ;
    END
  END i[501]
  PIN i[502]
    DIRECTION INPUT ;
    USE SIGNAL ;
    PORT
      LAYER M3 ;
        RECT  51.48 17.136 51.498 17.28 ;
    END
  END i[502]
  PIN i[503]
    DIRECTION INPUT ;
    USE SIGNAL ;
    PORT
      LAYER M5 ;
        RECT  51.6 17.088 51.624 17.28 ;
    END
  END i[503]
  PIN i[504]
    DIRECTION INPUT ;
    USE SIGNAL ;
    PORT
      LAYER M3 ;
        RECT  51.696 17.136 51.714 17.28 ;
    END
  END i[504]
  PIN i[505]
    DIRECTION INPUT ;
    USE SIGNAL ;
    PORT
      LAYER M5 ;
        RECT  51.792 17.088 51.816 17.28 ;
    END
  END i[505]
  PIN i[506]
    DIRECTION INPUT ;
    USE SIGNAL ;
    PORT
      LAYER M3 ;
        RECT  51.876 17.136 51.894 17.28 ;
    END
  END i[506]
  PIN i[507]
    DIRECTION INPUT ;
    USE SIGNAL ;
    PORT
      LAYER M5 ;
        RECT  51.984 17.088 52.008 17.28 ;
    END
  END i[507]
  PIN i[508]
    DIRECTION INPUT ;
    USE SIGNAL ;
    PORT
      LAYER M3 ;
        RECT  52.092 17.136 52.11 17.28 ;
    END
  END i[508]
  PIN i[509]
    DIRECTION INPUT ;
    USE SIGNAL ;
    PORT
      LAYER M5 ;
        RECT  52.176 17.088 52.2 17.28 ;
    END
  END i[509]
  PIN i[50]
    DIRECTION INPUT ;
    USE SIGNAL ;
    PORT
      LAYER M3 ;
        RECT  7.092 17.136 7.11 17.28 ;
    END
  END i[50]
  PIN i[510]
    DIRECTION INPUT ;
    USE SIGNAL ;
    PORT
      LAYER M3 ;
        RECT  52.272 17.136 52.29 17.28 ;
    END
  END i[510]
  PIN i[511]
    DIRECTION INPUT ;
    USE SIGNAL ;
    PORT
      LAYER M5 ;
        RECT  52.368 17.088 52.392 17.28 ;
    END
  END i[511]
  PIN i[512]
    DIRECTION INPUT ;
    USE SIGNAL ;
    PORT
      LAYER M3 ;
        RECT  52.452 17.136 52.47 17.28 ;
    END
  END i[512]
  PIN i[513]
    DIRECTION INPUT ;
    USE SIGNAL ;
    PORT
      LAYER M5 ;
        RECT  52.56 17.088 52.584 17.28 ;
    END
  END i[513]
  PIN i[514]
    DIRECTION INPUT ;
    USE SIGNAL ;
    PORT
      LAYER M3 ;
        RECT  52.668 17.136 52.686 17.28 ;
    END
  END i[514]
  PIN i[515]
    DIRECTION INPUT ;
    USE SIGNAL ;
    PORT
      LAYER M5 ;
        RECT  52.752 17.088 52.776 17.28 ;
    END
  END i[515]
  PIN i[516]
    DIRECTION INPUT ;
    USE SIGNAL ;
    PORT
      LAYER M3 ;
        RECT  52.848 17.136 52.866 17.28 ;
    END
  END i[516]
  PIN i[517]
    DIRECTION INPUT ;
    USE SIGNAL ;
    PORT
      LAYER M5 ;
        RECT  52.944 17.088 52.968 17.28 ;
    END
  END i[517]
  PIN i[518]
    DIRECTION INPUT ;
    USE SIGNAL ;
    PORT
      LAYER M3 ;
        RECT  53.064 17.136 53.082 17.28 ;
    END
  END i[518]
  PIN i[519]
    DIRECTION INPUT ;
    USE SIGNAL ;
    PORT
      LAYER M5 ;
        RECT  53.136 17.088 53.16 17.28 ;
    END
  END i[519]
  PIN i[51]
    DIRECTION INPUT ;
    USE SIGNAL ;
    PORT
      LAYER M5 ;
        RECT  7.2 17.088 7.224 17.28 ;
    END
  END i[51]
  PIN i[520]
    DIRECTION INPUT ;
    USE SIGNAL ;
    PORT
      LAYER M3 ;
        RECT  53.244 17.136 53.262 17.28 ;
    END
  END i[520]
  PIN i[521]
    DIRECTION INPUT ;
    USE SIGNAL ;
    PORT
      LAYER M5 ;
        RECT  53.328 17.088 53.352 17.28 ;
    END
  END i[521]
  PIN i[522]
    DIRECTION INPUT ;
    USE SIGNAL ;
    PORT
      LAYER M3 ;
        RECT  53.46 17.136 53.478 17.28 ;
    END
  END i[522]
  PIN i[523]
    DIRECTION INPUT ;
    USE SIGNAL ;
    PORT
      LAYER M5 ;
        RECT  53.568 17.088 53.592 17.28 ;
    END
  END i[523]
  PIN i[524]
    DIRECTION INPUT ;
    USE SIGNAL ;
    PORT
      LAYER M3 ;
        RECT  53.64 17.136 53.658 17.28 ;
    END
  END i[524]
  PIN i[525]
    DIRECTION INPUT ;
    USE SIGNAL ;
    PORT
      LAYER M5 ;
        RECT  53.76 17.088 53.784 17.28 ;
    END
  END i[525]
  PIN i[526]
    DIRECTION INPUT ;
    USE SIGNAL ;
    PORT
      LAYER M3 ;
        RECT  53.856 17.136 53.874 17.28 ;
    END
  END i[526]
  PIN i[527]
    DIRECTION INPUT ;
    USE SIGNAL ;
    PORT
      LAYER M5 ;
        RECT  53.952 17.088 53.976 17.28 ;
    END
  END i[527]
  PIN i[528]
    DIRECTION INPUT ;
    USE SIGNAL ;
    PORT
      LAYER M3 ;
        RECT  54.036 17.136 54.054 17.28 ;
    END
  END i[528]
  PIN i[529]
    DIRECTION INPUT ;
    USE SIGNAL ;
    PORT
      LAYER M5 ;
        RECT  54.144 17.088 54.168 17.28 ;
    END
  END i[529]
  PIN i[52]
    DIRECTION INPUT ;
    USE SIGNAL ;
    PORT
      LAYER M3 ;
        RECT  7.308 17.136 7.326 17.28 ;
    END
  END i[52]
  PIN i[530]
    DIRECTION INPUT ;
    USE SIGNAL ;
    PORT
      LAYER M3 ;
        RECT  54.252 17.136 54.27 17.28 ;
    END
  END i[530]
  PIN i[531]
    DIRECTION INPUT ;
    USE SIGNAL ;
    PORT
      LAYER M5 ;
        RECT  54.336 17.088 54.36 17.28 ;
    END
  END i[531]
  PIN i[532]
    DIRECTION INPUT ;
    USE SIGNAL ;
    PORT
      LAYER M3 ;
        RECT  54.432 17.136 54.45 17.28 ;
    END
  END i[532]
  PIN i[533]
    DIRECTION INPUT ;
    USE SIGNAL ;
    PORT
      LAYER M5 ;
        RECT  54.528 17.088 54.552 17.28 ;
    END
  END i[533]
  PIN i[534]
    DIRECTION INPUT ;
    USE SIGNAL ;
    PORT
      LAYER M3 ;
        RECT  54.612 17.136 54.63 17.28 ;
    END
  END i[534]
  PIN i[535]
    DIRECTION INPUT ;
    USE SIGNAL ;
    PORT
      LAYER M5 ;
        RECT  54.72 17.088 54.744 17.28 ;
    END
  END i[535]
  PIN i[536]
    DIRECTION INPUT ;
    USE SIGNAL ;
    PORT
      LAYER M3 ;
        RECT  54.828 17.136 54.846 17.28 ;
    END
  END i[536]
  PIN i[537]
    DIRECTION INPUT ;
    USE SIGNAL ;
    PORT
      LAYER M5 ;
        RECT  54.912 17.088 54.936 17.28 ;
    END
  END i[537]
  PIN i[538]
    DIRECTION INPUT ;
    USE SIGNAL ;
    PORT
      LAYER M3 ;
        RECT  55.008 17.136 55.026 17.28 ;
    END
  END i[538]
  PIN i[539]
    DIRECTION INPUT ;
    USE SIGNAL ;
    PORT
      LAYER M5 ;
        RECT  55.104 17.088 55.128 17.28 ;
    END
  END i[539]
  PIN i[53]
    DIRECTION INPUT ;
    USE SIGNAL ;
    PORT
      LAYER M5 ;
        RECT  7.392 17.088 7.416 17.28 ;
    END
  END i[53]
  PIN i[540]
    DIRECTION INPUT ;
    USE SIGNAL ;
    PORT
      LAYER M3 ;
        RECT  55.224 17.136 55.242 17.28 ;
    END
  END i[540]
  PIN i[541]
    DIRECTION INPUT ;
    USE SIGNAL ;
    PORT
      LAYER M5 ;
        RECT  55.296 17.088 55.32 17.28 ;
    END
  END i[541]
  PIN i[542]
    DIRECTION INPUT ;
    USE SIGNAL ;
    PORT
      LAYER M3 ;
        RECT  55.404 17.136 55.422 17.28 ;
    END
  END i[542]
  PIN i[543]
    DIRECTION INPUT ;
    USE SIGNAL ;
    PORT
      LAYER M5 ;
        RECT  55.488 17.088 55.512 17.28 ;
    END
  END i[543]
  PIN i[544]
    DIRECTION INPUT ;
    USE SIGNAL ;
    PORT
      LAYER M3 ;
        RECT  55.62 17.136 55.638 17.28 ;
    END
  END i[544]
  PIN i[545]
    DIRECTION INPUT ;
    USE SIGNAL ;
    PORT
      LAYER M5 ;
        RECT  55.728 17.088 55.752 17.28 ;
    END
  END i[545]
  PIN i[546]
    DIRECTION INPUT ;
    USE SIGNAL ;
    PORT
      LAYER M3 ;
        RECT  55.8 17.136 55.818 17.28 ;
    END
  END i[546]
  PIN i[547]
    DIRECTION INPUT ;
    USE SIGNAL ;
    PORT
      LAYER M5 ;
        RECT  55.92 17.088 55.944 17.28 ;
    END
  END i[547]
  PIN i[548]
    DIRECTION INPUT ;
    USE SIGNAL ;
    PORT
      LAYER M3 ;
        RECT  56.016 17.136 56.034 17.28 ;
    END
  END i[548]
  PIN i[549]
    DIRECTION INPUT ;
    USE SIGNAL ;
    PORT
      LAYER M5 ;
        RECT  56.112 17.088 56.136 17.28 ;
    END
  END i[549]
  PIN i[54]
    DIRECTION INPUT ;
    USE SIGNAL ;
    PORT
      LAYER M3 ;
        RECT  7.488 17.136 7.506 17.28 ;
    END
  END i[54]
  PIN i[550]
    DIRECTION INPUT ;
    USE SIGNAL ;
    PORT
      LAYER M3 ;
        RECT  56.196 17.136 56.214 17.28 ;
    END
  END i[550]
  PIN i[551]
    DIRECTION INPUT ;
    USE SIGNAL ;
    PORT
      LAYER M5 ;
        RECT  56.304 17.088 56.328 17.28 ;
    END
  END i[551]
  PIN i[552]
    DIRECTION INPUT ;
    USE SIGNAL ;
    PORT
      LAYER M3 ;
        RECT  56.412 17.136 56.43 17.28 ;
    END
  END i[552]
  PIN i[553]
    DIRECTION INPUT ;
    USE SIGNAL ;
    PORT
      LAYER M5 ;
        RECT  56.496 17.088 56.52 17.28 ;
    END
  END i[553]
  PIN i[554]
    DIRECTION INPUT ;
    USE SIGNAL ;
    PORT
      LAYER M3 ;
        RECT  56.592 17.136 56.61 17.28 ;
    END
  END i[554]
  PIN i[555]
    DIRECTION INPUT ;
    USE SIGNAL ;
    PORT
      LAYER M5 ;
        RECT  56.688 17.088 56.712 17.28 ;
    END
  END i[555]
  PIN i[556]
    DIRECTION INPUT ;
    USE SIGNAL ;
    PORT
      LAYER M3 ;
        RECT  56.772 17.136 56.79 17.28 ;
    END
  END i[556]
  PIN i[557]
    DIRECTION INPUT ;
    USE SIGNAL ;
    PORT
      LAYER M5 ;
        RECT  56.88 17.088 56.904 17.28 ;
    END
  END i[557]
  PIN i[558]
    DIRECTION INPUT ;
    USE SIGNAL ;
    PORT
      LAYER M3 ;
        RECT  56.988 17.136 57.006 17.28 ;
    END
  END i[558]
  PIN i[559]
    DIRECTION INPUT ;
    USE SIGNAL ;
    PORT
      LAYER M5 ;
        RECT  57.072 17.088 57.096 17.28 ;
    END
  END i[559]
  PIN i[55]
    DIRECTION INPUT ;
    USE SIGNAL ;
    PORT
      LAYER M5 ;
        RECT  7.584 17.088 7.608 17.28 ;
    END
  END i[55]
  PIN i[560]
    DIRECTION INPUT ;
    USE SIGNAL ;
    PORT
      LAYER M3 ;
        RECT  57.168 17.136 57.186 17.28 ;
    END
  END i[560]
  PIN i[561]
    DIRECTION INPUT ;
    USE SIGNAL ;
    PORT
      LAYER M5 ;
        RECT  57.264 17.088 57.288 17.28 ;
    END
  END i[561]
  PIN i[562]
    DIRECTION INPUT ;
    USE SIGNAL ;
    PORT
      LAYER M3 ;
        RECT  57.384 17.136 57.402 17.28 ;
    END
  END i[562]
  PIN i[563]
    DIRECTION INPUT ;
    USE SIGNAL ;
    PORT
      LAYER M5 ;
        RECT  57.456 17.088 57.48 17.28 ;
    END
  END i[563]
  PIN i[564]
    DIRECTION INPUT ;
    USE SIGNAL ;
    PORT
      LAYER M3 ;
        RECT  57.564 17.136 57.582 17.28 ;
    END
  END i[564]
  PIN i[565]
    DIRECTION INPUT ;
    USE SIGNAL ;
    PORT
      LAYER M5 ;
        RECT  57.648 17.088 57.672 17.28 ;
    END
  END i[565]
  PIN i[566]
    DIRECTION INPUT ;
    USE SIGNAL ;
    PORT
      LAYER M3 ;
        RECT  57.78 17.136 57.798 17.28 ;
    END
  END i[566]
  PIN i[567]
    DIRECTION INPUT ;
    USE SIGNAL ;
    PORT
      LAYER M5 ;
        RECT  57.888 17.088 57.912 17.28 ;
    END
  END i[567]
  PIN i[568]
    DIRECTION INPUT ;
    USE SIGNAL ;
    PORT
      LAYER M3 ;
        RECT  57.96 17.136 57.978 17.28 ;
    END
  END i[568]
  PIN i[569]
    DIRECTION INPUT ;
    USE SIGNAL ;
    PORT
      LAYER M5 ;
        RECT  58.08 17.088 58.104 17.28 ;
    END
  END i[569]
  PIN i[56]
    DIRECTION INPUT ;
    USE SIGNAL ;
    PORT
      LAYER M3 ;
        RECT  7.704 17.136 7.722 17.28 ;
    END
  END i[56]
  PIN i[570]
    DIRECTION INPUT ;
    USE SIGNAL ;
    PORT
      LAYER M3 ;
        RECT  58.176 17.136 58.194 17.28 ;
    END
  END i[570]
  PIN i[571]
    DIRECTION INPUT ;
    USE SIGNAL ;
    PORT
      LAYER M5 ;
        RECT  58.272 17.088 58.296 17.28 ;
    END
  END i[571]
  PIN i[572]
    DIRECTION INPUT ;
    USE SIGNAL ;
    PORT
      LAYER M3 ;
        RECT  58.356 17.136 58.374 17.28 ;
    END
  END i[572]
  PIN i[573]
    DIRECTION INPUT ;
    USE SIGNAL ;
    PORT
      LAYER M5 ;
        RECT  58.464 17.088 58.488 17.28 ;
    END
  END i[573]
  PIN i[574]
    DIRECTION INPUT ;
    USE SIGNAL ;
    PORT
      LAYER M3 ;
        RECT  58.572 17.136 58.59 17.28 ;
    END
  END i[574]
  PIN i[575]
    DIRECTION INPUT ;
    USE SIGNAL ;
    PORT
      LAYER M5 ;
        RECT  58.656 17.088 58.68 17.28 ;
    END
  END i[575]
  PIN i[576]
    DIRECTION INPUT ;
    USE SIGNAL ;
    PORT
      LAYER M3 ;
        RECT  58.752 17.136 58.77 17.28 ;
    END
  END i[576]
  PIN i[577]
    DIRECTION INPUT ;
    USE SIGNAL ;
    PORT
      LAYER M5 ;
        RECT  58.848 17.088 58.872 17.28 ;
    END
  END i[577]
  PIN i[578]
    DIRECTION INPUT ;
    USE SIGNAL ;
    PORT
      LAYER M3 ;
        RECT  58.932 17.136 58.95 17.28 ;
    END
  END i[578]
  PIN i[579]
    DIRECTION INPUT ;
    USE SIGNAL ;
    PORT
      LAYER M5 ;
        RECT  59.04 17.088 59.064 17.28 ;
    END
  END i[579]
  PIN i[57]
    DIRECTION INPUT ;
    USE SIGNAL ;
    PORT
      LAYER M5 ;
        RECT  7.776 17.088 7.8 17.28 ;
    END
  END i[57]
  PIN i[580]
    DIRECTION INPUT ;
    USE SIGNAL ;
    PORT
      LAYER M3 ;
        RECT  59.148 17.136 59.166 17.28 ;
    END
  END i[580]
  PIN i[581]
    DIRECTION INPUT ;
    USE SIGNAL ;
    PORT
      LAYER M5 ;
        RECT  59.232 17.088 59.256 17.28 ;
    END
  END i[581]
  PIN i[582]
    DIRECTION INPUT ;
    USE SIGNAL ;
    PORT
      LAYER M3 ;
        RECT  59.328 17.136 59.346 17.28 ;
    END
  END i[582]
  PIN i[583]
    DIRECTION INPUT ;
    USE SIGNAL ;
    PORT
      LAYER M5 ;
        RECT  59.424 17.088 59.448 17.28 ;
    END
  END i[583]
  PIN i[584]
    DIRECTION INPUT ;
    USE SIGNAL ;
    PORT
      LAYER M3 ;
        RECT  59.544 17.136 59.562 17.28 ;
    END
  END i[584]
  PIN i[585]
    DIRECTION INPUT ;
    USE SIGNAL ;
    PORT
      LAYER M5 ;
        RECT  59.616 17.088 59.64 17.28 ;
    END
  END i[585]
  PIN i[586]
    DIRECTION INPUT ;
    USE SIGNAL ;
    PORT
      LAYER M3 ;
        RECT  59.724 17.136 59.742 17.28 ;
    END
  END i[586]
  PIN i[587]
    DIRECTION INPUT ;
    USE SIGNAL ;
    PORT
      LAYER M5 ;
        RECT  59.808 17.088 59.832 17.28 ;
    END
  END i[587]
  PIN i[588]
    DIRECTION INPUT ;
    USE SIGNAL ;
    PORT
      LAYER M3 ;
        RECT  59.94 17.136 59.958 17.28 ;
    END
  END i[588]
  PIN i[589]
    DIRECTION INPUT ;
    USE SIGNAL ;
    PORT
      LAYER M5 ;
        RECT  60.048 17.088 60.072 17.28 ;
    END
  END i[589]
  PIN i[58]
    DIRECTION INPUT ;
    USE SIGNAL ;
    PORT
      LAYER M3 ;
        RECT  7.884 17.136 7.902 17.28 ;
    END
  END i[58]
  PIN i[590]
    DIRECTION INPUT ;
    USE SIGNAL ;
    PORT
      LAYER M3 ;
        RECT  60.12 17.136 60.138 17.28 ;
    END
  END i[590]
  PIN i[591]
    DIRECTION INPUT ;
    USE SIGNAL ;
    PORT
      LAYER M5 ;
        RECT  60.24 17.088 60.264 17.28 ;
    END
  END i[591]
  PIN i[592]
    DIRECTION INPUT ;
    USE SIGNAL ;
    PORT
      LAYER M3 ;
        RECT  60.336 17.136 60.354 17.28 ;
    END
  END i[592]
  PIN i[593]
    DIRECTION INPUT ;
    USE SIGNAL ;
    PORT
      LAYER M5 ;
        RECT  60.432 17.088 60.456 17.28 ;
    END
  END i[593]
  PIN i[594]
    DIRECTION INPUT ;
    USE SIGNAL ;
    PORT
      LAYER M3 ;
        RECT  60.516 17.136 60.534 17.28 ;
    END
  END i[594]
  PIN i[595]
    DIRECTION INPUT ;
    USE SIGNAL ;
    PORT
      LAYER M5 ;
        RECT  60.624 17.088 60.648 17.28 ;
    END
  END i[595]
  PIN i[596]
    DIRECTION INPUT ;
    USE SIGNAL ;
    PORT
      LAYER M3 ;
        RECT  60.732 17.136 60.75 17.28 ;
    END
  END i[596]
  PIN i[597]
    DIRECTION INPUT ;
    USE SIGNAL ;
    PORT
      LAYER M5 ;
        RECT  60.816 17.088 60.84 17.28 ;
    END
  END i[597]
  PIN i[598]
    DIRECTION INPUT ;
    USE SIGNAL ;
    PORT
      LAYER M3 ;
        RECT  60.912 17.136 60.93 17.28 ;
    END
  END i[598]
  PIN i[599]
    DIRECTION INPUT ;
    USE SIGNAL ;
    PORT
      LAYER M5 ;
        RECT  61.008 17.088 61.032 17.28 ;
    END
  END i[599]
  PIN i[59]
    DIRECTION INPUT ;
    USE SIGNAL ;
    PORT
      LAYER M5 ;
        RECT  7.968 17.088 7.992 17.28 ;
    END
  END i[59]
  PIN i[5]
    DIRECTION INPUT ;
    USE SIGNAL ;
    PORT
      LAYER M5 ;
        RECT  2.688 17.088 2.712 17.28 ;
    END
  END i[5]
  PIN i[600]
    DIRECTION INPUT ;
    USE SIGNAL ;
    PORT
      LAYER M3 ;
        RECT  61.092 17.136 61.11 17.28 ;
    END
  END i[600]
  PIN i[601]
    DIRECTION INPUT ;
    USE SIGNAL ;
    PORT
      LAYER M5 ;
        RECT  61.2 17.088 61.224 17.28 ;
    END
  END i[601]
  PIN i[602]
    DIRECTION INPUT ;
    USE SIGNAL ;
    PORT
      LAYER M3 ;
        RECT  61.308 17.136 61.326 17.28 ;
    END
  END i[602]
  PIN i[603]
    DIRECTION INPUT ;
    USE SIGNAL ;
    PORT
      LAYER M5 ;
        RECT  61.392 17.088 61.416 17.28 ;
    END
  END i[603]
  PIN i[604]
    DIRECTION INPUT ;
    USE SIGNAL ;
    PORT
      LAYER M3 ;
        RECT  61.488 17.136 61.506 17.28 ;
    END
  END i[604]
  PIN i[605]
    DIRECTION INPUT ;
    USE SIGNAL ;
    PORT
      LAYER M5 ;
        RECT  61.584 17.088 61.608 17.28 ;
    END
  END i[605]
  PIN i[606]
    DIRECTION INPUT ;
    USE SIGNAL ;
    PORT
      LAYER M3 ;
        RECT  61.704 17.136 61.722 17.28 ;
    END
  END i[606]
  PIN i[607]
    DIRECTION INPUT ;
    USE SIGNAL ;
    PORT
      LAYER M5 ;
        RECT  61.776 17.088 61.8 17.28 ;
    END
  END i[607]
  PIN i[608]
    DIRECTION INPUT ;
    USE SIGNAL ;
    PORT
      LAYER M3 ;
        RECT  61.884 17.136 61.902 17.28 ;
    END
  END i[608]
  PIN i[609]
    DIRECTION INPUT ;
    USE SIGNAL ;
    PORT
      LAYER M5 ;
        RECT  61.968 17.088 61.992 17.28 ;
    END
  END i[609]
  PIN i[60]
    DIRECTION INPUT ;
    USE SIGNAL ;
    PORT
      LAYER M3 ;
        RECT  8.1 17.136 8.118 17.28 ;
    END
  END i[60]
  PIN i[610]
    DIRECTION INPUT ;
    USE SIGNAL ;
    PORT
      LAYER M3 ;
        RECT  62.1 17.136 62.118 17.28 ;
    END
  END i[610]
  PIN i[611]
    DIRECTION INPUT ;
    USE SIGNAL ;
    PORT
      LAYER M5 ;
        RECT  62.208 17.088 62.232 17.28 ;
    END
  END i[611]
  PIN i[612]
    DIRECTION INPUT ;
    USE SIGNAL ;
    PORT
      LAYER M3 ;
        RECT  62.28 17.136 62.298 17.28 ;
    END
  END i[612]
  PIN i[613]
    DIRECTION INPUT ;
    USE SIGNAL ;
    PORT
      LAYER M5 ;
        RECT  62.4 17.088 62.424 17.28 ;
    END
  END i[613]
  PIN i[614]
    DIRECTION INPUT ;
    USE SIGNAL ;
    PORT
      LAYER M3 ;
        RECT  62.496 17.136 62.514 17.28 ;
    END
  END i[614]
  PIN i[615]
    DIRECTION INPUT ;
    USE SIGNAL ;
    PORT
      LAYER M5 ;
        RECT  62.592 17.088 62.616 17.28 ;
    END
  END i[615]
  PIN i[616]
    DIRECTION INPUT ;
    USE SIGNAL ;
    PORT
      LAYER M3 ;
        RECT  62.676 17.136 62.694 17.28 ;
    END
  END i[616]
  PIN i[617]
    DIRECTION INPUT ;
    USE SIGNAL ;
    PORT
      LAYER M5 ;
        RECT  62.784 17.088 62.808 17.28 ;
    END
  END i[617]
  PIN i[618]
    DIRECTION INPUT ;
    USE SIGNAL ;
    PORT
      LAYER M3 ;
        RECT  62.892 17.136 62.91 17.28 ;
    END
  END i[618]
  PIN i[619]
    DIRECTION INPUT ;
    USE SIGNAL ;
    PORT
      LAYER M5 ;
        RECT  62.976 17.088 63 17.28 ;
    END
  END i[619]
  PIN i[61]
    DIRECTION INPUT ;
    USE SIGNAL ;
    PORT
      LAYER M5 ;
        RECT  8.208 17.088 8.232 17.28 ;
    END
  END i[61]
  PIN i[620]
    DIRECTION INPUT ;
    USE SIGNAL ;
    PORT
      LAYER M3 ;
        RECT  63.072 17.136 63.09 17.28 ;
    END
  END i[620]
  PIN i[621]
    DIRECTION INPUT ;
    USE SIGNAL ;
    PORT
      LAYER M5 ;
        RECT  63.168 17.088 63.192 17.28 ;
    END
  END i[621]
  PIN i[622]
    DIRECTION INPUT ;
    USE SIGNAL ;
    PORT
      LAYER M3 ;
        RECT  63.252 17.136 63.27 17.28 ;
    END
  END i[622]
  PIN i[623]
    DIRECTION INPUT ;
    USE SIGNAL ;
    PORT
      LAYER M5 ;
        RECT  63.36 17.088 63.384 17.28 ;
    END
  END i[623]
  PIN i[624]
    DIRECTION INPUT ;
    USE SIGNAL ;
    PORT
      LAYER M3 ;
        RECT  63.468 17.136 63.486 17.28 ;
    END
  END i[624]
  PIN i[625]
    DIRECTION INPUT ;
    USE SIGNAL ;
    PORT
      LAYER M5 ;
        RECT  63.552 17.088 63.576 17.28 ;
    END
  END i[625]
  PIN i[626]
    DIRECTION INPUT ;
    USE SIGNAL ;
    PORT
      LAYER M3 ;
        RECT  63.648 17.136 63.666 17.28 ;
    END
  END i[626]
  PIN i[627]
    DIRECTION INPUT ;
    USE SIGNAL ;
    PORT
      LAYER M5 ;
        RECT  63.744 17.088 63.768 17.28 ;
    END
  END i[627]
  PIN i[628]
    DIRECTION INPUT ;
    USE SIGNAL ;
    PORT
      LAYER M3 ;
        RECT  63.864 17.136 63.882 17.28 ;
    END
  END i[628]
  PIN i[629]
    DIRECTION INPUT ;
    USE SIGNAL ;
    PORT
      LAYER M5 ;
        RECT  63.936 17.088 63.96 17.28 ;
    END
  END i[629]
  PIN i[62]
    DIRECTION INPUT ;
    USE SIGNAL ;
    PORT
      LAYER M3 ;
        RECT  8.28 17.136 8.298 17.28 ;
    END
  END i[62]
  PIN i[630]
    DIRECTION INPUT ;
    USE SIGNAL ;
    PORT
      LAYER M3 ;
        RECT  64.044 17.136 64.062 17.28 ;
    END
  END i[630]
  PIN i[631]
    DIRECTION INPUT ;
    USE SIGNAL ;
    PORT
      LAYER M5 ;
        RECT  64.128 17.088 64.152 17.28 ;
    END
  END i[631]
  PIN i[632]
    DIRECTION INPUT ;
    USE SIGNAL ;
    PORT
      LAYER M3 ;
        RECT  64.26 17.136 64.278 17.28 ;
    END
  END i[632]
  PIN i[633]
    DIRECTION INPUT ;
    USE SIGNAL ;
    PORT
      LAYER M5 ;
        RECT  64.368 17.088 64.392 17.28 ;
    END
  END i[633]
  PIN i[634]
    DIRECTION INPUT ;
    USE SIGNAL ;
    PORT
      LAYER M3 ;
        RECT  64.44 17.136 64.458 17.28 ;
    END
  END i[634]
  PIN i[635]
    DIRECTION INPUT ;
    USE SIGNAL ;
    PORT
      LAYER M5 ;
        RECT  64.56 17.088 64.584 17.28 ;
    END
  END i[635]
  PIN i[636]
    DIRECTION INPUT ;
    USE SIGNAL ;
    PORT
      LAYER M3 ;
        RECT  64.656 17.136 64.674 17.28 ;
    END
  END i[636]
  PIN i[637]
    DIRECTION INPUT ;
    USE SIGNAL ;
    PORT
      LAYER M5 ;
        RECT  64.752 17.088 64.776 17.28 ;
    END
  END i[637]
  PIN i[638]
    DIRECTION INPUT ;
    USE SIGNAL ;
    PORT
      LAYER M3 ;
        RECT  64.836 17.136 64.854 17.28 ;
    END
  END i[638]
  PIN i[639]
    DIRECTION INPUT ;
    USE SIGNAL ;
    PORT
      LAYER M5 ;
        RECT  64.944 17.088 64.968 17.28 ;
    END
  END i[639]
  PIN i[63]
    DIRECTION INPUT ;
    USE SIGNAL ;
    PORT
      LAYER M5 ;
        RECT  8.4 17.088 8.424 17.28 ;
    END
  END i[63]
  PIN i[640]
    DIRECTION INPUT ;
    USE SIGNAL ;
    PORT
      LAYER M3 ;
        RECT  65.052 17.136 65.07 17.28 ;
    END
  END i[640]
  PIN i[641]
    DIRECTION INPUT ;
    USE SIGNAL ;
    PORT
      LAYER M5 ;
        RECT  65.136 17.088 65.16 17.28 ;
    END
  END i[641]
  PIN i[642]
    DIRECTION INPUT ;
    USE SIGNAL ;
    PORT
      LAYER M3 ;
        RECT  65.232 17.136 65.25 17.28 ;
    END
  END i[642]
  PIN i[643]
    DIRECTION INPUT ;
    USE SIGNAL ;
    PORT
      LAYER M5 ;
        RECT  65.328 17.088 65.352 17.28 ;
    END
  END i[643]
  PIN i[644]
    DIRECTION INPUT ;
    USE SIGNAL ;
    PORT
      LAYER M3 ;
        RECT  65.412 17.136 65.43 17.28 ;
    END
  END i[644]
  PIN i[645]
    DIRECTION INPUT ;
    USE SIGNAL ;
    PORT
      LAYER M5 ;
        RECT  65.52 17.088 65.544 17.28 ;
    END
  END i[645]
  PIN i[646]
    DIRECTION INPUT ;
    USE SIGNAL ;
    PORT
      LAYER M3 ;
        RECT  65.628 17.136 65.646 17.28 ;
    END
  END i[646]
  PIN i[647]
    DIRECTION INPUT ;
    USE SIGNAL ;
    PORT
      LAYER M5 ;
        RECT  65.712 17.088 65.736 17.28 ;
    END
  END i[647]
  PIN i[648]
    DIRECTION INPUT ;
    USE SIGNAL ;
    PORT
      LAYER M3 ;
        RECT  65.808 17.136 65.826 17.28 ;
    END
  END i[648]
  PIN i[649]
    DIRECTION INPUT ;
    USE SIGNAL ;
    PORT
      LAYER M5 ;
        RECT  65.904 17.088 65.928 17.28 ;
    END
  END i[649]
  PIN i[64]
    DIRECTION INPUT ;
    USE SIGNAL ;
    PORT
      LAYER M3 ;
        RECT  8.496 17.136 8.514 17.28 ;
    END
  END i[64]
  PIN i[650]
    DIRECTION INPUT ;
    USE SIGNAL ;
    PORT
      LAYER M3 ;
        RECT  66.024 17.136 66.042 17.28 ;
    END
  END i[650]
  PIN i[651]
    DIRECTION INPUT ;
    USE SIGNAL ;
    PORT
      LAYER M5 ;
        RECT  66.096 17.088 66.12 17.28 ;
    END
  END i[651]
  PIN i[652]
    DIRECTION INPUT ;
    USE SIGNAL ;
    PORT
      LAYER M3 ;
        RECT  66.204 17.136 66.222 17.28 ;
    END
  END i[652]
  PIN i[653]
    DIRECTION INPUT ;
    USE SIGNAL ;
    PORT
      LAYER M5 ;
        RECT  66.288 17.088 66.312 17.28 ;
    END
  END i[653]
  PIN i[654]
    DIRECTION INPUT ;
    USE SIGNAL ;
    PORT
      LAYER M3 ;
        RECT  66.42 17.136 66.438 17.28 ;
    END
  END i[654]
  PIN i[655]
    DIRECTION INPUT ;
    USE SIGNAL ;
    PORT
      LAYER M5 ;
        RECT  66.528 17.088 66.552 17.28 ;
    END
  END i[655]
  PIN i[656]
    DIRECTION INPUT ;
    USE SIGNAL ;
    PORT
      LAYER M3 ;
        RECT  66.6 17.136 66.618 17.28 ;
    END
  END i[656]
  PIN i[657]
    DIRECTION INPUT ;
    USE SIGNAL ;
    PORT
      LAYER M5 ;
        RECT  66.72 17.088 66.744 17.28 ;
    END
  END i[657]
  PIN i[658]
    DIRECTION INPUT ;
    USE SIGNAL ;
    PORT
      LAYER M3 ;
        RECT  66.816 17.136 66.834 17.28 ;
    END
  END i[658]
  PIN i[659]
    DIRECTION INPUT ;
    USE SIGNAL ;
    PORT
      LAYER M5 ;
        RECT  66.912 17.088 66.936 17.28 ;
    END
  END i[659]
  PIN i[65]
    DIRECTION INPUT ;
    USE SIGNAL ;
    PORT
      LAYER M5 ;
        RECT  8.592 17.088 8.616 17.28 ;
    END
  END i[65]
  PIN i[660]
    DIRECTION INPUT ;
    USE SIGNAL ;
    PORT
      LAYER M3 ;
        RECT  66.996 17.136 67.014 17.28 ;
    END
  END i[660]
  PIN i[661]
    DIRECTION INPUT ;
    USE SIGNAL ;
    PORT
      LAYER M5 ;
        RECT  67.104 17.088 67.128 17.28 ;
    END
  END i[661]
  PIN i[662]
    DIRECTION INPUT ;
    USE SIGNAL ;
    PORT
      LAYER M3 ;
        RECT  67.212 17.136 67.23 17.28 ;
    END
  END i[662]
  PIN i[663]
    DIRECTION INPUT ;
    USE SIGNAL ;
    PORT
      LAYER M5 ;
        RECT  67.296 17.088 67.32 17.28 ;
    END
  END i[663]
  PIN i[664]
    DIRECTION INPUT ;
    USE SIGNAL ;
    PORT
      LAYER M3 ;
        RECT  67.392 17.136 67.41 17.28 ;
    END
  END i[664]
  PIN i[665]
    DIRECTION INPUT ;
    USE SIGNAL ;
    PORT
      LAYER M5 ;
        RECT  67.488 17.088 67.512 17.28 ;
    END
  END i[665]
  PIN i[666]
    DIRECTION INPUT ;
    USE SIGNAL ;
    PORT
      LAYER M3 ;
        RECT  67.572 17.136 67.59 17.28 ;
    END
  END i[666]
  PIN i[667]
    DIRECTION INPUT ;
    USE SIGNAL ;
    PORT
      LAYER M5 ;
        RECT  67.68 17.088 67.704 17.28 ;
    END
  END i[667]
  PIN i[668]
    DIRECTION INPUT ;
    USE SIGNAL ;
    PORT
      LAYER M3 ;
        RECT  67.788 17.136 67.806 17.28 ;
    END
  END i[668]
  PIN i[669]
    DIRECTION INPUT ;
    USE SIGNAL ;
    PORT
      LAYER M5 ;
        RECT  67.872 17.088 67.896 17.28 ;
    END
  END i[669]
  PIN i[66]
    DIRECTION INPUT ;
    USE SIGNAL ;
    PORT
      LAYER M3 ;
        RECT  8.676 17.136 8.694 17.28 ;
    END
  END i[66]
  PIN i[670]
    DIRECTION INPUT ;
    USE SIGNAL ;
    PORT
      LAYER M3 ;
        RECT  67.968 17.136 67.986 17.28 ;
    END
  END i[670]
  PIN i[671]
    DIRECTION INPUT ;
    USE SIGNAL ;
    PORT
      LAYER M5 ;
        RECT  68.064 17.088 68.088 17.28 ;
    END
  END i[671]
  PIN i[672]
    DIRECTION INPUT ;
    USE SIGNAL ;
    PORT
      LAYER M3 ;
        RECT  68.184 17.136 68.202 17.28 ;
    END
  END i[672]
  PIN i[673]
    DIRECTION INPUT ;
    USE SIGNAL ;
    PORT
      LAYER M5 ;
        RECT  68.256 17.088 68.28 17.28 ;
    END
  END i[673]
  PIN i[674]
    DIRECTION INPUT ;
    USE SIGNAL ;
    PORT
      LAYER M3 ;
        RECT  68.364 17.136 68.382 17.28 ;
    END
  END i[674]
  PIN i[675]
    DIRECTION INPUT ;
    USE SIGNAL ;
    PORT
      LAYER M5 ;
        RECT  68.448 17.088 68.472 17.28 ;
    END
  END i[675]
  PIN i[676]
    DIRECTION INPUT ;
    USE SIGNAL ;
    PORT
      LAYER M3 ;
        RECT  68.58 17.136 68.598 17.28 ;
    END
  END i[676]
  PIN i[677]
    DIRECTION INPUT ;
    USE SIGNAL ;
    PORT
      LAYER M5 ;
        RECT  68.688 17.088 68.712 17.28 ;
    END
  END i[677]
  PIN i[678]
    DIRECTION INPUT ;
    USE SIGNAL ;
    PORT
      LAYER M3 ;
        RECT  68.76 17.136 68.778 17.28 ;
    END
  END i[678]
  PIN i[679]
    DIRECTION INPUT ;
    USE SIGNAL ;
    PORT
      LAYER M5 ;
        RECT  68.88 17.088 68.904 17.28 ;
    END
  END i[679]
  PIN i[67]
    DIRECTION INPUT ;
    USE SIGNAL ;
    PORT
      LAYER M5 ;
        RECT  8.784 17.088 8.808 17.28 ;
    END
  END i[67]
  PIN i[680]
    DIRECTION INPUT ;
    USE SIGNAL ;
    PORT
      LAYER M3 ;
        RECT  68.976 17.136 68.994 17.28 ;
    END
  END i[680]
  PIN i[681]
    DIRECTION INPUT ;
    USE SIGNAL ;
    PORT
      LAYER M5 ;
        RECT  69.072 17.088 69.096 17.28 ;
    END
  END i[681]
  PIN i[68]
    DIRECTION INPUT ;
    USE SIGNAL ;
    PORT
      LAYER M3 ;
        RECT  8.892 17.136 8.91 17.28 ;
    END
  END i[68]
  PIN i[69]
    DIRECTION INPUT ;
    USE SIGNAL ;
    PORT
      LAYER M5 ;
        RECT  8.976 17.088 9 17.28 ;
    END
  END i[69]
  PIN i[6]
    DIRECTION INPUT ;
    USE SIGNAL ;
    PORT
      LAYER M3 ;
        RECT  2.772 17.136 2.79 17.28 ;
    END
  END i[6]
  PIN i[70]
    DIRECTION INPUT ;
    USE SIGNAL ;
    PORT
      LAYER M3 ;
        RECT  9.072 17.136 9.09 17.28 ;
    END
  END i[70]
  PIN i[71]
    DIRECTION INPUT ;
    USE SIGNAL ;
    PORT
      LAYER M5 ;
        RECT  9.168 17.088 9.192 17.28 ;
    END
  END i[71]
  PIN i[72]
    DIRECTION INPUT ;
    USE SIGNAL ;
    PORT
      LAYER M3 ;
        RECT  9.252 17.136 9.27 17.28 ;
    END
  END i[72]
  PIN i[73]
    DIRECTION INPUT ;
    USE SIGNAL ;
    PORT
      LAYER M5 ;
        RECT  9.36 17.088 9.384 17.28 ;
    END
  END i[73]
  PIN i[74]
    DIRECTION INPUT ;
    USE SIGNAL ;
    PORT
      LAYER M3 ;
        RECT  9.468 17.136 9.486 17.28 ;
    END
  END i[74]
  PIN i[75]
    DIRECTION INPUT ;
    USE SIGNAL ;
    PORT
      LAYER M5 ;
        RECT  9.552 17.088 9.576 17.28 ;
    END
  END i[75]
  PIN i[76]
    DIRECTION INPUT ;
    USE SIGNAL ;
    PORT
      LAYER M3 ;
        RECT  9.648 17.136 9.666 17.28 ;
    END
  END i[76]
  PIN i[77]
    DIRECTION INPUT ;
    USE SIGNAL ;
    PORT
      LAYER M5 ;
        RECT  9.744 17.088 9.768 17.28 ;
    END
  END i[77]
  PIN i[78]
    DIRECTION INPUT ;
    USE SIGNAL ;
    PORT
      LAYER M3 ;
        RECT  9.864 17.136 9.882 17.28 ;
    END
  END i[78]
  PIN i[79]
    DIRECTION INPUT ;
    USE SIGNAL ;
    PORT
      LAYER M5 ;
        RECT  9.936 17.088 9.96 17.28 ;
    END
  END i[79]
  PIN i[7]
    DIRECTION INPUT ;
    USE SIGNAL ;
    PORT
      LAYER M5 ;
        RECT  2.88 17.088 2.904 17.28 ;
    END
  END i[7]
  PIN i[80]
    DIRECTION INPUT ;
    USE SIGNAL ;
    PORT
      LAYER M3 ;
        RECT  10.044 17.136 10.062 17.28 ;
    END
  END i[80]
  PIN i[81]
    DIRECTION INPUT ;
    USE SIGNAL ;
    PORT
      LAYER M5 ;
        RECT  10.128 17.088 10.152 17.28 ;
    END
  END i[81]
  PIN i[82]
    DIRECTION INPUT ;
    USE SIGNAL ;
    PORT
      LAYER M3 ;
        RECT  10.26 17.136 10.278 17.28 ;
    END
  END i[82]
  PIN i[83]
    DIRECTION INPUT ;
    USE SIGNAL ;
    PORT
      LAYER M5 ;
        RECT  10.368 17.088 10.392 17.28 ;
    END
  END i[83]
  PIN i[84]
    DIRECTION INPUT ;
    USE SIGNAL ;
    PORT
      LAYER M3 ;
        RECT  10.44 17.136 10.458 17.28 ;
    END
  END i[84]
  PIN i[85]
    DIRECTION INPUT ;
    USE SIGNAL ;
    PORT
      LAYER M5 ;
        RECT  10.56 17.088 10.584 17.28 ;
    END
  END i[85]
  PIN i[86]
    DIRECTION INPUT ;
    USE SIGNAL ;
    PORT
      LAYER M3 ;
        RECT  10.656 17.136 10.674 17.28 ;
    END
  END i[86]
  PIN i[87]
    DIRECTION INPUT ;
    USE SIGNAL ;
    PORT
      LAYER M5 ;
        RECT  10.752 17.088 10.776 17.28 ;
    END
  END i[87]
  PIN i[88]
    DIRECTION INPUT ;
    USE SIGNAL ;
    PORT
      LAYER M3 ;
        RECT  10.836 17.136 10.854 17.28 ;
    END
  END i[88]
  PIN i[89]
    DIRECTION INPUT ;
    USE SIGNAL ;
    PORT
      LAYER M5 ;
        RECT  10.944 17.088 10.968 17.28 ;
    END
  END i[89]
  PIN i[8]
    DIRECTION INPUT ;
    USE SIGNAL ;
    PORT
      LAYER M3 ;
        RECT  2.988 17.136 3.006 17.28 ;
    END
  END i[8]
  PIN i[90]
    DIRECTION INPUT ;
    USE SIGNAL ;
    PORT
      LAYER M3 ;
        RECT  11.052 17.136 11.07 17.28 ;
    END
  END i[90]
  PIN i[91]
    DIRECTION INPUT ;
    USE SIGNAL ;
    PORT
      LAYER M5 ;
        RECT  11.136 17.088 11.16 17.28 ;
    END
  END i[91]
  PIN i[92]
    DIRECTION INPUT ;
    USE SIGNAL ;
    PORT
      LAYER M3 ;
        RECT  11.232 17.136 11.25 17.28 ;
    END
  END i[92]
  PIN i[93]
    DIRECTION INPUT ;
    USE SIGNAL ;
    PORT
      LAYER M5 ;
        RECT  11.328 17.088 11.352 17.28 ;
    END
  END i[93]
  PIN i[94]
    DIRECTION INPUT ;
    USE SIGNAL ;
    PORT
      LAYER M3 ;
        RECT  11.412 17.136 11.43 17.28 ;
    END
  END i[94]
  PIN i[95]
    DIRECTION INPUT ;
    USE SIGNAL ;
    PORT
      LAYER M5 ;
        RECT  11.52 17.088 11.544 17.28 ;
    END
  END i[95]
  PIN i[96]
    DIRECTION INPUT ;
    USE SIGNAL ;
    PORT
      LAYER M3 ;
        RECT  11.628 17.136 11.646 17.28 ;
    END
  END i[96]
  PIN i[97]
    DIRECTION INPUT ;
    USE SIGNAL ;
    PORT
      LAYER M5 ;
        RECT  11.712 17.088 11.736 17.28 ;
    END
  END i[97]
  PIN i[98]
    DIRECTION INPUT ;
    USE SIGNAL ;
    PORT
      LAYER M3 ;
        RECT  11.808 17.136 11.826 17.28 ;
    END
  END i[98]
  PIN i[99]
    DIRECTION INPUT ;
    USE SIGNAL ;
    PORT
      LAYER M5 ;
        RECT  11.904 17.088 11.928 17.28 ;
    END
  END i[99]
  PIN i[9]
    DIRECTION INPUT ;
    USE SIGNAL ;
    PORT
      LAYER M5 ;
        RECT  3.072 17.088 3.096 17.28 ;
    END
  END i[9]
  PIN o[0]
    DIRECTION OUTPUT ;
    USE SIGNAL ;
    PORT
      LAYER M3 ;
        RECT  2.196 0 2.214 0.144 ;
    END
  END o[0]
  PIN o[100]
    DIRECTION OUTPUT ;
    USE SIGNAL ;
    PORT
      LAYER M3 ;
        RECT  11.988 0 12.006 0.144 ;
    END
  END o[100]
  PIN o[101]
    DIRECTION OUTPUT ;
    USE SIGNAL ;
    PORT
      LAYER M5 ;
        RECT  12.096 0 12.12 0.192 ;
    END
  END o[101]
  PIN o[102]
    DIRECTION OUTPUT ;
    USE SIGNAL ;
    PORT
      LAYER M3 ;
        RECT  12.204 0 12.222 0.144 ;
    END
  END o[102]
  PIN o[103]
    DIRECTION OUTPUT ;
    USE SIGNAL ;
    PORT
      LAYER M5 ;
        RECT  12.288 0 12.312 0.192 ;
    END
  END o[103]
  PIN o[104]
    DIRECTION OUTPUT ;
    USE SIGNAL ;
    PORT
      LAYER M3 ;
        RECT  12.384 0 12.402 0.144 ;
    END
  END o[104]
  PIN o[105]
    DIRECTION OUTPUT ;
    USE SIGNAL ;
    PORT
      LAYER M5 ;
        RECT  12.48 0 12.504 0.192 ;
    END
  END o[105]
  PIN o[106]
    DIRECTION OUTPUT ;
    USE SIGNAL ;
    PORT
      LAYER M3 ;
        RECT  12.6 0 12.618 0.144 ;
    END
  END o[106]
  PIN o[107]
    DIRECTION OUTPUT ;
    USE SIGNAL ;
    PORT
      LAYER M5 ;
        RECT  12.672 0 12.696 0.192 ;
    END
  END o[107]
  PIN o[108]
    DIRECTION OUTPUT ;
    USE SIGNAL ;
    PORT
      LAYER M3 ;
        RECT  12.78 0 12.798 0.144 ;
    END
  END o[108]
  PIN o[109]
    DIRECTION OUTPUT ;
    USE SIGNAL ;
    PORT
      LAYER M5 ;
        RECT  12.864 0 12.888 0.192 ;
    END
  END o[109]
  PIN o[10]
    DIRECTION OUTPUT ;
    USE SIGNAL ;
    PORT
      LAYER M3 ;
        RECT  3.168 0 3.186 0.144 ;
    END
  END o[10]
  PIN o[110]
    DIRECTION OUTPUT ;
    USE SIGNAL ;
    PORT
      LAYER M3 ;
        RECT  12.996 0 13.014 0.144 ;
    END
  END o[110]
  PIN o[111]
    DIRECTION OUTPUT ;
    USE SIGNAL ;
    PORT
      LAYER M5 ;
        RECT  13.056 0 13.08 0.192 ;
    END
  END o[111]
  PIN o[112]
    DIRECTION OUTPUT ;
    USE SIGNAL ;
    PORT
      LAYER M3 ;
        RECT  13.176 0 13.194 0.144 ;
    END
  END o[112]
  PIN o[113]
    DIRECTION OUTPUT ;
    USE SIGNAL ;
    PORT
      LAYER M5 ;
        RECT  13.296 0 13.32 0.192 ;
    END
  END o[113]
  PIN o[114]
    DIRECTION OUTPUT ;
    USE SIGNAL ;
    PORT
      LAYER M3 ;
        RECT  13.392 0 13.41 0.144 ;
    END
  END o[114]
  PIN o[115]
    DIRECTION OUTPUT ;
    USE SIGNAL ;
    PORT
      LAYER M5 ;
        RECT  13.488 0 13.512 0.192 ;
    END
  END o[115]
  PIN o[116]
    DIRECTION OUTPUT ;
    USE SIGNAL ;
    PORT
      LAYER M3 ;
        RECT  13.572 0 13.59 0.144 ;
    END
  END o[116]
  PIN o[117]
    DIRECTION OUTPUT ;
    USE SIGNAL ;
    PORT
      LAYER M5 ;
        RECT  13.68 0 13.704 0.192 ;
    END
  END o[117]
  PIN o[118]
    DIRECTION OUTPUT ;
    USE SIGNAL ;
    PORT
      LAYER M3 ;
        RECT  13.752 0 13.77 0.144 ;
    END
  END o[118]
  PIN o[119]
    DIRECTION OUTPUT ;
    USE SIGNAL ;
    PORT
      LAYER M5 ;
        RECT  13.872 0 13.896 0.192 ;
    END
  END o[119]
  PIN o[11]
    DIRECTION OUTPUT ;
    USE SIGNAL ;
    PORT
      LAYER M5 ;
        RECT  3.264 0 3.288 0.192 ;
    END
  END o[11]
  PIN o[120]
    DIRECTION OUTPUT ;
    USE SIGNAL ;
    PORT
      LAYER M3 ;
        RECT  13.968 0 13.986 0.144 ;
    END
  END o[120]
  PIN o[121]
    DIRECTION OUTPUT ;
    USE SIGNAL ;
    PORT
      LAYER M5 ;
        RECT  14.064 0 14.088 0.192 ;
    END
  END o[121]
  PIN o[122]
    DIRECTION OUTPUT ;
    USE SIGNAL ;
    PORT
      LAYER M3 ;
        RECT  14.148 0 14.166 0.144 ;
    END
  END o[122]
  PIN o[123]
    DIRECTION OUTPUT ;
    USE SIGNAL ;
    PORT
      LAYER M5 ;
        RECT  14.256 0 14.28 0.192 ;
    END
  END o[123]
  PIN o[124]
    DIRECTION OUTPUT ;
    USE SIGNAL ;
    PORT
      LAYER M3 ;
        RECT  14.364 0 14.382 0.144 ;
    END
  END o[124]
  PIN o[125]
    DIRECTION OUTPUT ;
    USE SIGNAL ;
    PORT
      LAYER M5 ;
        RECT  14.448 0 14.472 0.192 ;
    END
  END o[125]
  PIN o[126]
    DIRECTION OUTPUT ;
    USE SIGNAL ;
    PORT
      LAYER M3 ;
        RECT  14.544 0 14.562 0.144 ;
    END
  END o[126]
  PIN o[127]
    DIRECTION OUTPUT ;
    USE SIGNAL ;
    PORT
      LAYER M5 ;
        RECT  14.64 0 14.664 0.192 ;
    END
  END o[127]
  PIN o[128]
    DIRECTION OUTPUT ;
    USE SIGNAL ;
    PORT
      LAYER M3 ;
        RECT  14.76 0 14.778 0.144 ;
    END
  END o[128]
  PIN o[129]
    DIRECTION OUTPUT ;
    USE SIGNAL ;
    PORT
      LAYER M5 ;
        RECT  14.832 0 14.856 0.192 ;
    END
  END o[129]
  PIN o[12]
    DIRECTION OUTPUT ;
    USE SIGNAL ;
    PORT
      LAYER M3 ;
        RECT  3.384 0 3.402 0.144 ;
    END
  END o[12]
  PIN o[130]
    DIRECTION OUTPUT ;
    USE SIGNAL ;
    PORT
      LAYER M3 ;
        RECT  14.94 0 14.958 0.144 ;
    END
  END o[130]
  PIN o[131]
    DIRECTION OUTPUT ;
    USE SIGNAL ;
    PORT
      LAYER M5 ;
        RECT  15.024 0 15.048 0.192 ;
    END
  END o[131]
  PIN o[132]
    DIRECTION OUTPUT ;
    USE SIGNAL ;
    PORT
      LAYER M3 ;
        RECT  15.156 0 15.174 0.144 ;
    END
  END o[132]
  PIN o[133]
    DIRECTION OUTPUT ;
    USE SIGNAL ;
    PORT
      LAYER M5 ;
        RECT  15.216 0 15.24 0.192 ;
    END
  END o[133]
  PIN o[134]
    DIRECTION OUTPUT ;
    USE SIGNAL ;
    PORT
      LAYER M3 ;
        RECT  15.336 0 15.354 0.144 ;
    END
  END o[134]
  PIN o[135]
    DIRECTION OUTPUT ;
    USE SIGNAL ;
    PORT
      LAYER M5 ;
        RECT  15.456 0 15.48 0.192 ;
    END
  END o[135]
  PIN o[136]
    DIRECTION OUTPUT ;
    USE SIGNAL ;
    PORT
      LAYER M3 ;
        RECT  15.516 0 15.534 0.144 ;
    END
  END o[136]
  PIN o[137]
    DIRECTION OUTPUT ;
    USE SIGNAL ;
    PORT
      LAYER M5 ;
        RECT  15.648 0 15.672 0.192 ;
    END
  END o[137]
  PIN o[138]
    DIRECTION OUTPUT ;
    USE SIGNAL ;
    PORT
      LAYER M3 ;
        RECT  15.732 0 15.75 0.144 ;
    END
  END o[138]
  PIN o[139]
    DIRECTION OUTPUT ;
    USE SIGNAL ;
    PORT
      LAYER M5 ;
        RECT  15.84 0 15.864 0.192 ;
    END
  END o[139]
  PIN o[13]
    DIRECTION OUTPUT ;
    USE SIGNAL ;
    PORT
      LAYER M5 ;
        RECT  3.456 0 3.48 0.192 ;
    END
  END o[13]
  PIN o[140]
    DIRECTION OUTPUT ;
    USE SIGNAL ;
    PORT
      LAYER M3 ;
        RECT  15.912 0 15.93 0.144 ;
    END
  END o[140]
  PIN o[141]
    DIRECTION OUTPUT ;
    USE SIGNAL ;
    PORT
      LAYER M5 ;
        RECT  16.032 0 16.056 0.192 ;
    END
  END o[141]
  PIN o[142]
    DIRECTION OUTPUT ;
    USE SIGNAL ;
    PORT
      LAYER M3 ;
        RECT  16.128 0 16.146 0.144 ;
    END
  END o[142]
  PIN o[143]
    DIRECTION OUTPUT ;
    USE SIGNAL ;
    PORT
      LAYER M5 ;
        RECT  16.224 0 16.248 0.192 ;
    END
  END o[143]
  PIN o[144]
    DIRECTION OUTPUT ;
    USE SIGNAL ;
    PORT
      LAYER M3 ;
        RECT  16.308 0 16.326 0.144 ;
    END
  END o[144]
  PIN o[145]
    DIRECTION OUTPUT ;
    USE SIGNAL ;
    PORT
      LAYER M5 ;
        RECT  16.416 0 16.44 0.192 ;
    END
  END o[145]
  PIN o[146]
    DIRECTION OUTPUT ;
    USE SIGNAL ;
    PORT
      LAYER M3 ;
        RECT  16.524 0 16.542 0.144 ;
    END
  END o[146]
  PIN o[147]
    DIRECTION OUTPUT ;
    USE SIGNAL ;
    PORT
      LAYER M5 ;
        RECT  16.608 0 16.632 0.192 ;
    END
  END o[147]
  PIN o[148]
    DIRECTION OUTPUT ;
    USE SIGNAL ;
    PORT
      LAYER M3 ;
        RECT  16.704 0 16.722 0.144 ;
    END
  END o[148]
  PIN o[149]
    DIRECTION OUTPUT ;
    USE SIGNAL ;
    PORT
      LAYER M5 ;
        RECT  16.8 0 16.824 0.192 ;
    END
  END o[149]
  PIN o[14]
    DIRECTION OUTPUT ;
    USE SIGNAL ;
    PORT
      LAYER M3 ;
        RECT  3.564 0 3.582 0.144 ;
    END
  END o[14]
  PIN o[150]
    DIRECTION OUTPUT ;
    USE SIGNAL ;
    PORT
      LAYER M3 ;
        RECT  16.92 0 16.938 0.144 ;
    END
  END o[150]
  PIN o[151]
    DIRECTION OUTPUT ;
    USE SIGNAL ;
    PORT
      LAYER M5 ;
        RECT  16.992 0 17.016 0.192 ;
    END
  END o[151]
  PIN o[152]
    DIRECTION OUTPUT ;
    USE SIGNAL ;
    PORT
      LAYER M3 ;
        RECT  17.1 0 17.118 0.144 ;
    END
  END o[152]
  PIN o[153]
    DIRECTION OUTPUT ;
    USE SIGNAL ;
    PORT
      LAYER M5 ;
        RECT  17.184 0 17.208 0.192 ;
    END
  END o[153]
  PIN o[154]
    DIRECTION OUTPUT ;
    USE SIGNAL ;
    PORT
      LAYER M3 ;
        RECT  17.28 0 17.298 0.144 ;
    END
  END o[154]
  PIN o[155]
    DIRECTION OUTPUT ;
    USE SIGNAL ;
    PORT
      LAYER M5 ;
        RECT  17.376 0 17.4 0.192 ;
    END
  END o[155]
  PIN o[156]
    DIRECTION OUTPUT ;
    USE SIGNAL ;
    PORT
      LAYER M3 ;
        RECT  17.496 0 17.514 0.144 ;
    END
  END o[156]
  PIN o[157]
    DIRECTION OUTPUT ;
    USE SIGNAL ;
    PORT
      LAYER M5 ;
        RECT  17.568 0 17.592 0.192 ;
    END
  END o[157]
  PIN o[158]
    DIRECTION OUTPUT ;
    USE SIGNAL ;
    PORT
      LAYER M3 ;
        RECT  17.676 0 17.694 0.144 ;
    END
  END o[158]
  PIN o[159]
    DIRECTION OUTPUT ;
    USE SIGNAL ;
    PORT
      LAYER M5 ;
        RECT  17.808 0 17.832 0.192 ;
    END
  END o[159]
  PIN o[15]
    DIRECTION OUTPUT ;
    USE SIGNAL ;
    PORT
      LAYER M5 ;
        RECT  3.648 0 3.672 0.192 ;
    END
  END o[15]
  PIN o[160]
    DIRECTION OUTPUT ;
    USE SIGNAL ;
    PORT
      LAYER M3 ;
        RECT  17.892 0 17.91 0.144 ;
    END
  END o[160]
  PIN o[161]
    DIRECTION OUTPUT ;
    USE SIGNAL ;
    PORT
      LAYER M5 ;
        RECT  18 0 18.024 0.192 ;
    END
  END o[161]
  PIN o[162]
    DIRECTION OUTPUT ;
    USE SIGNAL ;
    PORT
      LAYER M3 ;
        RECT  18.072 0 18.09 0.144 ;
    END
  END o[162]
  PIN o[163]
    DIRECTION OUTPUT ;
    USE SIGNAL ;
    PORT
      LAYER M5 ;
        RECT  18.192 0 18.216 0.192 ;
    END
  END o[163]
  PIN o[164]
    DIRECTION OUTPUT ;
    USE SIGNAL ;
    PORT
      LAYER M3 ;
        RECT  18.288 0 18.306 0.144 ;
    END
  END o[164]
  PIN o[165]
    DIRECTION OUTPUT ;
    USE SIGNAL ;
    PORT
      LAYER M5 ;
        RECT  18.384 0 18.408 0.192 ;
    END
  END o[165]
  PIN o[166]
    DIRECTION OUTPUT ;
    USE SIGNAL ;
    PORT
      LAYER M3 ;
        RECT  18.468 0 18.486 0.144 ;
    END
  END o[166]
  PIN o[167]
    DIRECTION OUTPUT ;
    USE SIGNAL ;
    PORT
      LAYER M5 ;
        RECT  18.576 0 18.6 0.192 ;
    END
  END o[167]
  PIN o[168]
    DIRECTION OUTPUT ;
    USE SIGNAL ;
    PORT
      LAYER M3 ;
        RECT  18.684 0 18.702 0.144 ;
    END
  END o[168]
  PIN o[169]
    DIRECTION OUTPUT ;
    USE SIGNAL ;
    PORT
      LAYER M5 ;
        RECT  18.768 0 18.792 0.192 ;
    END
  END o[169]
  PIN o[16]
    DIRECTION OUTPUT ;
    USE SIGNAL ;
    PORT
      LAYER M3 ;
        RECT  3.78 0 3.798 0.144 ;
    END
  END o[16]
  PIN o[170]
    DIRECTION OUTPUT ;
    USE SIGNAL ;
    PORT
      LAYER M3 ;
        RECT  18.864 0 18.882 0.144 ;
    END
  END o[170]
  PIN o[171]
    DIRECTION OUTPUT ;
    USE SIGNAL ;
    PORT
      LAYER M5 ;
        RECT  18.96 0 18.984 0.192 ;
    END
  END o[171]
  PIN o[172]
    DIRECTION OUTPUT ;
    USE SIGNAL ;
    PORT
      LAYER M3 ;
        RECT  19.08 0 19.098 0.144 ;
    END
  END o[172]
  PIN o[173]
    DIRECTION OUTPUT ;
    USE SIGNAL ;
    PORT
      LAYER M5 ;
        RECT  19.152 0 19.176 0.192 ;
    END
  END o[173]
  PIN o[174]
    DIRECTION OUTPUT ;
    USE SIGNAL ;
    PORT
      LAYER M3 ;
        RECT  19.26 0 19.278 0.144 ;
    END
  END o[174]
  PIN o[175]
    DIRECTION OUTPUT ;
    USE SIGNAL ;
    PORT
      LAYER M5 ;
        RECT  19.344 0 19.368 0.192 ;
    END
  END o[175]
  PIN o[176]
    DIRECTION OUTPUT ;
    USE SIGNAL ;
    PORT
      LAYER M3 ;
        RECT  19.44 0 19.458 0.144 ;
    END
  END o[176]
  PIN o[177]
    DIRECTION OUTPUT ;
    USE SIGNAL ;
    PORT
      LAYER M5 ;
        RECT  19.536 0 19.56 0.192 ;
    END
  END o[177]
  PIN o[178]
    DIRECTION OUTPUT ;
    USE SIGNAL ;
    PORT
      LAYER M3 ;
        RECT  19.656 0 19.674 0.144 ;
    END
  END o[178]
  PIN o[179]
    DIRECTION OUTPUT ;
    USE SIGNAL ;
    PORT
      LAYER M5 ;
        RECT  19.728 0 19.752 0.192 ;
    END
  END o[179]
  PIN o[17]
    DIRECTION OUTPUT ;
    USE SIGNAL ;
    PORT
      LAYER M5 ;
        RECT  3.84 0 3.864 0.192 ;
    END
  END o[17]
  PIN o[180]
    DIRECTION OUTPUT ;
    USE SIGNAL ;
    PORT
      LAYER M3 ;
        RECT  19.836 0 19.854 0.144 ;
    END
  END o[180]
  PIN o[181]
    DIRECTION OUTPUT ;
    USE SIGNAL ;
    PORT
      LAYER M5 ;
        RECT  19.92 0 19.944 0.192 ;
    END
  END o[181]
  PIN o[182]
    DIRECTION OUTPUT ;
    USE SIGNAL ;
    PORT
      LAYER M3 ;
        RECT  20.052 0 20.07 0.144 ;
    END
  END o[182]
  PIN o[183]
    DIRECTION OUTPUT ;
    USE SIGNAL ;
    PORT
      LAYER M5 ;
        RECT  20.16 0 20.184 0.192 ;
    END
  END o[183]
  PIN o[184]
    DIRECTION OUTPUT ;
    USE SIGNAL ;
    PORT
      LAYER M3 ;
        RECT  20.232 0 20.25 0.144 ;
    END
  END o[184]
  PIN o[185]
    DIRECTION OUTPUT ;
    USE SIGNAL ;
    PORT
      LAYER M5 ;
        RECT  20.352 0 20.376 0.192 ;
    END
  END o[185]
  PIN o[186]
    DIRECTION OUTPUT ;
    USE SIGNAL ;
    PORT
      LAYER M3 ;
        RECT  20.448 0 20.466 0.144 ;
    END
  END o[186]
  PIN o[187]
    DIRECTION OUTPUT ;
    USE SIGNAL ;
    PORT
      LAYER M5 ;
        RECT  20.544 0 20.568 0.192 ;
    END
  END o[187]
  PIN o[188]
    DIRECTION OUTPUT ;
    USE SIGNAL ;
    PORT
      LAYER M3 ;
        RECT  20.628 0 20.646 0.144 ;
    END
  END o[188]
  PIN o[189]
    DIRECTION OUTPUT ;
    USE SIGNAL ;
    PORT
      LAYER M5 ;
        RECT  20.736 0 20.76 0.192 ;
    END
  END o[189]
  PIN o[18]
    DIRECTION OUTPUT ;
    USE SIGNAL ;
    PORT
      LAYER M3 ;
        RECT  3.96 0 3.978 0.144 ;
    END
  END o[18]
  PIN o[190]
    DIRECTION OUTPUT ;
    USE SIGNAL ;
    PORT
      LAYER M3 ;
        RECT  20.844 0 20.862 0.144 ;
    END
  END o[190]
  PIN o[191]
    DIRECTION OUTPUT ;
    USE SIGNAL ;
    PORT
      LAYER M5 ;
        RECT  20.928 0 20.952 0.192 ;
    END
  END o[191]
  PIN o[192]
    DIRECTION OUTPUT ;
    USE SIGNAL ;
    PORT
      LAYER M3 ;
        RECT  21.024 0 21.042 0.144 ;
    END
  END o[192]
  PIN o[193]
    DIRECTION OUTPUT ;
    USE SIGNAL ;
    PORT
      LAYER M5 ;
        RECT  21.12 0 21.144 0.192 ;
    END
  END o[193]
  PIN o[194]
    DIRECTION OUTPUT ;
    USE SIGNAL ;
    PORT
      LAYER M3 ;
        RECT  21.204 0 21.222 0.144 ;
    END
  END o[194]
  PIN o[195]
    DIRECTION OUTPUT ;
    USE SIGNAL ;
    PORT
      LAYER M5 ;
        RECT  21.312 0 21.336 0.192 ;
    END
  END o[195]
  PIN o[196]
    DIRECTION OUTPUT ;
    USE SIGNAL ;
    PORT
      LAYER M3 ;
        RECT  21.42 0 21.438 0.144 ;
    END
  END o[196]
  PIN o[197]
    DIRECTION OUTPUT ;
    USE SIGNAL ;
    PORT
      LAYER M5 ;
        RECT  21.504 0 21.528 0.192 ;
    END
  END o[197]
  PIN o[198]
    DIRECTION OUTPUT ;
    USE SIGNAL ;
    PORT
      LAYER M3 ;
        RECT  21.6 0 21.618 0.144 ;
    END
  END o[198]
  PIN o[199]
    DIRECTION OUTPUT ;
    USE SIGNAL ;
    PORT
      LAYER M5 ;
        RECT  21.696 0 21.72 0.192 ;
    END
  END o[199]
  PIN o[19]
    DIRECTION OUTPUT ;
    USE SIGNAL ;
    PORT
      LAYER M5 ;
        RECT  4.08 0 4.104 0.192 ;
    END
  END o[19]
  PIN o[1]
    DIRECTION OUTPUT ;
    USE SIGNAL ;
    PORT
      LAYER M5 ;
        RECT  2.304 0 2.328 0.192 ;
    END
  END o[1]
  PIN o[200]
    DIRECTION OUTPUT ;
    USE SIGNAL ;
    PORT
      LAYER M3 ;
        RECT  21.816 0 21.834 0.144 ;
    END
  END o[200]
  PIN o[201]
    DIRECTION OUTPUT ;
    USE SIGNAL ;
    PORT
      LAYER M5 ;
        RECT  21.888 0 21.912 0.192 ;
    END
  END o[201]
  PIN o[202]
    DIRECTION OUTPUT ;
    USE SIGNAL ;
    PORT
      LAYER M3 ;
        RECT  21.996 0 22.014 0.144 ;
    END
  END o[202]
  PIN o[203]
    DIRECTION OUTPUT ;
    USE SIGNAL ;
    PORT
      LAYER M5 ;
        RECT  22.08 0 22.104 0.192 ;
    END
  END o[203]
  PIN o[204]
    DIRECTION OUTPUT ;
    USE SIGNAL ;
    PORT
      LAYER M3 ;
        RECT  22.212 0 22.23 0.144 ;
    END
  END o[204]
  PIN o[205]
    DIRECTION OUTPUT ;
    USE SIGNAL ;
    PORT
      LAYER M5 ;
        RECT  22.272 0 22.296 0.192 ;
    END
  END o[205]
  PIN o[206]
    DIRECTION OUTPUT ;
    USE SIGNAL ;
    PORT
      LAYER M3 ;
        RECT  22.392 0 22.41 0.144 ;
    END
  END o[206]
  PIN o[207]
    DIRECTION OUTPUT ;
    USE SIGNAL ;
    PORT
      LAYER M5 ;
        RECT  22.512 0 22.536 0.192 ;
    END
  END o[207]
  PIN o[208]
    DIRECTION OUTPUT ;
    USE SIGNAL ;
    PORT
      LAYER M3 ;
        RECT  22.608 0 22.626 0.144 ;
    END
  END o[208]
  PIN o[209]
    DIRECTION OUTPUT ;
    USE SIGNAL ;
    PORT
      LAYER M5 ;
        RECT  22.704 0 22.728 0.192 ;
    END
  END o[209]
  PIN o[20]
    DIRECTION OUTPUT ;
    USE SIGNAL ;
    PORT
      LAYER M3 ;
        RECT  4.176 0 4.194 0.144 ;
    END
  END o[20]
  PIN o[210]
    DIRECTION OUTPUT ;
    USE SIGNAL ;
    PORT
      LAYER M3 ;
        RECT  22.788 0 22.806 0.144 ;
    END
  END o[210]
  PIN o[211]
    DIRECTION OUTPUT ;
    USE SIGNAL ;
    PORT
      LAYER M5 ;
        RECT  22.896 0 22.92 0.192 ;
    END
  END o[211]
  PIN o[212]
    DIRECTION OUTPUT ;
    USE SIGNAL ;
    PORT
      LAYER M3 ;
        RECT  22.968 0 22.986 0.144 ;
    END
  END o[212]
  PIN o[213]
    DIRECTION OUTPUT ;
    USE SIGNAL ;
    PORT
      LAYER M5 ;
        RECT  23.088 0 23.112 0.192 ;
    END
  END o[213]
  PIN o[214]
    DIRECTION OUTPUT ;
    USE SIGNAL ;
    PORT
      LAYER M3 ;
        RECT  23.184 0 23.202 0.144 ;
    END
  END o[214]
  PIN o[215]
    DIRECTION OUTPUT ;
    USE SIGNAL ;
    PORT
      LAYER M5 ;
        RECT  23.28 0 23.304 0.192 ;
    END
  END o[215]
  PIN o[216]
    DIRECTION OUTPUT ;
    USE SIGNAL ;
    PORT
      LAYER M3 ;
        RECT  23.364 0 23.382 0.144 ;
    END
  END o[216]
  PIN o[217]
    DIRECTION OUTPUT ;
    USE SIGNAL ;
    PORT
      LAYER M5 ;
        RECT  23.472 0 23.496 0.192 ;
    END
  END o[217]
  PIN o[218]
    DIRECTION OUTPUT ;
    USE SIGNAL ;
    PORT
      LAYER M3 ;
        RECT  23.58 0 23.598 0.144 ;
    END
  END o[218]
  PIN o[219]
    DIRECTION OUTPUT ;
    USE SIGNAL ;
    PORT
      LAYER M5 ;
        RECT  23.664 0 23.688 0.192 ;
    END
  END o[219]
  PIN o[21]
    DIRECTION OUTPUT ;
    USE SIGNAL ;
    PORT
      LAYER M5 ;
        RECT  4.272 0 4.296 0.192 ;
    END
  END o[21]
  PIN o[220]
    DIRECTION OUTPUT ;
    USE SIGNAL ;
    PORT
      LAYER M3 ;
        RECT  23.76 0 23.778 0.144 ;
    END
  END o[220]
  PIN o[221]
    DIRECTION OUTPUT ;
    USE SIGNAL ;
    PORT
      LAYER M5 ;
        RECT  23.856 0 23.88 0.192 ;
    END
  END o[221]
  PIN o[222]
    DIRECTION OUTPUT ;
    USE SIGNAL ;
    PORT
      LAYER M3 ;
        RECT  23.976 0 23.994 0.144 ;
    END
  END o[222]
  PIN o[223]
    DIRECTION OUTPUT ;
    USE SIGNAL ;
    PORT
      LAYER M5 ;
        RECT  24.048 0 24.072 0.192 ;
    END
  END o[223]
  PIN o[224]
    DIRECTION OUTPUT ;
    USE SIGNAL ;
    PORT
      LAYER M3 ;
        RECT  24.156 0 24.174 0.144 ;
    END
  END o[224]
  PIN o[225]
    DIRECTION OUTPUT ;
    USE SIGNAL ;
    PORT
      LAYER M5 ;
        RECT  24.24 0 24.264 0.192 ;
    END
  END o[225]
  PIN o[226]
    DIRECTION OUTPUT ;
    USE SIGNAL ;
    PORT
      LAYER M3 ;
        RECT  24.372 0 24.39 0.144 ;
    END
  END o[226]
  PIN o[227]
    DIRECTION OUTPUT ;
    USE SIGNAL ;
    PORT
      LAYER M5 ;
        RECT  24.432 0 24.456 0.192 ;
    END
  END o[227]
  PIN o[228]
    DIRECTION OUTPUT ;
    USE SIGNAL ;
    PORT
      LAYER M3 ;
        RECT  24.552 0 24.57 0.144 ;
    END
  END o[228]
  PIN o[229]
    DIRECTION OUTPUT ;
    USE SIGNAL ;
    PORT
      LAYER M5 ;
        RECT  24.624 0 24.648 0.192 ;
    END
  END o[229]
  PIN o[22]
    DIRECTION OUTPUT ;
    USE SIGNAL ;
    PORT
      LAYER M3 ;
        RECT  4.356 0 4.374 0.144 ;
    END
  END o[22]
  PIN o[230]
    DIRECTION OUTPUT ;
    USE SIGNAL ;
    PORT
      LAYER M3 ;
        RECT  24.732 0 24.75 0.144 ;
    END
  END o[230]
  PIN o[231]
    DIRECTION OUTPUT ;
    USE SIGNAL ;
    PORT
      LAYER M5 ;
        RECT  24.864 0 24.888 0.192 ;
    END
  END o[231]
  PIN o[232]
    DIRECTION OUTPUT ;
    USE SIGNAL ;
    PORT
      LAYER M3 ;
        RECT  24.948 0 24.966 0.144 ;
    END
  END o[232]
  PIN o[233]
    DIRECTION OUTPUT ;
    USE SIGNAL ;
    PORT
      LAYER M5 ;
        RECT  25.056 0 25.08 0.192 ;
    END
  END o[233]
  PIN o[234]
    DIRECTION OUTPUT ;
    USE SIGNAL ;
    PORT
      LAYER M3 ;
        RECT  25.128 0 25.146 0.144 ;
    END
  END o[234]
  PIN o[235]
    DIRECTION OUTPUT ;
    USE SIGNAL ;
    PORT
      LAYER M5 ;
        RECT  25.248 0 25.272 0.192 ;
    END
  END o[235]
  PIN o[236]
    DIRECTION OUTPUT ;
    USE SIGNAL ;
    PORT
      LAYER M3 ;
        RECT  25.344 0 25.362 0.144 ;
    END
  END o[236]
  PIN o[237]
    DIRECTION OUTPUT ;
    USE SIGNAL ;
    PORT
      LAYER M5 ;
        RECT  25.44 0 25.464 0.192 ;
    END
  END o[237]
  PIN o[238]
    DIRECTION OUTPUT ;
    USE SIGNAL ;
    PORT
      LAYER M3 ;
        RECT  25.524 0 25.542 0.144 ;
    END
  END o[238]
  PIN o[239]
    DIRECTION OUTPUT ;
    USE SIGNAL ;
    PORT
      LAYER M5 ;
        RECT  25.632 0 25.656 0.192 ;
    END
  END o[239]
  PIN o[23]
    DIRECTION OUTPUT ;
    USE SIGNAL ;
    PORT
      LAYER M5 ;
        RECT  4.464 0 4.488 0.192 ;
    END
  END o[23]
  PIN o[240]
    DIRECTION OUTPUT ;
    USE SIGNAL ;
    PORT
      LAYER M3 ;
        RECT  25.74 0 25.758 0.144 ;
    END
  END o[240]
  PIN o[241]
    DIRECTION OUTPUT ;
    USE SIGNAL ;
    PORT
      LAYER M5 ;
        RECT  25.824 0 25.848 0.192 ;
    END
  END o[241]
  PIN o[242]
    DIRECTION OUTPUT ;
    USE SIGNAL ;
    PORT
      LAYER M3 ;
        RECT  25.92 0 25.938 0.144 ;
    END
  END o[242]
  PIN o[243]
    DIRECTION OUTPUT ;
    USE SIGNAL ;
    PORT
      LAYER M5 ;
        RECT  26.016 0 26.04 0.192 ;
    END
  END o[243]
  PIN o[244]
    DIRECTION OUTPUT ;
    USE SIGNAL ;
    PORT
      LAYER M3 ;
        RECT  26.136 0 26.154 0.144 ;
    END
  END o[244]
  PIN o[245]
    DIRECTION OUTPUT ;
    USE SIGNAL ;
    PORT
      LAYER M5 ;
        RECT  26.208 0 26.232 0.192 ;
    END
  END o[245]
  PIN o[246]
    DIRECTION OUTPUT ;
    USE SIGNAL ;
    PORT
      LAYER M3 ;
        RECT  26.316 0 26.334 0.144 ;
    END
  END o[246]
  PIN o[247]
    DIRECTION OUTPUT ;
    USE SIGNAL ;
    PORT
      LAYER M5 ;
        RECT  26.4 0 26.424 0.192 ;
    END
  END o[247]
  PIN o[248]
    DIRECTION OUTPUT ;
    USE SIGNAL ;
    PORT
      LAYER M3 ;
        RECT  26.496 0 26.514 0.144 ;
    END
  END o[248]
  PIN o[249]
    DIRECTION OUTPUT ;
    USE SIGNAL ;
    PORT
      LAYER M5 ;
        RECT  26.592 0 26.616 0.192 ;
    END
  END o[249]
  PIN o[24]
    DIRECTION OUTPUT ;
    USE SIGNAL ;
    PORT
      LAYER M3 ;
        RECT  4.536 0 4.554 0.144 ;
    END
  END o[24]
  PIN o[250]
    DIRECTION OUTPUT ;
    USE SIGNAL ;
    PORT
      LAYER M3 ;
        RECT  26.712 0 26.73 0.144 ;
    END
  END o[250]
  PIN o[251]
    DIRECTION OUTPUT ;
    USE SIGNAL ;
    PORT
      LAYER M5 ;
        RECT  26.784 0 26.808 0.192 ;
    END
  END o[251]
  PIN o[252]
    DIRECTION OUTPUT ;
    USE SIGNAL ;
    PORT
      LAYER M3 ;
        RECT  26.892 0 26.91 0.144 ;
    END
  END o[252]
  PIN o[253]
    DIRECTION OUTPUT ;
    USE SIGNAL ;
    PORT
      LAYER M5 ;
        RECT  27.024 0 27.048 0.192 ;
    END
  END o[253]
  PIN o[254]
    DIRECTION OUTPUT ;
    USE SIGNAL ;
    PORT
      LAYER M3 ;
        RECT  27.108 0 27.126 0.144 ;
    END
  END o[254]
  PIN o[255]
    DIRECTION OUTPUT ;
    USE SIGNAL ;
    PORT
      LAYER M5 ;
        RECT  27.216 0 27.24 0.192 ;
    END
  END o[255]
  PIN o[256]
    DIRECTION OUTPUT ;
    USE SIGNAL ;
    PORT
      LAYER M3 ;
        RECT  27.288 0 27.306 0.144 ;
    END
  END o[256]
  PIN o[257]
    DIRECTION OUTPUT ;
    USE SIGNAL ;
    PORT
      LAYER M5 ;
        RECT  27.408 0 27.432 0.192 ;
    END
  END o[257]
  PIN o[258]
    DIRECTION OUTPUT ;
    USE SIGNAL ;
    PORT
      LAYER M3 ;
        RECT  27.504 0 27.522 0.144 ;
    END
  END o[258]
  PIN o[259]
    DIRECTION OUTPUT ;
    USE SIGNAL ;
    PORT
      LAYER M5 ;
        RECT  27.6 0 27.624 0.192 ;
    END
  END o[259]
  PIN o[25]
    DIRECTION OUTPUT ;
    USE SIGNAL ;
    PORT
      LAYER M5 ;
        RECT  4.656 0 4.68 0.192 ;
    END
  END o[25]
  PIN o[260]
    DIRECTION OUTPUT ;
    USE SIGNAL ;
    PORT
      LAYER M3 ;
        RECT  27.684 0 27.702 0.144 ;
    END
  END o[260]
  PIN o[261]
    DIRECTION OUTPUT ;
    USE SIGNAL ;
    PORT
      LAYER M5 ;
        RECT  27.792 0 27.816 0.192 ;
    END
  END o[261]
  PIN o[262]
    DIRECTION OUTPUT ;
    USE SIGNAL ;
    PORT
      LAYER M3 ;
        RECT  27.9 0 27.918 0.144 ;
    END
  END o[262]
  PIN o[263]
    DIRECTION OUTPUT ;
    USE SIGNAL ;
    PORT
      LAYER M5 ;
        RECT  27.984 0 28.008 0.192 ;
    END
  END o[263]
  PIN o[264]
    DIRECTION OUTPUT ;
    USE SIGNAL ;
    PORT
      LAYER M3 ;
        RECT  28.08 0 28.098 0.144 ;
    END
  END o[264]
  PIN o[265]
    DIRECTION OUTPUT ;
    USE SIGNAL ;
    PORT
      LAYER M5 ;
        RECT  28.176 0 28.2 0.192 ;
    END
  END o[265]
  PIN o[266]
    DIRECTION OUTPUT ;
    USE SIGNAL ;
    PORT
      LAYER M3 ;
        RECT  28.296 0 28.314 0.144 ;
    END
  END o[266]
  PIN o[267]
    DIRECTION OUTPUT ;
    USE SIGNAL ;
    PORT
      LAYER M5 ;
        RECT  28.368 0 28.392 0.192 ;
    END
  END o[267]
  PIN o[268]
    DIRECTION OUTPUT ;
    USE SIGNAL ;
    PORT
      LAYER M3 ;
        RECT  28.476 0 28.494 0.144 ;
    END
  END o[268]
  PIN o[269]
    DIRECTION OUTPUT ;
    USE SIGNAL ;
    PORT
      LAYER M5 ;
        RECT  28.56 0 28.584 0.192 ;
    END
  END o[269]
  PIN o[26]
    DIRECTION OUTPUT ;
    USE SIGNAL ;
    PORT
      LAYER M3 ;
        RECT  4.752 0 4.77 0.144 ;
    END
  END o[26]
  PIN o[270]
    DIRECTION OUTPUT ;
    USE SIGNAL ;
    PORT
      LAYER M3 ;
        RECT  28.656 0 28.674 0.144 ;
    END
  END o[270]
  PIN o[271]
    DIRECTION OUTPUT ;
    USE SIGNAL ;
    PORT
      LAYER M5 ;
        RECT  28.752 0 28.776 0.192 ;
    END
  END o[271]
  PIN o[272]
    DIRECTION OUTPUT ;
    USE SIGNAL ;
    PORT
      LAYER M3 ;
        RECT  28.872 0 28.89 0.144 ;
    END
  END o[272]
  PIN o[273]
    DIRECTION OUTPUT ;
    USE SIGNAL ;
    PORT
      LAYER M5 ;
        RECT  28.944 0 28.968 0.192 ;
    END
  END o[273]
  PIN o[274]
    DIRECTION OUTPUT ;
    USE SIGNAL ;
    PORT
      LAYER M3 ;
        RECT  29.052 0 29.07 0.144 ;
    END
  END o[274]
  PIN o[275]
    DIRECTION OUTPUT ;
    USE SIGNAL ;
    PORT
      LAYER M5 ;
        RECT  29.136 0 29.16 0.192 ;
    END
  END o[275]
  PIN o[276]
    DIRECTION OUTPUT ;
    USE SIGNAL ;
    PORT
      LAYER M3 ;
        RECT  29.268 0 29.286 0.144 ;
    END
  END o[276]
  PIN o[277]
    DIRECTION OUTPUT ;
    USE SIGNAL ;
    PORT
      LAYER M5 ;
        RECT  29.376 0 29.4 0.192 ;
    END
  END o[277]
  PIN o[278]
    DIRECTION OUTPUT ;
    USE SIGNAL ;
    PORT
      LAYER M3 ;
        RECT  29.448 0 29.466 0.144 ;
    END
  END o[278]
  PIN o[279]
    DIRECTION OUTPUT ;
    USE SIGNAL ;
    PORT
      LAYER M5 ;
        RECT  29.568 0 29.592 0.192 ;
    END
  END o[279]
  PIN o[27]
    DIRECTION OUTPUT ;
    USE SIGNAL ;
    PORT
      LAYER M5 ;
        RECT  4.848 0 4.872 0.192 ;
    END
  END o[27]
  PIN o[280]
    DIRECTION OUTPUT ;
    USE SIGNAL ;
    PORT
      LAYER M3 ;
        RECT  29.664 0 29.682 0.144 ;
    END
  END o[280]
  PIN o[281]
    DIRECTION OUTPUT ;
    USE SIGNAL ;
    PORT
      LAYER M5 ;
        RECT  29.76 0 29.784 0.192 ;
    END
  END o[281]
  PIN o[282]
    DIRECTION OUTPUT ;
    USE SIGNAL ;
    PORT
      LAYER M3 ;
        RECT  29.844 0 29.862 0.144 ;
    END
  END o[282]
  PIN o[283]
    DIRECTION OUTPUT ;
    USE SIGNAL ;
    PORT
      LAYER M5 ;
        RECT  29.952 0 29.976 0.192 ;
    END
  END o[283]
  PIN o[284]
    DIRECTION OUTPUT ;
    USE SIGNAL ;
    PORT
      LAYER M3 ;
        RECT  30.06 0 30.078 0.144 ;
    END
  END o[284]
  PIN o[285]
    DIRECTION OUTPUT ;
    USE SIGNAL ;
    PORT
      LAYER M5 ;
        RECT  30.144 0 30.168 0.192 ;
    END
  END o[285]
  PIN o[286]
    DIRECTION OUTPUT ;
    USE SIGNAL ;
    PORT
      LAYER M3 ;
        RECT  30.24 0 30.258 0.144 ;
    END
  END o[286]
  PIN o[287]
    DIRECTION OUTPUT ;
    USE SIGNAL ;
    PORT
      LAYER M5 ;
        RECT  30.336 0 30.36 0.192 ;
    END
  END o[287]
  PIN o[288]
    DIRECTION OUTPUT ;
    USE SIGNAL ;
    PORT
      LAYER M3 ;
        RECT  30.42 0 30.438 0.144 ;
    END
  END o[288]
  PIN o[289]
    DIRECTION OUTPUT ;
    USE SIGNAL ;
    PORT
      LAYER M5 ;
        RECT  30.528 0 30.552 0.192 ;
    END
  END o[289]
  PIN o[28]
    DIRECTION OUTPUT ;
    USE SIGNAL ;
    PORT
      LAYER M3 ;
        RECT  4.932 0 4.95 0.144 ;
    END
  END o[28]
  PIN o[290]
    DIRECTION OUTPUT ;
    USE SIGNAL ;
    PORT
      LAYER M3 ;
        RECT  30.636 0 30.654 0.144 ;
    END
  END o[290]
  PIN o[291]
    DIRECTION OUTPUT ;
    USE SIGNAL ;
    PORT
      LAYER M5 ;
        RECT  30.72 0 30.744 0.192 ;
    END
  END o[291]
  PIN o[292]
    DIRECTION OUTPUT ;
    USE SIGNAL ;
    PORT
      LAYER M3 ;
        RECT  30.816 0 30.834 0.144 ;
    END
  END o[292]
  PIN o[293]
    DIRECTION OUTPUT ;
    USE SIGNAL ;
    PORT
      LAYER M5 ;
        RECT  30.912 0 30.936 0.192 ;
    END
  END o[293]
  PIN o[294]
    DIRECTION OUTPUT ;
    USE SIGNAL ;
    PORT
      LAYER M3 ;
        RECT  31.032 0 31.05 0.144 ;
    END
  END o[294]
  PIN o[295]
    DIRECTION OUTPUT ;
    USE SIGNAL ;
    PORT
      LAYER M5 ;
        RECT  31.104 0 31.128 0.192 ;
    END
  END o[295]
  PIN o[296]
    DIRECTION OUTPUT ;
    USE SIGNAL ;
    PORT
      LAYER M3 ;
        RECT  31.212 0 31.23 0.144 ;
    END
  END o[296]
  PIN o[297]
    DIRECTION OUTPUT ;
    USE SIGNAL ;
    PORT
      LAYER M5 ;
        RECT  31.296 0 31.32 0.192 ;
    END
  END o[297]
  PIN o[298]
    DIRECTION OUTPUT ;
    USE SIGNAL ;
    PORT
      LAYER M3 ;
        RECT  31.428 0 31.446 0.144 ;
    END
  END o[298]
  PIN o[299]
    DIRECTION OUTPUT ;
    USE SIGNAL ;
    PORT
      LAYER M5 ;
        RECT  31.488 0 31.512 0.192 ;
    END
  END o[299]
  PIN o[29]
    DIRECTION OUTPUT ;
    USE SIGNAL ;
    PORT
      LAYER M5 ;
        RECT  5.04 0 5.064 0.192 ;
    END
  END o[29]
  PIN o[2]
    DIRECTION OUTPUT ;
    USE SIGNAL ;
    PORT
      LAYER M3 ;
        RECT  2.412 0 2.43 0.144 ;
    END
  END o[2]
  PIN o[300]
    DIRECTION OUTPUT ;
    USE SIGNAL ;
    PORT
      LAYER M3 ;
        RECT  31.608 0 31.626 0.144 ;
    END
  END o[300]
  PIN o[301]
    DIRECTION OUTPUT ;
    USE SIGNAL ;
    PORT
      LAYER M5 ;
        RECT  31.728 0 31.752 0.192 ;
    END
  END o[301]
  PIN o[302]
    DIRECTION OUTPUT ;
    USE SIGNAL ;
    PORT
      LAYER M3 ;
        RECT  31.824 0 31.842 0.144 ;
    END
  END o[302]
  PIN o[303]
    DIRECTION OUTPUT ;
    USE SIGNAL ;
    PORT
      LAYER M5 ;
        RECT  31.92 0 31.944 0.192 ;
    END
  END o[303]
  PIN o[304]
    DIRECTION OUTPUT ;
    USE SIGNAL ;
    PORT
      LAYER M3 ;
        RECT  32.004 0 32.022 0.144 ;
    END
  END o[304]
  PIN o[305]
    DIRECTION OUTPUT ;
    USE SIGNAL ;
    PORT
      LAYER M5 ;
        RECT  32.112 0 32.136 0.192 ;
    END
  END o[305]
  PIN o[306]
    DIRECTION OUTPUT ;
    USE SIGNAL ;
    PORT
      LAYER M3 ;
        RECT  32.184 0 32.202 0.144 ;
    END
  END o[306]
  PIN o[307]
    DIRECTION OUTPUT ;
    USE SIGNAL ;
    PORT
      LAYER M5 ;
        RECT  32.304 0 32.328 0.192 ;
    END
  END o[307]
  PIN o[308]
    DIRECTION OUTPUT ;
    USE SIGNAL ;
    PORT
      LAYER M3 ;
        RECT  32.4 0 32.418 0.144 ;
    END
  END o[308]
  PIN o[309]
    DIRECTION OUTPUT ;
    USE SIGNAL ;
    PORT
      LAYER M5 ;
        RECT  32.496 0 32.52 0.192 ;
    END
  END o[309]
  PIN o[30]
    DIRECTION OUTPUT ;
    USE SIGNAL ;
    PORT
      LAYER M3 ;
        RECT  5.148 0 5.166 0.144 ;
    END
  END o[30]
  PIN o[310]
    DIRECTION OUTPUT ;
    USE SIGNAL ;
    PORT
      LAYER M3 ;
        RECT  32.58 0 32.598 0.144 ;
    END
  END o[310]
  PIN o[311]
    DIRECTION OUTPUT ;
    USE SIGNAL ;
    PORT
      LAYER M5 ;
        RECT  32.688 0 32.712 0.192 ;
    END
  END o[311]
  PIN o[312]
    DIRECTION OUTPUT ;
    USE SIGNAL ;
    PORT
      LAYER M3 ;
        RECT  32.796 0 32.814 0.144 ;
    END
  END o[312]
  PIN o[313]
    DIRECTION OUTPUT ;
    USE SIGNAL ;
    PORT
      LAYER M5 ;
        RECT  32.88 0 32.904 0.192 ;
    END
  END o[313]
  PIN o[314]
    DIRECTION OUTPUT ;
    USE SIGNAL ;
    PORT
      LAYER M3 ;
        RECT  32.976 0 32.994 0.144 ;
    END
  END o[314]
  PIN o[315]
    DIRECTION OUTPUT ;
    USE SIGNAL ;
    PORT
      LAYER M5 ;
        RECT  33.072 0 33.096 0.192 ;
    END
  END o[315]
  PIN o[316]
    DIRECTION OUTPUT ;
    USE SIGNAL ;
    PORT
      LAYER M3 ;
        RECT  33.192 0 33.21 0.144 ;
    END
  END o[316]
  PIN o[317]
    DIRECTION OUTPUT ;
    USE SIGNAL ;
    PORT
      LAYER M5 ;
        RECT  33.264 0 33.288 0.192 ;
    END
  END o[317]
  PIN o[318]
    DIRECTION OUTPUT ;
    USE SIGNAL ;
    PORT
      LAYER M3 ;
        RECT  33.372 0 33.39 0.144 ;
    END
  END o[318]
  PIN o[319]
    DIRECTION OUTPUT ;
    USE SIGNAL ;
    PORT
      LAYER M5 ;
        RECT  33.456 0 33.48 0.192 ;
    END
  END o[319]
  PIN o[31]
    DIRECTION OUTPUT ;
    USE SIGNAL ;
    PORT
      LAYER M5 ;
        RECT  5.232 0 5.256 0.192 ;
    END
  END o[31]
  PIN o[320]
    DIRECTION OUTPUT ;
    USE SIGNAL ;
    PORT
      LAYER M3 ;
        RECT  33.588 0 33.606 0.144 ;
    END
  END o[320]
  PIN o[321]
    DIRECTION OUTPUT ;
    USE SIGNAL ;
    PORT
      LAYER M5 ;
        RECT  33.648 0 33.672 0.192 ;
    END
  END o[321]
  PIN o[322]
    DIRECTION OUTPUT ;
    USE SIGNAL ;
    PORT
      LAYER M3 ;
        RECT  33.768 0 33.786 0.144 ;
    END
  END o[322]
  PIN o[323]
    DIRECTION OUTPUT ;
    USE SIGNAL ;
    PORT
      LAYER M5 ;
        RECT  33.84 0 33.864 0.192 ;
    END
  END o[323]
  PIN o[324]
    DIRECTION OUTPUT ;
    USE SIGNAL ;
    PORT
      LAYER M3 ;
        RECT  33.948 0 33.966 0.144 ;
    END
  END o[324]
  PIN o[325]
    DIRECTION OUTPUT ;
    USE SIGNAL ;
    PORT
      LAYER M5 ;
        RECT  34.08 0 34.104 0.192 ;
    END
  END o[325]
  PIN o[326]
    DIRECTION OUTPUT ;
    USE SIGNAL ;
    PORT
      LAYER M3 ;
        RECT  34.164 0 34.182 0.144 ;
    END
  END o[326]
  PIN o[327]
    DIRECTION OUTPUT ;
    USE SIGNAL ;
    PORT
      LAYER M5 ;
        RECT  34.272 0 34.296 0.192 ;
    END
  END o[327]
  PIN o[328]
    DIRECTION OUTPUT ;
    USE SIGNAL ;
    PORT
      LAYER M3 ;
        RECT  34.344 0 34.362 0.144 ;
    END
  END o[328]
  PIN o[329]
    DIRECTION OUTPUT ;
    USE SIGNAL ;
    PORT
      LAYER M5 ;
        RECT  34.464 0 34.488 0.192 ;
    END
  END o[329]
  PIN o[32]
    DIRECTION OUTPUT ;
    USE SIGNAL ;
    PORT
      LAYER M3 ;
        RECT  5.328 0 5.346 0.144 ;
    END
  END o[32]
  PIN o[330]
    DIRECTION OUTPUT ;
    USE SIGNAL ;
    PORT
      LAYER M3 ;
        RECT  34.56 0 34.578 0.144 ;
    END
  END o[330]
  PIN o[331]
    DIRECTION OUTPUT ;
    USE SIGNAL ;
    PORT
      LAYER M5 ;
        RECT  34.656 0 34.68 0.192 ;
    END
  END o[331]
  PIN o[332]
    DIRECTION OUTPUT ;
    USE SIGNAL ;
    PORT
      LAYER M3 ;
        RECT  34.74 0 34.758 0.144 ;
    END
  END o[332]
  PIN o[333]
    DIRECTION OUTPUT ;
    USE SIGNAL ;
    PORT
      LAYER M5 ;
        RECT  34.848 0 34.872 0.192 ;
    END
  END o[333]
  PIN o[334]
    DIRECTION OUTPUT ;
    USE SIGNAL ;
    PORT
      LAYER M3 ;
        RECT  34.956 0 34.974 0.144 ;
    END
  END o[334]
  PIN o[335]
    DIRECTION OUTPUT ;
    USE SIGNAL ;
    PORT
      LAYER M5 ;
        RECT  35.04 0 35.064 0.192 ;
    END
  END o[335]
  PIN o[336]
    DIRECTION OUTPUT ;
    USE SIGNAL ;
    PORT
      LAYER M3 ;
        RECT  35.136 0 35.154 0.144 ;
    END
  END o[336]
  PIN o[337]
    DIRECTION OUTPUT ;
    USE SIGNAL ;
    PORT
      LAYER M5 ;
        RECT  35.232 0 35.256 0.192 ;
    END
  END o[337]
  PIN o[338]
    DIRECTION OUTPUT ;
    USE SIGNAL ;
    PORT
      LAYER M3 ;
        RECT  35.352 0 35.37 0.144 ;
    END
  END o[338]
  PIN o[339]
    DIRECTION OUTPUT ;
    USE SIGNAL ;
    PORT
      LAYER M5 ;
        RECT  35.424 0 35.448 0.192 ;
    END
  END o[339]
  PIN o[33]
    DIRECTION OUTPUT ;
    USE SIGNAL ;
    PORT
      LAYER M5 ;
        RECT  5.424 0 5.448 0.192 ;
    END
  END o[33]
  PIN o[340]
    DIRECTION OUTPUT ;
    USE SIGNAL ;
    PORT
      LAYER M3 ;
        RECT  35.532 0 35.55 0.144 ;
    END
  END o[340]
  PIN o[341]
    DIRECTION OUTPUT ;
    USE SIGNAL ;
    PORT
      LAYER M5 ;
        RECT  35.616 0 35.64 0.192 ;
    END
  END o[341]
  PIN o[342]
    DIRECTION OUTPUT ;
    USE SIGNAL ;
    PORT
      LAYER M3 ;
        RECT  35.712 0 35.73 0.144 ;
    END
  END o[342]
  PIN o[343]
    DIRECTION OUTPUT ;
    USE SIGNAL ;
    PORT
      LAYER M5 ;
        RECT  35.808 0 35.832 0.192 ;
    END
  END o[343]
  PIN o[344]
    DIRECTION OUTPUT ;
    USE SIGNAL ;
    PORT
      LAYER M3 ;
        RECT  35.928 0 35.946 0.144 ;
    END
  END o[344]
  PIN o[345]
    DIRECTION OUTPUT ;
    USE SIGNAL ;
    PORT
      LAYER M5 ;
        RECT  36 0 36.024 0.192 ;
    END
  END o[345]
  PIN o[346]
    DIRECTION OUTPUT ;
    USE SIGNAL ;
    PORT
      LAYER M3 ;
        RECT  36.108 0 36.126 0.144 ;
    END
  END o[346]
  PIN o[347]
    DIRECTION OUTPUT ;
    USE SIGNAL ;
    PORT
      LAYER M5 ;
        RECT  36.24 0 36.264 0.192 ;
    END
  END o[347]
  PIN o[348]
    DIRECTION OUTPUT ;
    USE SIGNAL ;
    PORT
      LAYER M3 ;
        RECT  36.324 0 36.342 0.144 ;
    END
  END o[348]
  PIN o[349]
    DIRECTION OUTPUT ;
    USE SIGNAL ;
    PORT
      LAYER M5 ;
        RECT  36.432 0 36.456 0.192 ;
    END
  END o[349]
  PIN o[34]
    DIRECTION OUTPUT ;
    USE SIGNAL ;
    PORT
      LAYER M3 ;
        RECT  5.544 0 5.562 0.144 ;
    END
  END o[34]
  PIN o[350]
    DIRECTION OUTPUT ;
    USE SIGNAL ;
    PORT
      LAYER M3 ;
        RECT  36.504 0 36.522 0.144 ;
    END
  END o[350]
  PIN o[351]
    DIRECTION OUTPUT ;
    USE SIGNAL ;
    PORT
      LAYER M5 ;
        RECT  36.624 0 36.648 0.192 ;
    END
  END o[351]
  PIN o[352]
    DIRECTION OUTPUT ;
    USE SIGNAL ;
    PORT
      LAYER M3 ;
        RECT  36.72 0 36.738 0.144 ;
    END
  END o[352]
  PIN o[353]
    DIRECTION OUTPUT ;
    USE SIGNAL ;
    PORT
      LAYER M5 ;
        RECT  36.816 0 36.84 0.192 ;
    END
  END o[353]
  PIN o[354]
    DIRECTION OUTPUT ;
    USE SIGNAL ;
    PORT
      LAYER M3 ;
        RECT  36.9 0 36.918 0.144 ;
    END
  END o[354]
  PIN o[355]
    DIRECTION OUTPUT ;
    USE SIGNAL ;
    PORT
      LAYER M5 ;
        RECT  37.008 0 37.032 0.192 ;
    END
  END o[355]
  PIN o[356]
    DIRECTION OUTPUT ;
    USE SIGNAL ;
    PORT
      LAYER M3 ;
        RECT  37.116 0 37.134 0.144 ;
    END
  END o[356]
  PIN o[357]
    DIRECTION OUTPUT ;
    USE SIGNAL ;
    PORT
      LAYER M5 ;
        RECT  37.2 0 37.224 0.192 ;
    END
  END o[357]
  PIN o[358]
    DIRECTION OUTPUT ;
    USE SIGNAL ;
    PORT
      LAYER M3 ;
        RECT  37.296 0 37.314 0.144 ;
    END
  END o[358]
  PIN o[359]
    DIRECTION OUTPUT ;
    USE SIGNAL ;
    PORT
      LAYER M5 ;
        RECT  37.392 0 37.416 0.192 ;
    END
  END o[359]
  PIN o[35]
    DIRECTION OUTPUT ;
    USE SIGNAL ;
    PORT
      LAYER M5 ;
        RECT  5.616 0 5.64 0.192 ;
    END
  END o[35]
  PIN o[360]
    DIRECTION OUTPUT ;
    USE SIGNAL ;
    PORT
      LAYER M3 ;
        RECT  37.476 0 37.494 0.144 ;
    END
  END o[360]
  PIN o[361]
    DIRECTION OUTPUT ;
    USE SIGNAL ;
    PORT
      LAYER M5 ;
        RECT  37.584 0 37.608 0.192 ;
    END
  END o[361]
  PIN o[362]
    DIRECTION OUTPUT ;
    USE SIGNAL ;
    PORT
      LAYER M3 ;
        RECT  37.692 0 37.71 0.144 ;
    END
  END o[362]
  PIN o[363]
    DIRECTION OUTPUT ;
    USE SIGNAL ;
    PORT
      LAYER M5 ;
        RECT  37.776 0 37.8 0.192 ;
    END
  END o[363]
  PIN o[364]
    DIRECTION OUTPUT ;
    USE SIGNAL ;
    PORT
      LAYER M3 ;
        RECT  37.872 0 37.89 0.144 ;
    END
  END o[364]
  PIN o[365]
    DIRECTION OUTPUT ;
    USE SIGNAL ;
    PORT
      LAYER M5 ;
        RECT  37.968 0 37.992 0.192 ;
    END
  END o[365]
  PIN o[366]
    DIRECTION OUTPUT ;
    USE SIGNAL ;
    PORT
      LAYER M3 ;
        RECT  38.088 0 38.106 0.144 ;
    END
  END o[366]
  PIN o[367]
    DIRECTION OUTPUT ;
    USE SIGNAL ;
    PORT
      LAYER M5 ;
        RECT  38.16 0 38.184 0.192 ;
    END
  END o[367]
  PIN o[368]
    DIRECTION OUTPUT ;
    USE SIGNAL ;
    PORT
      LAYER M3 ;
        RECT  38.268 0 38.286 0.144 ;
    END
  END o[368]
  PIN o[369]
    DIRECTION OUTPUT ;
    USE SIGNAL ;
    PORT
      LAYER M5 ;
        RECT  38.352 0 38.376 0.192 ;
    END
  END o[369]
  PIN o[36]
    DIRECTION OUTPUT ;
    USE SIGNAL ;
    PORT
      LAYER M3 ;
        RECT  5.724 0 5.742 0.144 ;
    END
  END o[36]
  PIN o[370]
    DIRECTION OUTPUT ;
    USE SIGNAL ;
    PORT
      LAYER M3 ;
        RECT  38.484 0 38.502 0.144 ;
    END
  END o[370]
  PIN o[371]
    DIRECTION OUTPUT ;
    USE SIGNAL ;
    PORT
      LAYER M5 ;
        RECT  38.592 0 38.616 0.192 ;
    END
  END o[371]
  PIN o[372]
    DIRECTION OUTPUT ;
    USE SIGNAL ;
    PORT
      LAYER M3 ;
        RECT  38.664 0 38.682 0.144 ;
    END
  END o[372]
  PIN o[373]
    DIRECTION OUTPUT ;
    USE SIGNAL ;
    PORT
      LAYER M5 ;
        RECT  38.784 0 38.808 0.192 ;
    END
  END o[373]
  PIN o[374]
    DIRECTION OUTPUT ;
    USE SIGNAL ;
    PORT
      LAYER M3 ;
        RECT  38.88 0 38.898 0.144 ;
    END
  END o[374]
  PIN o[375]
    DIRECTION OUTPUT ;
    USE SIGNAL ;
    PORT
      LAYER M5 ;
        RECT  38.976 0 39 0.192 ;
    END
  END o[375]
  PIN o[376]
    DIRECTION OUTPUT ;
    USE SIGNAL ;
    PORT
      LAYER M3 ;
        RECT  39.06 0 39.078 0.144 ;
    END
  END o[376]
  PIN o[377]
    DIRECTION OUTPUT ;
    USE SIGNAL ;
    PORT
      LAYER M5 ;
        RECT  39.168 0 39.192 0.192 ;
    END
  END o[377]
  PIN o[378]
    DIRECTION OUTPUT ;
    USE SIGNAL ;
    PORT
      LAYER M3 ;
        RECT  39.276 0 39.294 0.144 ;
    END
  END o[378]
  PIN o[379]
    DIRECTION OUTPUT ;
    USE SIGNAL ;
    PORT
      LAYER M5 ;
        RECT  39.36 0 39.384 0.192 ;
    END
  END o[379]
  PIN o[37]
    DIRECTION OUTPUT ;
    USE SIGNAL ;
    PORT
      LAYER M5 ;
        RECT  5.808 0 5.832 0.192 ;
    END
  END o[37]
  PIN o[380]
    DIRECTION OUTPUT ;
    USE SIGNAL ;
    PORT
      LAYER M3 ;
        RECT  39.456 0 39.474 0.144 ;
    END
  END o[380]
  PIN o[381]
    DIRECTION OUTPUT ;
    USE SIGNAL ;
    PORT
      LAYER M5 ;
        RECT  39.552 0 39.576 0.192 ;
    END
  END o[381]
  PIN o[382]
    DIRECTION OUTPUT ;
    USE SIGNAL ;
    PORT
      LAYER M3 ;
        RECT  39.636 0 39.654 0.144 ;
    END
  END o[382]
  PIN o[383]
    DIRECTION OUTPUT ;
    USE SIGNAL ;
    PORT
      LAYER M5 ;
        RECT  39.744 0 39.768 0.192 ;
    END
  END o[383]
  PIN o[384]
    DIRECTION OUTPUT ;
    USE SIGNAL ;
    PORT
      LAYER M3 ;
        RECT  39.852 0 39.87 0.144 ;
    END
  END o[384]
  PIN o[385]
    DIRECTION OUTPUT ;
    USE SIGNAL ;
    PORT
      LAYER M5 ;
        RECT  39.936 0 39.96 0.192 ;
    END
  END o[385]
  PIN o[386]
    DIRECTION OUTPUT ;
    USE SIGNAL ;
    PORT
      LAYER M3 ;
        RECT  40.032 0 40.05 0.144 ;
    END
  END o[386]
  PIN o[387]
    DIRECTION OUTPUT ;
    USE SIGNAL ;
    PORT
      LAYER M5 ;
        RECT  40.128 0 40.152 0.192 ;
    END
  END o[387]
  PIN o[388]
    DIRECTION OUTPUT ;
    USE SIGNAL ;
    PORT
      LAYER M3 ;
        RECT  40.248 0 40.266 0.144 ;
    END
  END o[388]
  PIN o[389]
    DIRECTION OUTPUT ;
    USE SIGNAL ;
    PORT
      LAYER M5 ;
        RECT  40.32 0 40.344 0.192 ;
    END
  END o[389]
  PIN o[38]
    DIRECTION OUTPUT ;
    USE SIGNAL ;
    PORT
      LAYER M3 ;
        RECT  5.94 0 5.958 0.144 ;
    END
  END o[38]
  PIN o[390]
    DIRECTION OUTPUT ;
    USE SIGNAL ;
    PORT
      LAYER M3 ;
        RECT  40.428 0 40.446 0.144 ;
    END
  END o[390]
  PIN o[391]
    DIRECTION OUTPUT ;
    USE SIGNAL ;
    PORT
      LAYER M5 ;
        RECT  40.512 0 40.536 0.192 ;
    END
  END o[391]
  PIN o[392]
    DIRECTION OUTPUT ;
    USE SIGNAL ;
    PORT
      LAYER M3 ;
        RECT  40.644 0 40.662 0.144 ;
    END
  END o[392]
  PIN o[393]
    DIRECTION OUTPUT ;
    USE SIGNAL ;
    PORT
      LAYER M5 ;
        RECT  40.704 0 40.728 0.192 ;
    END
  END o[393]
  PIN o[394]
    DIRECTION OUTPUT ;
    USE SIGNAL ;
    PORT
      LAYER M3 ;
        RECT  40.824 0 40.842 0.144 ;
    END
  END o[394]
  PIN o[395]
    DIRECTION OUTPUT ;
    USE SIGNAL ;
    PORT
      LAYER M5 ;
        RECT  40.944 0 40.968 0.192 ;
    END
  END o[395]
  PIN o[396]
    DIRECTION OUTPUT ;
    USE SIGNAL ;
    PORT
      LAYER M3 ;
        RECT  41.04 0 41.058 0.144 ;
    END
  END o[396]
  PIN o[397]
    DIRECTION OUTPUT ;
    USE SIGNAL ;
    PORT
      LAYER M5 ;
        RECT  41.136 0 41.16 0.192 ;
    END
  END o[397]
  PIN o[398]
    DIRECTION OUTPUT ;
    USE SIGNAL ;
    PORT
      LAYER M3 ;
        RECT  41.22 0 41.238 0.144 ;
    END
  END o[398]
  PIN o[399]
    DIRECTION OUTPUT ;
    USE SIGNAL ;
    PORT
      LAYER M5 ;
        RECT  41.328 0 41.352 0.192 ;
    END
  END o[399]
  PIN o[39]
    DIRECTION OUTPUT ;
    USE SIGNAL ;
    PORT
      LAYER M5 ;
        RECT  6 0 6.024 0.192 ;
    END
  END o[39]
  PIN o[3]
    DIRECTION OUTPUT ;
    USE SIGNAL ;
    PORT
      LAYER M5 ;
        RECT  2.496 0 2.52 0.192 ;
    END
  END o[3]
  PIN o[400]
    DIRECTION OUTPUT ;
    USE SIGNAL ;
    PORT
      LAYER M3 ;
        RECT  41.4 0 41.418 0.144 ;
    END
  END o[400]
  PIN o[401]
    DIRECTION OUTPUT ;
    USE SIGNAL ;
    PORT
      LAYER M5 ;
        RECT  41.52 0 41.544 0.192 ;
    END
  END o[401]
  PIN o[402]
    DIRECTION OUTPUT ;
    USE SIGNAL ;
    PORT
      LAYER M3 ;
        RECT  41.616 0 41.634 0.144 ;
    END
  END o[402]
  PIN o[403]
    DIRECTION OUTPUT ;
    USE SIGNAL ;
    PORT
      LAYER M5 ;
        RECT  41.712 0 41.736 0.192 ;
    END
  END o[403]
  PIN o[404]
    DIRECTION OUTPUT ;
    USE SIGNAL ;
    PORT
      LAYER M3 ;
        RECT  41.796 0 41.814 0.144 ;
    END
  END o[404]
  PIN o[405]
    DIRECTION OUTPUT ;
    USE SIGNAL ;
    PORT
      LAYER M5 ;
        RECT  41.904 0 41.928 0.192 ;
    END
  END o[405]
  PIN o[406]
    DIRECTION OUTPUT ;
    USE SIGNAL ;
    PORT
      LAYER M3 ;
        RECT  42.012 0 42.03 0.144 ;
    END
  END o[406]
  PIN o[407]
    DIRECTION OUTPUT ;
    USE SIGNAL ;
    PORT
      LAYER M5 ;
        RECT  42.096 0 42.12 0.192 ;
    END
  END o[407]
  PIN o[408]
    DIRECTION OUTPUT ;
    USE SIGNAL ;
    PORT
      LAYER M3 ;
        RECT  42.192 0 42.21 0.144 ;
    END
  END o[408]
  PIN o[409]
    DIRECTION OUTPUT ;
    USE SIGNAL ;
    PORT
      LAYER M5 ;
        RECT  42.288 0 42.312 0.192 ;
    END
  END o[409]
  PIN o[40]
    DIRECTION OUTPUT ;
    USE SIGNAL ;
    PORT
      LAYER M3 ;
        RECT  6.12 0 6.138 0.144 ;
    END
  END o[40]
  PIN o[410]
    DIRECTION OUTPUT ;
    USE SIGNAL ;
    PORT
      LAYER M3 ;
        RECT  42.408 0 42.426 0.144 ;
    END
  END o[410]
  PIN o[411]
    DIRECTION OUTPUT ;
    USE SIGNAL ;
    PORT
      LAYER M5 ;
        RECT  42.48 0 42.504 0.192 ;
    END
  END o[411]
  PIN o[412]
    DIRECTION OUTPUT ;
    USE SIGNAL ;
    PORT
      LAYER M3 ;
        RECT  42.588 0 42.606 0.144 ;
    END
  END o[412]
  PIN o[413]
    DIRECTION OUTPUT ;
    USE SIGNAL ;
    PORT
      LAYER M5 ;
        RECT  42.672 0 42.696 0.192 ;
    END
  END o[413]
  PIN o[414]
    DIRECTION OUTPUT ;
    USE SIGNAL ;
    PORT
      LAYER M3 ;
        RECT  42.804 0 42.822 0.144 ;
    END
  END o[414]
  PIN o[415]
    DIRECTION OUTPUT ;
    USE SIGNAL ;
    PORT
      LAYER M5 ;
        RECT  42.864 0 42.888 0.192 ;
    END
  END o[415]
  PIN o[416]
    DIRECTION OUTPUT ;
    USE SIGNAL ;
    PORT
      LAYER M3 ;
        RECT  42.984 0 43.002 0.144 ;
    END
  END o[416]
  PIN o[417]
    DIRECTION OUTPUT ;
    USE SIGNAL ;
    PORT
      LAYER M5 ;
        RECT  43.056 0 43.08 0.192 ;
    END
  END o[417]
  PIN o[418]
    DIRECTION OUTPUT ;
    USE SIGNAL ;
    PORT
      LAYER M3 ;
        RECT  43.164 0 43.182 0.144 ;
    END
  END o[418]
  PIN o[419]
    DIRECTION OUTPUT ;
    USE SIGNAL ;
    PORT
      LAYER M5 ;
        RECT  43.296 0 43.32 0.192 ;
    END
  END o[419]
  PIN o[41]
    DIRECTION OUTPUT ;
    USE SIGNAL ;
    PORT
      LAYER M5 ;
        RECT  6.24 0 6.264 0.192 ;
    END
  END o[41]
  PIN o[420]
    DIRECTION OUTPUT ;
    USE SIGNAL ;
    PORT
      LAYER M3 ;
        RECT  43.38 0 43.398 0.144 ;
    END
  END o[420]
  PIN o[421]
    DIRECTION OUTPUT ;
    USE SIGNAL ;
    PORT
      LAYER M5 ;
        RECT  43.488 0 43.512 0.192 ;
    END
  END o[421]
  PIN o[422]
    DIRECTION OUTPUT ;
    USE SIGNAL ;
    PORT
      LAYER M3 ;
        RECT  43.56 0 43.578 0.144 ;
    END
  END o[422]
  PIN o[423]
    DIRECTION OUTPUT ;
    USE SIGNAL ;
    PORT
      LAYER M5 ;
        RECT  43.68 0 43.704 0.192 ;
    END
  END o[423]
  PIN o[424]
    DIRECTION OUTPUT ;
    USE SIGNAL ;
    PORT
      LAYER M3 ;
        RECT  43.776 0 43.794 0.144 ;
    END
  END o[424]
  PIN o[425]
    DIRECTION OUTPUT ;
    USE SIGNAL ;
    PORT
      LAYER M5 ;
        RECT  43.872 0 43.896 0.192 ;
    END
  END o[425]
  PIN o[426]
    DIRECTION OUTPUT ;
    USE SIGNAL ;
    PORT
      LAYER M3 ;
        RECT  43.956 0 43.974 0.144 ;
    END
  END o[426]
  PIN o[427]
    DIRECTION OUTPUT ;
    USE SIGNAL ;
    PORT
      LAYER M5 ;
        RECT  44.064 0 44.088 0.192 ;
    END
  END o[427]
  PIN o[428]
    DIRECTION OUTPUT ;
    USE SIGNAL ;
    PORT
      LAYER M3 ;
        RECT  44.172 0 44.19 0.144 ;
    END
  END o[428]
  PIN o[429]
    DIRECTION OUTPUT ;
    USE SIGNAL ;
    PORT
      LAYER M5 ;
        RECT  44.256 0 44.28 0.192 ;
    END
  END o[429]
  PIN o[42]
    DIRECTION OUTPUT ;
    USE SIGNAL ;
    PORT
      LAYER M3 ;
        RECT  6.3 0 6.318 0.144 ;
    END
  END o[42]
  PIN o[430]
    DIRECTION OUTPUT ;
    USE SIGNAL ;
    PORT
      LAYER M3 ;
        RECT  44.352 0 44.37 0.144 ;
    END
  END o[430]
  PIN o[431]
    DIRECTION OUTPUT ;
    USE SIGNAL ;
    PORT
      LAYER M5 ;
        RECT  44.448 0 44.472 0.192 ;
    END
  END o[431]
  PIN o[432]
    DIRECTION OUTPUT ;
    USE SIGNAL ;
    PORT
      LAYER M3 ;
        RECT  44.568 0 44.586 0.144 ;
    END
  END o[432]
  PIN o[433]
    DIRECTION OUTPUT ;
    USE SIGNAL ;
    PORT
      LAYER M5 ;
        RECT  44.64 0 44.664 0.192 ;
    END
  END o[433]
  PIN o[434]
    DIRECTION OUTPUT ;
    USE SIGNAL ;
    PORT
      LAYER M3 ;
        RECT  44.748 0 44.766 0.144 ;
    END
  END o[434]
  PIN o[435]
    DIRECTION OUTPUT ;
    USE SIGNAL ;
    PORT
      LAYER M5 ;
        RECT  44.832 0 44.856 0.192 ;
    END
  END o[435]
  PIN o[436]
    DIRECTION OUTPUT ;
    USE SIGNAL ;
    PORT
      LAYER M3 ;
        RECT  44.928 0 44.946 0.144 ;
    END
  END o[436]
  PIN o[437]
    DIRECTION OUTPUT ;
    USE SIGNAL ;
    PORT
      LAYER M5 ;
        RECT  45.024 0 45.048 0.192 ;
    END
  END o[437]
  PIN o[438]
    DIRECTION OUTPUT ;
    USE SIGNAL ;
    PORT
      LAYER M3 ;
        RECT  45.144 0 45.162 0.144 ;
    END
  END o[438]
  PIN o[439]
    DIRECTION OUTPUT ;
    USE SIGNAL ;
    PORT
      LAYER M5 ;
        RECT  45.216 0 45.24 0.192 ;
    END
  END o[439]
  PIN o[43]
    DIRECTION OUTPUT ;
    USE SIGNAL ;
    PORT
      LAYER M5 ;
        RECT  6.432 0 6.456 0.192 ;
    END
  END o[43]
  PIN o[440]
    DIRECTION OUTPUT ;
    USE SIGNAL ;
    PORT
      LAYER M3 ;
        RECT  45.324 0 45.342 0.144 ;
    END
  END o[440]
  PIN o[441]
    DIRECTION OUTPUT ;
    USE SIGNAL ;
    PORT
      LAYER M5 ;
        RECT  45.408 0 45.432 0.192 ;
    END
  END o[441]
  PIN o[442]
    DIRECTION OUTPUT ;
    USE SIGNAL ;
    PORT
      LAYER M3 ;
        RECT  45.54 0 45.558 0.144 ;
    END
  END o[442]
  PIN o[443]
    DIRECTION OUTPUT ;
    USE SIGNAL ;
    PORT
      LAYER M5 ;
        RECT  45.648 0 45.672 0.192 ;
    END
  END o[443]
  PIN o[444]
    DIRECTION OUTPUT ;
    USE SIGNAL ;
    PORT
      LAYER M3 ;
        RECT  45.72 0 45.738 0.144 ;
    END
  END o[444]
  PIN o[445]
    DIRECTION OUTPUT ;
    USE SIGNAL ;
    PORT
      LAYER M5 ;
        RECT  45.84 0 45.864 0.192 ;
    END
  END o[445]
  PIN o[446]
    DIRECTION OUTPUT ;
    USE SIGNAL ;
    PORT
      LAYER M3 ;
        RECT  45.936 0 45.954 0.144 ;
    END
  END o[446]
  PIN o[447]
    DIRECTION OUTPUT ;
    USE SIGNAL ;
    PORT
      LAYER M5 ;
        RECT  46.032 0 46.056 0.192 ;
    END
  END o[447]
  PIN o[448]
    DIRECTION OUTPUT ;
    USE SIGNAL ;
    PORT
      LAYER M3 ;
        RECT  46.116 0 46.134 0.144 ;
    END
  END o[448]
  PIN o[449]
    DIRECTION OUTPUT ;
    USE SIGNAL ;
    PORT
      LAYER M5 ;
        RECT  46.224 0 46.248 0.192 ;
    END
  END o[449]
  PIN o[44]
    DIRECTION OUTPUT ;
    USE SIGNAL ;
    PORT
      LAYER M3 ;
        RECT  6.516 0 6.534 0.144 ;
    END
  END o[44]
  PIN o[450]
    DIRECTION OUTPUT ;
    USE SIGNAL ;
    PORT
      LAYER M3 ;
        RECT  46.332 0 46.35 0.144 ;
    END
  END o[450]
  PIN o[451]
    DIRECTION OUTPUT ;
    USE SIGNAL ;
    PORT
      LAYER M5 ;
        RECT  46.416 0 46.44 0.192 ;
    END
  END o[451]
  PIN o[452]
    DIRECTION OUTPUT ;
    USE SIGNAL ;
    PORT
      LAYER M3 ;
        RECT  46.512 0 46.53 0.144 ;
    END
  END o[452]
  PIN o[453]
    DIRECTION OUTPUT ;
    USE SIGNAL ;
    PORT
      LAYER M5 ;
        RECT  46.608 0 46.632 0.192 ;
    END
  END o[453]
  PIN o[454]
    DIRECTION OUTPUT ;
    USE SIGNAL ;
    PORT
      LAYER M3 ;
        RECT  46.692 0 46.71 0.144 ;
    END
  END o[454]
  PIN o[455]
    DIRECTION OUTPUT ;
    USE SIGNAL ;
    PORT
      LAYER M5 ;
        RECT  46.8 0 46.824 0.192 ;
    END
  END o[455]
  PIN o[456]
    DIRECTION OUTPUT ;
    USE SIGNAL ;
    PORT
      LAYER M3 ;
        RECT  46.908 0 46.926 0.144 ;
    END
  END o[456]
  PIN o[457]
    DIRECTION OUTPUT ;
    USE SIGNAL ;
    PORT
      LAYER M5 ;
        RECT  46.992 0 47.016 0.192 ;
    END
  END o[457]
  PIN o[458]
    DIRECTION OUTPUT ;
    USE SIGNAL ;
    PORT
      LAYER M3 ;
        RECT  47.088 0 47.106 0.144 ;
    END
  END o[458]
  PIN o[459]
    DIRECTION OUTPUT ;
    USE SIGNAL ;
    PORT
      LAYER M5 ;
        RECT  47.184 0 47.208 0.192 ;
    END
  END o[459]
  PIN o[45]
    DIRECTION OUTPUT ;
    USE SIGNAL ;
    PORT
      LAYER M5 ;
        RECT  6.624 0 6.648 0.192 ;
    END
  END o[45]
  PIN o[460]
    DIRECTION OUTPUT ;
    USE SIGNAL ;
    PORT
      LAYER M3 ;
        RECT  47.304 0 47.322 0.144 ;
    END
  END o[460]
  PIN o[461]
    DIRECTION OUTPUT ;
    USE SIGNAL ;
    PORT
      LAYER M5 ;
        RECT  47.376 0 47.4 0.192 ;
    END
  END o[461]
  PIN o[462]
    DIRECTION OUTPUT ;
    USE SIGNAL ;
    PORT
      LAYER M3 ;
        RECT  47.484 0 47.502 0.144 ;
    END
  END o[462]
  PIN o[463]
    DIRECTION OUTPUT ;
    USE SIGNAL ;
    PORT
      LAYER M5 ;
        RECT  47.568 0 47.592 0.192 ;
    END
  END o[463]
  PIN o[464]
    DIRECTION OUTPUT ;
    USE SIGNAL ;
    PORT
      LAYER M3 ;
        RECT  47.7 0 47.718 0.144 ;
    END
  END o[464]
  PIN o[465]
    DIRECTION OUTPUT ;
    USE SIGNAL ;
    PORT
      LAYER M5 ;
        RECT  47.808 0 47.832 0.192 ;
    END
  END o[465]
  PIN o[466]
    DIRECTION OUTPUT ;
    USE SIGNAL ;
    PORT
      LAYER M3 ;
        RECT  47.88 0 47.898 0.144 ;
    END
  END o[466]
  PIN o[467]
    DIRECTION OUTPUT ;
    USE SIGNAL ;
    PORT
      LAYER M5 ;
        RECT  48 0 48.024 0.192 ;
    END
  END o[467]
  PIN o[468]
    DIRECTION OUTPUT ;
    USE SIGNAL ;
    PORT
      LAYER M3 ;
        RECT  48.096 0 48.114 0.144 ;
    END
  END o[468]
  PIN o[469]
    DIRECTION OUTPUT ;
    USE SIGNAL ;
    PORT
      LAYER M5 ;
        RECT  48.192 0 48.216 0.192 ;
    END
  END o[469]
  PIN o[46]
    DIRECTION OUTPUT ;
    USE SIGNAL ;
    PORT
      LAYER M3 ;
        RECT  6.696 0 6.714 0.144 ;
    END
  END o[46]
  PIN o[470]
    DIRECTION OUTPUT ;
    USE SIGNAL ;
    PORT
      LAYER M3 ;
        RECT  48.276 0 48.294 0.144 ;
    END
  END o[470]
  PIN o[471]
    DIRECTION OUTPUT ;
    USE SIGNAL ;
    PORT
      LAYER M5 ;
        RECT  48.384 0 48.408 0.192 ;
    END
  END o[471]
  PIN o[472]
    DIRECTION OUTPUT ;
    USE SIGNAL ;
    PORT
      LAYER M3 ;
        RECT  48.456 0 48.474 0.144 ;
    END
  END o[472]
  PIN o[473]
    DIRECTION OUTPUT ;
    USE SIGNAL ;
    PORT
      LAYER M5 ;
        RECT  48.576 0 48.6 0.192 ;
    END
  END o[473]
  PIN o[474]
    DIRECTION OUTPUT ;
    USE SIGNAL ;
    PORT
      LAYER M3 ;
        RECT  48.672 0 48.69 0.144 ;
    END
  END o[474]
  PIN o[475]
    DIRECTION OUTPUT ;
    USE SIGNAL ;
    PORT
      LAYER M5 ;
        RECT  48.768 0 48.792 0.192 ;
    END
  END o[475]
  PIN o[476]
    DIRECTION OUTPUT ;
    USE SIGNAL ;
    PORT
      LAYER M3 ;
        RECT  48.852 0 48.87 0.144 ;
    END
  END o[476]
  PIN o[477]
    DIRECTION OUTPUT ;
    USE SIGNAL ;
    PORT
      LAYER M5 ;
        RECT  48.96 0 48.984 0.192 ;
    END
  END o[477]
  PIN o[478]
    DIRECTION OUTPUT ;
    USE SIGNAL ;
    PORT
      LAYER M3 ;
        RECT  49.068 0 49.086 0.144 ;
    END
  END o[478]
  PIN o[479]
    DIRECTION OUTPUT ;
    USE SIGNAL ;
    PORT
      LAYER M5 ;
        RECT  49.152 0 49.176 0.192 ;
    END
  END o[479]
  PIN o[47]
    DIRECTION OUTPUT ;
    USE SIGNAL ;
    PORT
      LAYER M5 ;
        RECT  6.816 0 6.84 0.192 ;
    END
  END o[47]
  PIN o[480]
    DIRECTION OUTPUT ;
    USE SIGNAL ;
    PORT
      LAYER M3 ;
        RECT  49.248 0 49.266 0.144 ;
    END
  END o[480]
  PIN o[481]
    DIRECTION OUTPUT ;
    USE SIGNAL ;
    PORT
      LAYER M5 ;
        RECT  49.344 0 49.368 0.192 ;
    END
  END o[481]
  PIN o[482]
    DIRECTION OUTPUT ;
    USE SIGNAL ;
    PORT
      LAYER M3 ;
        RECT  49.464 0 49.482 0.144 ;
    END
  END o[482]
  PIN o[483]
    DIRECTION OUTPUT ;
    USE SIGNAL ;
    PORT
      LAYER M5 ;
        RECT  49.536 0 49.56 0.192 ;
    END
  END o[483]
  PIN o[484]
    DIRECTION OUTPUT ;
    USE SIGNAL ;
    PORT
      LAYER M3 ;
        RECT  49.644 0 49.662 0.144 ;
    END
  END o[484]
  PIN o[485]
    DIRECTION OUTPUT ;
    USE SIGNAL ;
    PORT
      LAYER M5 ;
        RECT  49.728 0 49.752 0.192 ;
    END
  END o[485]
  PIN o[486]
    DIRECTION OUTPUT ;
    USE SIGNAL ;
    PORT
      LAYER M3 ;
        RECT  49.86 0 49.878 0.144 ;
    END
  END o[486]
  PIN o[487]
    DIRECTION OUTPUT ;
    USE SIGNAL ;
    PORT
      LAYER M5 ;
        RECT  49.92 0 49.944 0.192 ;
    END
  END o[487]
  PIN o[488]
    DIRECTION OUTPUT ;
    USE SIGNAL ;
    PORT
      LAYER M3 ;
        RECT  50.04 0 50.058 0.144 ;
    END
  END o[488]
  PIN o[489]
    DIRECTION OUTPUT ;
    USE SIGNAL ;
    PORT
      LAYER M5 ;
        RECT  50.16 0 50.184 0.192 ;
    END
  END o[489]
  PIN o[48]
    DIRECTION OUTPUT ;
    USE SIGNAL ;
    PORT
      LAYER M3 ;
        RECT  6.912 0 6.93 0.144 ;
    END
  END o[48]
  PIN o[490]
    DIRECTION OUTPUT ;
    USE SIGNAL ;
    PORT
      LAYER M3 ;
        RECT  50.256 0 50.274 0.144 ;
    END
  END o[490]
  PIN o[491]
    DIRECTION OUTPUT ;
    USE SIGNAL ;
    PORT
      LAYER M5 ;
        RECT  50.352 0 50.376 0.192 ;
    END
  END o[491]
  PIN o[492]
    DIRECTION OUTPUT ;
    USE SIGNAL ;
    PORT
      LAYER M3 ;
        RECT  50.436 0 50.454 0.144 ;
    END
  END o[492]
  PIN o[493]
    DIRECTION OUTPUT ;
    USE SIGNAL ;
    PORT
      LAYER M5 ;
        RECT  50.544 0 50.568 0.192 ;
    END
  END o[493]
  PIN o[494]
    DIRECTION OUTPUT ;
    USE SIGNAL ;
    PORT
      LAYER M3 ;
        RECT  50.616 0 50.634 0.144 ;
    END
  END o[494]
  PIN o[495]
    DIRECTION OUTPUT ;
    USE SIGNAL ;
    PORT
      LAYER M5 ;
        RECT  50.736 0 50.76 0.192 ;
    END
  END o[495]
  PIN o[496]
    DIRECTION OUTPUT ;
    USE SIGNAL ;
    PORT
      LAYER M3 ;
        RECT  50.832 0 50.85 0.144 ;
    END
  END o[496]
  PIN o[497]
    DIRECTION OUTPUT ;
    USE SIGNAL ;
    PORT
      LAYER M5 ;
        RECT  50.928 0 50.952 0.192 ;
    END
  END o[497]
  PIN o[498]
    DIRECTION OUTPUT ;
    USE SIGNAL ;
    PORT
      LAYER M3 ;
        RECT  51.012 0 51.03 0.144 ;
    END
  END o[498]
  PIN o[499]
    DIRECTION OUTPUT ;
    USE SIGNAL ;
    PORT
      LAYER M5 ;
        RECT  51.12 0 51.144 0.192 ;
    END
  END o[499]
  PIN o[49]
    DIRECTION OUTPUT ;
    USE SIGNAL ;
    PORT
      LAYER M5 ;
        RECT  7.008 0 7.032 0.192 ;
    END
  END o[49]
  PIN o[4]
    DIRECTION OUTPUT ;
    USE SIGNAL ;
    PORT
      LAYER M3 ;
        RECT  2.592 0 2.61 0.144 ;
    END
  END o[4]
  PIN o[500]
    DIRECTION OUTPUT ;
    USE SIGNAL ;
    PORT
      LAYER M3 ;
        RECT  51.228 0 51.246 0.144 ;
    END
  END o[500]
  PIN o[501]
    DIRECTION OUTPUT ;
    USE SIGNAL ;
    PORT
      LAYER M5 ;
        RECT  51.312 0 51.336 0.192 ;
    END
  END o[501]
  PIN o[502]
    DIRECTION OUTPUT ;
    USE SIGNAL ;
    PORT
      LAYER M3 ;
        RECT  51.408 0 51.426 0.144 ;
    END
  END o[502]
  PIN o[503]
    DIRECTION OUTPUT ;
    USE SIGNAL ;
    PORT
      LAYER M5 ;
        RECT  51.504 0 51.528 0.192 ;
    END
  END o[503]
  PIN o[504]
    DIRECTION OUTPUT ;
    USE SIGNAL ;
    PORT
      LAYER M3 ;
        RECT  51.624 0 51.642 0.144 ;
    END
  END o[504]
  PIN o[505]
    DIRECTION OUTPUT ;
    USE SIGNAL ;
    PORT
      LAYER M5 ;
        RECT  51.696 0 51.72 0.192 ;
    END
  END o[505]
  PIN o[506]
    DIRECTION OUTPUT ;
    USE SIGNAL ;
    PORT
      LAYER M3 ;
        RECT  51.804 0 51.822 0.144 ;
    END
  END o[506]
  PIN o[507]
    DIRECTION OUTPUT ;
    USE SIGNAL ;
    PORT
      LAYER M5 ;
        RECT  51.888 0 51.912 0.192 ;
    END
  END o[507]
  PIN o[508]
    DIRECTION OUTPUT ;
    USE SIGNAL ;
    PORT
      LAYER M3 ;
        RECT  52.02 0 52.038 0.144 ;
    END
  END o[508]
  PIN o[509]
    DIRECTION OUTPUT ;
    USE SIGNAL ;
    PORT
      LAYER M5 ;
        RECT  52.08 0 52.104 0.192 ;
    END
  END o[509]
  PIN o[50]
    DIRECTION OUTPUT ;
    USE SIGNAL ;
    PORT
      LAYER M3 ;
        RECT  7.092 0 7.11 0.144 ;
    END
  END o[50]
  PIN o[510]
    DIRECTION OUTPUT ;
    USE SIGNAL ;
    PORT
      LAYER M3 ;
        RECT  52.2 0 52.218 0.144 ;
    END
  END o[510]
  PIN o[511]
    DIRECTION OUTPUT ;
    USE SIGNAL ;
    PORT
      LAYER M5 ;
        RECT  52.272 0 52.296 0.192 ;
    END
  END o[511]
  PIN o[512]
    DIRECTION OUTPUT ;
    USE SIGNAL ;
    PORT
      LAYER M3 ;
        RECT  52.38 0 52.398 0.144 ;
    END
  END o[512]
  PIN o[513]
    DIRECTION OUTPUT ;
    USE SIGNAL ;
    PORT
      LAYER M5 ;
        RECT  52.512 0 52.536 0.192 ;
    END
  END o[513]
  PIN o[514]
    DIRECTION OUTPUT ;
    USE SIGNAL ;
    PORT
      LAYER M3 ;
        RECT  52.596 0 52.614 0.144 ;
    END
  END o[514]
  PIN o[515]
    DIRECTION OUTPUT ;
    USE SIGNAL ;
    PORT
      LAYER M5 ;
        RECT  52.704 0 52.728 0.192 ;
    END
  END o[515]
  PIN o[516]
    DIRECTION OUTPUT ;
    USE SIGNAL ;
    PORT
      LAYER M3 ;
        RECT  52.776 0 52.794 0.144 ;
    END
  END o[516]
  PIN o[517]
    DIRECTION OUTPUT ;
    USE SIGNAL ;
    PORT
      LAYER M5 ;
        RECT  52.896 0 52.92 0.192 ;
    END
  END o[517]
  PIN o[518]
    DIRECTION OUTPUT ;
    USE SIGNAL ;
    PORT
      LAYER M3 ;
        RECT  52.992 0 53.01 0.144 ;
    END
  END o[518]
  PIN o[519]
    DIRECTION OUTPUT ;
    USE SIGNAL ;
    PORT
      LAYER M5 ;
        RECT  53.088 0 53.112 0.192 ;
    END
  END o[519]
  PIN o[51]
    DIRECTION OUTPUT ;
    USE SIGNAL ;
    PORT
      LAYER M5 ;
        RECT  7.2 0 7.224 0.192 ;
    END
  END o[51]
  PIN o[520]
    DIRECTION OUTPUT ;
    USE SIGNAL ;
    PORT
      LAYER M3 ;
        RECT  53.172 0 53.19 0.144 ;
    END
  END o[520]
  PIN o[521]
    DIRECTION OUTPUT ;
    USE SIGNAL ;
    PORT
      LAYER M5 ;
        RECT  53.28 0 53.304 0.192 ;
    END
  END o[521]
  PIN o[522]
    DIRECTION OUTPUT ;
    USE SIGNAL ;
    PORT
      LAYER M3 ;
        RECT  53.388 0 53.406 0.144 ;
    END
  END o[522]
  PIN o[523]
    DIRECTION OUTPUT ;
    USE SIGNAL ;
    PORT
      LAYER M5 ;
        RECT  53.472 0 53.496 0.192 ;
    END
  END o[523]
  PIN o[524]
    DIRECTION OUTPUT ;
    USE SIGNAL ;
    PORT
      LAYER M3 ;
        RECT  53.568 0 53.586 0.144 ;
    END
  END o[524]
  PIN o[525]
    DIRECTION OUTPUT ;
    USE SIGNAL ;
    PORT
      LAYER M5 ;
        RECT  53.664 0 53.688 0.192 ;
    END
  END o[525]
  PIN o[526]
    DIRECTION OUTPUT ;
    USE SIGNAL ;
    PORT
      LAYER M3 ;
        RECT  53.784 0 53.802 0.144 ;
    END
  END o[526]
  PIN o[527]
    DIRECTION OUTPUT ;
    USE SIGNAL ;
    PORT
      LAYER M5 ;
        RECT  53.856 0 53.88 0.192 ;
    END
  END o[527]
  PIN o[528]
    DIRECTION OUTPUT ;
    USE SIGNAL ;
    PORT
      LAYER M3 ;
        RECT  53.964 0 53.982 0.144 ;
    END
  END o[528]
  PIN o[529]
    DIRECTION OUTPUT ;
    USE SIGNAL ;
    PORT
      LAYER M5 ;
        RECT  54.048 0 54.072 0.192 ;
    END
  END o[529]
  PIN o[52]
    DIRECTION OUTPUT ;
    USE SIGNAL ;
    PORT
      LAYER M3 ;
        RECT  7.308 0 7.326 0.144 ;
    END
  END o[52]
  PIN o[530]
    DIRECTION OUTPUT ;
    USE SIGNAL ;
    PORT
      LAYER M3 ;
        RECT  54.144 0 54.162 0.144 ;
    END
  END o[530]
  PIN o[531]
    DIRECTION OUTPUT ;
    USE SIGNAL ;
    PORT
      LAYER M5 ;
        RECT  54.24 0 54.264 0.192 ;
    END
  END o[531]
  PIN o[532]
    DIRECTION OUTPUT ;
    USE SIGNAL ;
    PORT
      LAYER M3 ;
        RECT  54.36 0 54.378 0.144 ;
    END
  END o[532]
  PIN o[533]
    DIRECTION OUTPUT ;
    USE SIGNAL ;
    PORT
      LAYER M5 ;
        RECT  54.432 0 54.456 0.192 ;
    END
  END o[533]
  PIN o[534]
    DIRECTION OUTPUT ;
    USE SIGNAL ;
    PORT
      LAYER M3 ;
        RECT  54.54 0 54.558 0.144 ;
    END
  END o[534]
  PIN o[535]
    DIRECTION OUTPUT ;
    USE SIGNAL ;
    PORT
      LAYER M5 ;
        RECT  54.624 0 54.648 0.192 ;
    END
  END o[535]
  PIN o[536]
    DIRECTION OUTPUT ;
    USE SIGNAL ;
    PORT
      LAYER M3 ;
        RECT  54.756 0 54.774 0.144 ;
    END
  END o[536]
  PIN o[537]
    DIRECTION OUTPUT ;
    USE SIGNAL ;
    PORT
      LAYER M5 ;
        RECT  54.864 0 54.888 0.192 ;
    END
  END o[537]
  PIN o[538]
    DIRECTION OUTPUT ;
    USE SIGNAL ;
    PORT
      LAYER M3 ;
        RECT  54.936 0 54.954 0.144 ;
    END
  END o[538]
  PIN o[539]
    DIRECTION OUTPUT ;
    USE SIGNAL ;
    PORT
      LAYER M5 ;
        RECT  55.056 0 55.08 0.192 ;
    END
  END o[539]
  PIN o[53]
    DIRECTION OUTPUT ;
    USE SIGNAL ;
    PORT
      LAYER M5 ;
        RECT  7.392 0 7.416 0.192 ;
    END
  END o[53]
  PIN o[540]
    DIRECTION OUTPUT ;
    USE SIGNAL ;
    PORT
      LAYER M3 ;
        RECT  55.152 0 55.17 0.144 ;
    END
  END o[540]
  PIN o[541]
    DIRECTION OUTPUT ;
    USE SIGNAL ;
    PORT
      LAYER M5 ;
        RECT  55.248 0 55.272 0.192 ;
    END
  END o[541]
  PIN o[542]
    DIRECTION OUTPUT ;
    USE SIGNAL ;
    PORT
      LAYER M3 ;
        RECT  55.332 0 55.35 0.144 ;
    END
  END o[542]
  PIN o[543]
    DIRECTION OUTPUT ;
    USE SIGNAL ;
    PORT
      LAYER M5 ;
        RECT  55.44 0 55.464 0.192 ;
    END
  END o[543]
  PIN o[544]
    DIRECTION OUTPUT ;
    USE SIGNAL ;
    PORT
      LAYER M3 ;
        RECT  55.548 0 55.566 0.144 ;
    END
  END o[544]
  PIN o[545]
    DIRECTION OUTPUT ;
    USE SIGNAL ;
    PORT
      LAYER M5 ;
        RECT  55.632 0 55.656 0.192 ;
    END
  END o[545]
  PIN o[546]
    DIRECTION OUTPUT ;
    USE SIGNAL ;
    PORT
      LAYER M3 ;
        RECT  55.728 0 55.746 0.144 ;
    END
  END o[546]
  PIN o[547]
    DIRECTION OUTPUT ;
    USE SIGNAL ;
    PORT
      LAYER M5 ;
        RECT  55.824 0 55.848 0.192 ;
    END
  END o[547]
  PIN o[548]
    DIRECTION OUTPUT ;
    USE SIGNAL ;
    PORT
      LAYER M3 ;
        RECT  55.908 0 55.926 0.144 ;
    END
  END o[548]
  PIN o[549]
    DIRECTION OUTPUT ;
    USE SIGNAL ;
    PORT
      LAYER M5 ;
        RECT  56.016 0 56.04 0.192 ;
    END
  END o[549]
  PIN o[54]
    DIRECTION OUTPUT ;
    USE SIGNAL ;
    PORT
      LAYER M3 ;
        RECT  7.488 0 7.506 0.144 ;
    END
  END o[54]
  PIN o[550]
    DIRECTION OUTPUT ;
    USE SIGNAL ;
    PORT
      LAYER M3 ;
        RECT  56.124 0 56.142 0.144 ;
    END
  END o[550]
  PIN o[551]
    DIRECTION OUTPUT ;
    USE SIGNAL ;
    PORT
      LAYER M5 ;
        RECT  56.208 0 56.232 0.192 ;
    END
  END o[551]
  PIN o[552]
    DIRECTION OUTPUT ;
    USE SIGNAL ;
    PORT
      LAYER M3 ;
        RECT  56.304 0 56.322 0.144 ;
    END
  END o[552]
  PIN o[553]
    DIRECTION OUTPUT ;
    USE SIGNAL ;
    PORT
      LAYER M5 ;
        RECT  56.4 0 56.424 0.192 ;
    END
  END o[553]
  PIN o[554]
    DIRECTION OUTPUT ;
    USE SIGNAL ;
    PORT
      LAYER M3 ;
        RECT  56.52 0 56.538 0.144 ;
    END
  END o[554]
  PIN o[555]
    DIRECTION OUTPUT ;
    USE SIGNAL ;
    PORT
      LAYER M5 ;
        RECT  56.592 0 56.616 0.192 ;
    END
  END o[555]
  PIN o[556]
    DIRECTION OUTPUT ;
    USE SIGNAL ;
    PORT
      LAYER M3 ;
        RECT  56.7 0 56.718 0.144 ;
    END
  END o[556]
  PIN o[557]
    DIRECTION OUTPUT ;
    USE SIGNAL ;
    PORT
      LAYER M5 ;
        RECT  56.784 0 56.808 0.192 ;
    END
  END o[557]
  PIN o[558]
    DIRECTION OUTPUT ;
    USE SIGNAL ;
    PORT
      LAYER M3 ;
        RECT  56.916 0 56.934 0.144 ;
    END
  END o[558]
  PIN o[559]
    DIRECTION OUTPUT ;
    USE SIGNAL ;
    PORT
      LAYER M5 ;
        RECT  57.024 0 57.048 0.192 ;
    END
  END o[559]
  PIN o[55]
    DIRECTION OUTPUT ;
    USE SIGNAL ;
    PORT
      LAYER M5 ;
        RECT  7.584 0 7.608 0.192 ;
    END
  END o[55]
  PIN o[560]
    DIRECTION OUTPUT ;
    USE SIGNAL ;
    PORT
      LAYER M3 ;
        RECT  57.096 0 57.114 0.144 ;
    END
  END o[560]
  PIN o[561]
    DIRECTION OUTPUT ;
    USE SIGNAL ;
    PORT
      LAYER M5 ;
        RECT  57.216 0 57.24 0.192 ;
    END
  END o[561]
  PIN o[562]
    DIRECTION OUTPUT ;
    USE SIGNAL ;
    PORT
      LAYER M3 ;
        RECT  57.312 0 57.33 0.144 ;
    END
  END o[562]
  PIN o[563]
    DIRECTION OUTPUT ;
    USE SIGNAL ;
    PORT
      LAYER M5 ;
        RECT  57.408 0 57.432 0.192 ;
    END
  END o[563]
  PIN o[564]
    DIRECTION OUTPUT ;
    USE SIGNAL ;
    PORT
      LAYER M3 ;
        RECT  57.492 0 57.51 0.144 ;
    END
  END o[564]
  PIN o[565]
    DIRECTION OUTPUT ;
    USE SIGNAL ;
    PORT
      LAYER M5 ;
        RECT  57.6 0 57.624 0.192 ;
    END
  END o[565]
  PIN o[566]
    DIRECTION OUTPUT ;
    USE SIGNAL ;
    PORT
      LAYER M3 ;
        RECT  57.672 0 57.69 0.144 ;
    END
  END o[566]
  PIN o[567]
    DIRECTION OUTPUT ;
    USE SIGNAL ;
    PORT
      LAYER M5 ;
        RECT  57.792 0 57.816 0.192 ;
    END
  END o[567]
  PIN o[568]
    DIRECTION OUTPUT ;
    USE SIGNAL ;
    PORT
      LAYER M3 ;
        RECT  57.888 0 57.906 0.144 ;
    END
  END o[568]
  PIN o[569]
    DIRECTION OUTPUT ;
    USE SIGNAL ;
    PORT
      LAYER M5 ;
        RECT  57.984 0 58.008 0.192 ;
    END
  END o[569]
  PIN o[56]
    DIRECTION OUTPUT ;
    USE SIGNAL ;
    PORT
      LAYER M3 ;
        RECT  7.704 0 7.722 0.144 ;
    END
  END o[56]
  PIN o[570]
    DIRECTION OUTPUT ;
    USE SIGNAL ;
    PORT
      LAYER M3 ;
        RECT  58.068 0 58.086 0.144 ;
    END
  END o[570]
  PIN o[571]
    DIRECTION OUTPUT ;
    USE SIGNAL ;
    PORT
      LAYER M5 ;
        RECT  58.176 0 58.2 0.192 ;
    END
  END o[571]
  PIN o[572]
    DIRECTION OUTPUT ;
    USE SIGNAL ;
    PORT
      LAYER M3 ;
        RECT  58.284 0 58.302 0.144 ;
    END
  END o[572]
  PIN o[573]
    DIRECTION OUTPUT ;
    USE SIGNAL ;
    PORT
      LAYER M5 ;
        RECT  58.368 0 58.392 0.192 ;
    END
  END o[573]
  PIN o[574]
    DIRECTION OUTPUT ;
    USE SIGNAL ;
    PORT
      LAYER M3 ;
        RECT  58.464 0 58.482 0.144 ;
    END
  END o[574]
  PIN o[575]
    DIRECTION OUTPUT ;
    USE SIGNAL ;
    PORT
      LAYER M5 ;
        RECT  58.56 0 58.584 0.192 ;
    END
  END o[575]
  PIN o[576]
    DIRECTION OUTPUT ;
    USE SIGNAL ;
    PORT
      LAYER M3 ;
        RECT  58.68 0 58.698 0.144 ;
    END
  END o[576]
  PIN o[577]
    DIRECTION OUTPUT ;
    USE SIGNAL ;
    PORT
      LAYER M5 ;
        RECT  58.752 0 58.776 0.192 ;
    END
  END o[577]
  PIN o[578]
    DIRECTION OUTPUT ;
    USE SIGNAL ;
    PORT
      LAYER M3 ;
        RECT  58.86 0 58.878 0.144 ;
    END
  END o[578]
  PIN o[579]
    DIRECTION OUTPUT ;
    USE SIGNAL ;
    PORT
      LAYER M5 ;
        RECT  58.944 0 58.968 0.192 ;
    END
  END o[579]
  PIN o[57]
    DIRECTION OUTPUT ;
    USE SIGNAL ;
    PORT
      LAYER M5 ;
        RECT  7.776 0 7.8 0.192 ;
    END
  END o[57]
  PIN o[580]
    DIRECTION OUTPUT ;
    USE SIGNAL ;
    PORT
      LAYER M3 ;
        RECT  59.076 0 59.094 0.144 ;
    END
  END o[580]
  PIN o[581]
    DIRECTION OUTPUT ;
    USE SIGNAL ;
    PORT
      LAYER M5 ;
        RECT  59.136 0 59.16 0.192 ;
    END
  END o[581]
  PIN o[582]
    DIRECTION OUTPUT ;
    USE SIGNAL ;
    PORT
      LAYER M3 ;
        RECT  59.256 0 59.274 0.144 ;
    END
  END o[582]
  PIN o[583]
    DIRECTION OUTPUT ;
    USE SIGNAL ;
    PORT
      LAYER M5 ;
        RECT  59.376 0 59.4 0.192 ;
    END
  END o[583]
  PIN o[584]
    DIRECTION OUTPUT ;
    USE SIGNAL ;
    PORT
      LAYER M3 ;
        RECT  59.472 0 59.49 0.144 ;
    END
  END o[584]
  PIN o[585]
    DIRECTION OUTPUT ;
    USE SIGNAL ;
    PORT
      LAYER M5 ;
        RECT  59.568 0 59.592 0.192 ;
    END
  END o[585]
  PIN o[586]
    DIRECTION OUTPUT ;
    USE SIGNAL ;
    PORT
      LAYER M3 ;
        RECT  59.652 0 59.67 0.144 ;
    END
  END o[586]
  PIN o[587]
    DIRECTION OUTPUT ;
    USE SIGNAL ;
    PORT
      LAYER M5 ;
        RECT  59.76 0 59.784 0.192 ;
    END
  END o[587]
  PIN o[588]
    DIRECTION OUTPUT ;
    USE SIGNAL ;
    PORT
      LAYER M3 ;
        RECT  59.832 0 59.85 0.144 ;
    END
  END o[588]
  PIN o[589]
    DIRECTION OUTPUT ;
    USE SIGNAL ;
    PORT
      LAYER M5 ;
        RECT  59.952 0 59.976 0.192 ;
    END
  END o[589]
  PIN o[58]
    DIRECTION OUTPUT ;
    USE SIGNAL ;
    PORT
      LAYER M3 ;
        RECT  7.884 0 7.902 0.144 ;
    END
  END o[58]
  PIN o[590]
    DIRECTION OUTPUT ;
    USE SIGNAL ;
    PORT
      LAYER M3 ;
        RECT  60.048 0 60.066 0.144 ;
    END
  END o[590]
  PIN o[591]
    DIRECTION OUTPUT ;
    USE SIGNAL ;
    PORT
      LAYER M5 ;
        RECT  60.144 0 60.168 0.192 ;
    END
  END o[591]
  PIN o[592]
    DIRECTION OUTPUT ;
    USE SIGNAL ;
    PORT
      LAYER M3 ;
        RECT  60.228 0 60.246 0.144 ;
    END
  END o[592]
  PIN o[593]
    DIRECTION OUTPUT ;
    USE SIGNAL ;
    PORT
      LAYER M5 ;
        RECT  60.336 0 60.36 0.192 ;
    END
  END o[593]
  PIN o[594]
    DIRECTION OUTPUT ;
    USE SIGNAL ;
    PORT
      LAYER M3 ;
        RECT  60.444 0 60.462 0.144 ;
    END
  END o[594]
  PIN o[595]
    DIRECTION OUTPUT ;
    USE SIGNAL ;
    PORT
      LAYER M5 ;
        RECT  60.528 0 60.552 0.192 ;
    END
  END o[595]
  PIN o[596]
    DIRECTION OUTPUT ;
    USE SIGNAL ;
    PORT
      LAYER M3 ;
        RECT  60.624 0 60.642 0.144 ;
    END
  END o[596]
  PIN o[597]
    DIRECTION OUTPUT ;
    USE SIGNAL ;
    PORT
      LAYER M5 ;
        RECT  60.72 0 60.744 0.192 ;
    END
  END o[597]
  PIN o[598]
    DIRECTION OUTPUT ;
    USE SIGNAL ;
    PORT
      LAYER M3 ;
        RECT  60.84 0 60.858 0.144 ;
    END
  END o[598]
  PIN o[599]
    DIRECTION OUTPUT ;
    USE SIGNAL ;
    PORT
      LAYER M5 ;
        RECT  60.912 0 60.936 0.192 ;
    END
  END o[599]
  PIN o[59]
    DIRECTION OUTPUT ;
    USE SIGNAL ;
    PORT
      LAYER M5 ;
        RECT  7.968 0 7.992 0.192 ;
    END
  END o[59]
  PIN o[5]
    DIRECTION OUTPUT ;
    USE SIGNAL ;
    PORT
      LAYER M5 ;
        RECT  2.688 0 2.712 0.192 ;
    END
  END o[5]
  PIN o[600]
    DIRECTION OUTPUT ;
    USE SIGNAL ;
    PORT
      LAYER M3 ;
        RECT  61.02 0 61.038 0.144 ;
    END
  END o[600]
  PIN o[601]
    DIRECTION OUTPUT ;
    USE SIGNAL ;
    PORT
      LAYER M5 ;
        RECT  61.104 0 61.128 0.192 ;
    END
  END o[601]
  PIN o[602]
    DIRECTION OUTPUT ;
    USE SIGNAL ;
    PORT
      LAYER M3 ;
        RECT  61.236 0 61.254 0.144 ;
    END
  END o[602]
  PIN o[603]
    DIRECTION OUTPUT ;
    USE SIGNAL ;
    PORT
      LAYER M5 ;
        RECT  61.296 0 61.32 0.192 ;
    END
  END o[603]
  PIN o[604]
    DIRECTION OUTPUT ;
    USE SIGNAL ;
    PORT
      LAYER M3 ;
        RECT  61.416 0 61.434 0.144 ;
    END
  END o[604]
  PIN o[605]
    DIRECTION OUTPUT ;
    USE SIGNAL ;
    PORT
      LAYER M5 ;
        RECT  61.488 0 61.512 0.192 ;
    END
  END o[605]
  PIN o[606]
    DIRECTION OUTPUT ;
    USE SIGNAL ;
    PORT
      LAYER M3 ;
        RECT  61.596 0 61.614 0.144 ;
    END
  END o[606]
  PIN o[607]
    DIRECTION OUTPUT ;
    USE SIGNAL ;
    PORT
      LAYER M5 ;
        RECT  61.728 0 61.752 0.192 ;
    END
  END o[607]
  PIN o[608]
    DIRECTION OUTPUT ;
    USE SIGNAL ;
    PORT
      LAYER M3 ;
        RECT  61.812 0 61.83 0.144 ;
    END
  END o[608]
  PIN o[609]
    DIRECTION OUTPUT ;
    USE SIGNAL ;
    PORT
      LAYER M5 ;
        RECT  61.92 0 61.944 0.192 ;
    END
  END o[609]
  PIN o[60]
    DIRECTION OUTPUT ;
    USE SIGNAL ;
    PORT
      LAYER M3 ;
        RECT  8.1 0 8.118 0.144 ;
    END
  END o[60]
  PIN o[610]
    DIRECTION OUTPUT ;
    USE SIGNAL ;
    PORT
      LAYER M3 ;
        RECT  61.992 0 62.01 0.144 ;
    END
  END o[610]
  PIN o[611]
    DIRECTION OUTPUT ;
    USE SIGNAL ;
    PORT
      LAYER M5 ;
        RECT  62.112 0 62.136 0.192 ;
    END
  END o[611]
  PIN o[612]
    DIRECTION OUTPUT ;
    USE SIGNAL ;
    PORT
      LAYER M3 ;
        RECT  62.208 0 62.226 0.144 ;
    END
  END o[612]
  PIN o[613]
    DIRECTION OUTPUT ;
    USE SIGNAL ;
    PORT
      LAYER M5 ;
        RECT  62.304 0 62.328 0.192 ;
    END
  END o[613]
  PIN o[614]
    DIRECTION OUTPUT ;
    USE SIGNAL ;
    PORT
      LAYER M3 ;
        RECT  62.388 0 62.406 0.144 ;
    END
  END o[614]
  PIN o[615]
    DIRECTION OUTPUT ;
    USE SIGNAL ;
    PORT
      LAYER M5 ;
        RECT  62.496 0 62.52 0.192 ;
    END
  END o[615]
  PIN o[616]
    DIRECTION OUTPUT ;
    USE SIGNAL ;
    PORT
      LAYER M3 ;
        RECT  62.604 0 62.622 0.144 ;
    END
  END o[616]
  PIN o[617]
    DIRECTION OUTPUT ;
    USE SIGNAL ;
    PORT
      LAYER M5 ;
        RECT  62.688 0 62.712 0.192 ;
    END
  END o[617]
  PIN o[618]
    DIRECTION OUTPUT ;
    USE SIGNAL ;
    PORT
      LAYER M3 ;
        RECT  62.784 0 62.802 0.144 ;
    END
  END o[618]
  PIN o[619]
    DIRECTION OUTPUT ;
    USE SIGNAL ;
    PORT
      LAYER M5 ;
        RECT  62.88 0 62.904 0.192 ;
    END
  END o[619]
  PIN o[61]
    DIRECTION OUTPUT ;
    USE SIGNAL ;
    PORT
      LAYER M5 ;
        RECT  8.16 0 8.184 0.192 ;
    END
  END o[61]
  PIN o[620]
    DIRECTION OUTPUT ;
    USE SIGNAL ;
    PORT
      LAYER M3 ;
        RECT  63 0 63.018 0.144 ;
    END
  END o[620]
  PIN o[621]
    DIRECTION OUTPUT ;
    USE SIGNAL ;
    PORT
      LAYER M5 ;
        RECT  63.072 0 63.096 0.192 ;
    END
  END o[621]
  PIN o[622]
    DIRECTION OUTPUT ;
    USE SIGNAL ;
    PORT
      LAYER M3 ;
        RECT  63.18 0 63.198 0.144 ;
    END
  END o[622]
  PIN o[623]
    DIRECTION OUTPUT ;
    USE SIGNAL ;
    PORT
      LAYER M5 ;
        RECT  63.264 0 63.288 0.192 ;
    END
  END o[623]
  PIN o[624]
    DIRECTION OUTPUT ;
    USE SIGNAL ;
    PORT
      LAYER M3 ;
        RECT  63.36 0 63.378 0.144 ;
    END
  END o[624]
  PIN o[625]
    DIRECTION OUTPUT ;
    USE SIGNAL ;
    PORT
      LAYER M5 ;
        RECT  63.456 0 63.48 0.192 ;
    END
  END o[625]
  PIN o[626]
    DIRECTION OUTPUT ;
    USE SIGNAL ;
    PORT
      LAYER M3 ;
        RECT  63.576 0 63.594 0.144 ;
    END
  END o[626]
  PIN o[627]
    DIRECTION OUTPUT ;
    USE SIGNAL ;
    PORT
      LAYER M5 ;
        RECT  63.648 0 63.672 0.192 ;
    END
  END o[627]
  PIN o[628]
    DIRECTION OUTPUT ;
    USE SIGNAL ;
    PORT
      LAYER M3 ;
        RECT  63.756 0 63.774 0.144 ;
    END
  END o[628]
  PIN o[629]
    DIRECTION OUTPUT ;
    USE SIGNAL ;
    PORT
      LAYER M5 ;
        RECT  63.84 0 63.864 0.192 ;
    END
  END o[629]
  PIN o[62]
    DIRECTION OUTPUT ;
    USE SIGNAL ;
    PORT
      LAYER M3 ;
        RECT  8.28 0 8.298 0.144 ;
    END
  END o[62]
  PIN o[630]
    DIRECTION OUTPUT ;
    USE SIGNAL ;
    PORT
      LAYER M3 ;
        RECT  63.972 0 63.99 0.144 ;
    END
  END o[630]
  PIN o[631]
    DIRECTION OUTPUT ;
    USE SIGNAL ;
    PORT
      LAYER M5 ;
        RECT  64.08 0 64.104 0.192 ;
    END
  END o[631]
  PIN o[632]
    DIRECTION OUTPUT ;
    USE SIGNAL ;
    PORT
      LAYER M3 ;
        RECT  64.152 0 64.17 0.144 ;
    END
  END o[632]
  PIN o[633]
    DIRECTION OUTPUT ;
    USE SIGNAL ;
    PORT
      LAYER M5 ;
        RECT  64.272 0 64.296 0.192 ;
    END
  END o[633]
  PIN o[634]
    DIRECTION OUTPUT ;
    USE SIGNAL ;
    PORT
      LAYER M3 ;
        RECT  64.368 0 64.386 0.144 ;
    END
  END o[634]
  PIN o[635]
    DIRECTION OUTPUT ;
    USE SIGNAL ;
    PORT
      LAYER M5 ;
        RECT  64.464 0 64.488 0.192 ;
    END
  END o[635]
  PIN o[636]
    DIRECTION OUTPUT ;
    USE SIGNAL ;
    PORT
      LAYER M3 ;
        RECT  64.548 0 64.566 0.144 ;
    END
  END o[636]
  PIN o[637]
    DIRECTION OUTPUT ;
    USE SIGNAL ;
    PORT
      LAYER M5 ;
        RECT  64.656 0 64.68 0.192 ;
    END
  END o[637]
  PIN o[638]
    DIRECTION OUTPUT ;
    USE SIGNAL ;
    PORT
      LAYER M3 ;
        RECT  64.764 0 64.782 0.144 ;
    END
  END o[638]
  PIN o[639]
    DIRECTION OUTPUT ;
    USE SIGNAL ;
    PORT
      LAYER M5 ;
        RECT  64.848 0 64.872 0.192 ;
    END
  END o[639]
  PIN o[63]
    DIRECTION OUTPUT ;
    USE SIGNAL ;
    PORT
      LAYER M5 ;
        RECT  8.352 0 8.376 0.192 ;
    END
  END o[63]
  PIN o[640]
    DIRECTION OUTPUT ;
    USE SIGNAL ;
    PORT
      LAYER M3 ;
        RECT  64.944 0 64.962 0.144 ;
    END
  END o[640]
  PIN o[641]
    DIRECTION OUTPUT ;
    USE SIGNAL ;
    PORT
      LAYER M5 ;
        RECT  65.04 0 65.064 0.192 ;
    END
  END o[641]
  PIN o[642]
    DIRECTION OUTPUT ;
    USE SIGNAL ;
    PORT
      LAYER M3 ;
        RECT  65.124 0 65.142 0.144 ;
    END
  END o[642]
  PIN o[643]
    DIRECTION OUTPUT ;
    USE SIGNAL ;
    PORT
      LAYER M5 ;
        RECT  65.232 0 65.256 0.192 ;
    END
  END o[643]
  PIN o[644]
    DIRECTION OUTPUT ;
    USE SIGNAL ;
    PORT
      LAYER M3 ;
        RECT  65.34 0 65.358 0.144 ;
    END
  END o[644]
  PIN o[645]
    DIRECTION OUTPUT ;
    USE SIGNAL ;
    PORT
      LAYER M5 ;
        RECT  65.424 0 65.448 0.192 ;
    END
  END o[645]
  PIN o[646]
    DIRECTION OUTPUT ;
    USE SIGNAL ;
    PORT
      LAYER M3 ;
        RECT  65.52 0 65.538 0.144 ;
    END
  END o[646]
  PIN o[647]
    DIRECTION OUTPUT ;
    USE SIGNAL ;
    PORT
      LAYER M5 ;
        RECT  65.616 0 65.64 0.192 ;
    END
  END o[647]
  PIN o[648]
    DIRECTION OUTPUT ;
    USE SIGNAL ;
    PORT
      LAYER M3 ;
        RECT  65.736 0 65.754 0.144 ;
    END
  END o[648]
  PIN o[649]
    DIRECTION OUTPUT ;
    USE SIGNAL ;
    PORT
      LAYER M5 ;
        RECT  65.808 0 65.832 0.192 ;
    END
  END o[649]
  PIN o[64]
    DIRECTION OUTPUT ;
    USE SIGNAL ;
    PORT
      LAYER M3 ;
        RECT  8.46 0 8.478 0.144 ;
    END
  END o[64]
  PIN o[650]
    DIRECTION OUTPUT ;
    USE SIGNAL ;
    PORT
      LAYER M3 ;
        RECT  65.916 0 65.934 0.144 ;
    END
  END o[650]
  PIN o[651]
    DIRECTION OUTPUT ;
    USE SIGNAL ;
    PORT
      LAYER M5 ;
        RECT  66 0 66.024 0.192 ;
    END
  END o[651]
  PIN o[652]
    DIRECTION OUTPUT ;
    USE SIGNAL ;
    PORT
      LAYER M3 ;
        RECT  66.132 0 66.15 0.144 ;
    END
  END o[652]
  PIN o[653]
    DIRECTION OUTPUT ;
    USE SIGNAL ;
    PORT
      LAYER M5 ;
        RECT  66.192 0 66.216 0.192 ;
    END
  END o[653]
  PIN o[654]
    DIRECTION OUTPUT ;
    USE SIGNAL ;
    PORT
      LAYER M3 ;
        RECT  66.312 0 66.33 0.144 ;
    END
  END o[654]
  PIN o[655]
    DIRECTION OUTPUT ;
    USE SIGNAL ;
    PORT
      LAYER M5 ;
        RECT  66.432 0 66.456 0.192 ;
    END
  END o[655]
  PIN o[656]
    DIRECTION OUTPUT ;
    USE SIGNAL ;
    PORT
      LAYER M3 ;
        RECT  66.528 0 66.546 0.144 ;
    END
  END o[656]
  PIN o[657]
    DIRECTION OUTPUT ;
    USE SIGNAL ;
    PORT
      LAYER M5 ;
        RECT  66.624 0 66.648 0.192 ;
    END
  END o[657]
  PIN o[658]
    DIRECTION OUTPUT ;
    USE SIGNAL ;
    PORT
      LAYER M3 ;
        RECT  66.708 0 66.726 0.144 ;
    END
  END o[658]
  PIN o[659]
    DIRECTION OUTPUT ;
    USE SIGNAL ;
    PORT
      LAYER M5 ;
        RECT  66.816 0 66.84 0.192 ;
    END
  END o[659]
  PIN o[65]
    DIRECTION OUTPUT ;
    USE SIGNAL ;
    PORT
      LAYER M5 ;
        RECT  8.592 0 8.616 0.192 ;
    END
  END o[65]
  PIN o[660]
    DIRECTION OUTPUT ;
    USE SIGNAL ;
    PORT
      LAYER M3 ;
        RECT  66.888 0 66.906 0.144 ;
    END
  END o[660]
  PIN o[661]
    DIRECTION OUTPUT ;
    USE SIGNAL ;
    PORT
      LAYER M5 ;
        RECT  67.008 0 67.032 0.192 ;
    END
  END o[661]
  PIN o[662]
    DIRECTION OUTPUT ;
    USE SIGNAL ;
    PORT
      LAYER M3 ;
        RECT  67.104 0 67.122 0.144 ;
    END
  END o[662]
  PIN o[663]
    DIRECTION OUTPUT ;
    USE SIGNAL ;
    PORT
      LAYER M5 ;
        RECT  67.2 0 67.224 0.192 ;
    END
  END o[663]
  PIN o[664]
    DIRECTION OUTPUT ;
    USE SIGNAL ;
    PORT
      LAYER M3 ;
        RECT  67.284 0 67.302 0.144 ;
    END
  END o[664]
  PIN o[665]
    DIRECTION OUTPUT ;
    USE SIGNAL ;
    PORT
      LAYER M5 ;
        RECT  67.392 0 67.416 0.192 ;
    END
  END o[665]
  PIN o[666]
    DIRECTION OUTPUT ;
    USE SIGNAL ;
    PORT
      LAYER M3 ;
        RECT  67.5 0 67.518 0.144 ;
    END
  END o[666]
  PIN o[667]
    DIRECTION OUTPUT ;
    USE SIGNAL ;
    PORT
      LAYER M5 ;
        RECT  67.584 0 67.608 0.192 ;
    END
  END o[667]
  PIN o[668]
    DIRECTION OUTPUT ;
    USE SIGNAL ;
    PORT
      LAYER M3 ;
        RECT  67.68 0 67.698 0.144 ;
    END
  END o[668]
  PIN o[669]
    DIRECTION OUTPUT ;
    USE SIGNAL ;
    PORT
      LAYER M5 ;
        RECT  67.776 0 67.8 0.192 ;
    END
  END o[669]
  PIN o[66]
    DIRECTION OUTPUT ;
    USE SIGNAL ;
    PORT
      LAYER M3 ;
        RECT  8.676 0 8.694 0.144 ;
    END
  END o[66]
  PIN o[670]
    DIRECTION OUTPUT ;
    USE SIGNAL ;
    PORT
      LAYER M3 ;
        RECT  67.896 0 67.914 0.144 ;
    END
  END o[670]
  PIN o[671]
    DIRECTION OUTPUT ;
    USE SIGNAL ;
    PORT
      LAYER M5 ;
        RECT  67.968 0 67.992 0.192 ;
    END
  END o[671]
  PIN o[672]
    DIRECTION OUTPUT ;
    USE SIGNAL ;
    PORT
      LAYER M3 ;
        RECT  68.076 0 68.094 0.144 ;
    END
  END o[672]
  PIN o[673]
    DIRECTION OUTPUT ;
    USE SIGNAL ;
    PORT
      LAYER M5 ;
        RECT  68.16 0 68.184 0.192 ;
    END
  END o[673]
  PIN o[674]
    DIRECTION OUTPUT ;
    USE SIGNAL ;
    PORT
      LAYER M3 ;
        RECT  68.292 0 68.31 0.144 ;
    END
  END o[674]
  PIN o[675]
    DIRECTION OUTPUT ;
    USE SIGNAL ;
    PORT
      LAYER M5 ;
        RECT  68.352 0 68.376 0.192 ;
    END
  END o[675]
  PIN o[676]
    DIRECTION OUTPUT ;
    USE SIGNAL ;
    PORT
      LAYER M3 ;
        RECT  68.472 0 68.49 0.144 ;
    END
  END o[676]
  PIN o[677]
    DIRECTION OUTPUT ;
    USE SIGNAL ;
    PORT
      LAYER M5 ;
        RECT  68.592 0 68.616 0.192 ;
    END
  END o[677]
  PIN o[678]
    DIRECTION OUTPUT ;
    USE SIGNAL ;
    PORT
      LAYER M3 ;
        RECT  68.652 0 68.67 0.144 ;
    END
  END o[678]
  PIN o[679]
    DIRECTION OUTPUT ;
    USE SIGNAL ;
    PORT
      LAYER M5 ;
        RECT  68.784 0 68.808 0.192 ;
    END
  END o[679]
  PIN o[67]
    DIRECTION OUTPUT ;
    USE SIGNAL ;
    PORT
      LAYER M5 ;
        RECT  8.784 0 8.808 0.192 ;
    END
  END o[67]
  PIN o[680]
    DIRECTION OUTPUT ;
    USE SIGNAL ;
    PORT
      LAYER M3 ;
        RECT  68.868 0 68.886 0.144 ;
    END
  END o[680]
  PIN o[681]
    DIRECTION OUTPUT ;
    USE SIGNAL ;
    PORT
      LAYER M5 ;
        RECT  68.976 0 69 0.192 ;
    END
  END o[681]
  PIN o[68]
    DIRECTION OUTPUT ;
    USE SIGNAL ;
    PORT
      LAYER M3 ;
        RECT  8.856 0 8.874 0.144 ;
    END
  END o[68]
  PIN o[69]
    DIRECTION OUTPUT ;
    USE SIGNAL ;
    PORT
      LAYER M5 ;
        RECT  8.976 0 9 0.192 ;
    END
  END o[69]
  PIN o[6]
    DIRECTION OUTPUT ;
    USE SIGNAL ;
    PORT
      LAYER M3 ;
        RECT  2.772 0 2.79 0.144 ;
    END
  END o[6]
  PIN o[70]
    DIRECTION OUTPUT ;
    USE SIGNAL ;
    PORT
      LAYER M3 ;
        RECT  9.072 0 9.09 0.144 ;
    END
  END o[70]
  PIN o[71]
    DIRECTION OUTPUT ;
    USE SIGNAL ;
    PORT
      LAYER M5 ;
        RECT  9.168 0 9.192 0.192 ;
    END
  END o[71]
  PIN o[72]
    DIRECTION OUTPUT ;
    USE SIGNAL ;
    PORT
      LAYER M3 ;
        RECT  9.252 0 9.27 0.144 ;
    END
  END o[72]
  PIN o[73]
    DIRECTION OUTPUT ;
    USE SIGNAL ;
    PORT
      LAYER M5 ;
        RECT  9.36 0 9.384 0.192 ;
    END
  END o[73]
  PIN o[74]
    DIRECTION OUTPUT ;
    USE SIGNAL ;
    PORT
      LAYER M3 ;
        RECT  9.468 0 9.486 0.144 ;
    END
  END o[74]
  PIN o[75]
    DIRECTION OUTPUT ;
    USE SIGNAL ;
    PORT
      LAYER M5 ;
        RECT  9.552 0 9.576 0.192 ;
    END
  END o[75]
  PIN o[76]
    DIRECTION OUTPUT ;
    USE SIGNAL ;
    PORT
      LAYER M3 ;
        RECT  9.648 0 9.666 0.144 ;
    END
  END o[76]
  PIN o[77]
    DIRECTION OUTPUT ;
    USE SIGNAL ;
    PORT
      LAYER M5 ;
        RECT  9.744 0 9.768 0.192 ;
    END
  END o[77]
  PIN o[78]
    DIRECTION OUTPUT ;
    USE SIGNAL ;
    PORT
      LAYER M3 ;
        RECT  9.864 0 9.882 0.144 ;
    END
  END o[78]
  PIN o[79]
    DIRECTION OUTPUT ;
    USE SIGNAL ;
    PORT
      LAYER M5 ;
        RECT  9.936 0 9.96 0.192 ;
    END
  END o[79]
  PIN o[7]
    DIRECTION OUTPUT ;
    USE SIGNAL ;
    PORT
      LAYER M5 ;
        RECT  2.88 0 2.904 0.192 ;
    END
  END o[7]
  PIN o[80]
    DIRECTION OUTPUT ;
    USE SIGNAL ;
    PORT
      LAYER M3 ;
        RECT  10.044 0 10.062 0.144 ;
    END
  END o[80]
  PIN o[81]
    DIRECTION OUTPUT ;
    USE SIGNAL ;
    PORT
      LAYER M5 ;
        RECT  10.128 0 10.152 0.192 ;
    END
  END o[81]
  PIN o[82]
    DIRECTION OUTPUT ;
    USE SIGNAL ;
    PORT
      LAYER M3 ;
        RECT  10.224 0 10.242 0.144 ;
    END
  END o[82]
  PIN o[83]
    DIRECTION OUTPUT ;
    USE SIGNAL ;
    PORT
      LAYER M5 ;
        RECT  10.32 0 10.344 0.192 ;
    END
  END o[83]
  PIN o[84]
    DIRECTION OUTPUT ;
    USE SIGNAL ;
    PORT
      LAYER M3 ;
        RECT  10.44 0 10.458 0.144 ;
    END
  END o[84]
  PIN o[85]
    DIRECTION OUTPUT ;
    USE SIGNAL ;
    PORT
      LAYER M5 ;
        RECT  10.512 0 10.536 0.192 ;
    END
  END o[85]
  PIN o[86]
    DIRECTION OUTPUT ;
    USE SIGNAL ;
    PORT
      LAYER M3 ;
        RECT  10.62 0 10.638 0.144 ;
    END
  END o[86]
  PIN o[87]
    DIRECTION OUTPUT ;
    USE SIGNAL ;
    PORT
      LAYER M5 ;
        RECT  10.704 0 10.728 0.192 ;
    END
  END o[87]
  PIN o[88]
    DIRECTION OUTPUT ;
    USE SIGNAL ;
    PORT
      LAYER M3 ;
        RECT  10.836 0 10.854 0.144 ;
    END
  END o[88]
  PIN o[89]
    DIRECTION OUTPUT ;
    USE SIGNAL ;
    PORT
      LAYER M5 ;
        RECT  10.944 0 10.968 0.192 ;
    END
  END o[89]
  PIN o[8]
    DIRECTION OUTPUT ;
    USE SIGNAL ;
    PORT
      LAYER M3 ;
        RECT  2.988 0 3.006 0.144 ;
    END
  END o[8]
  PIN o[90]
    DIRECTION OUTPUT ;
    USE SIGNAL ;
    PORT
      LAYER M3 ;
        RECT  11.016 0 11.034 0.144 ;
    END
  END o[90]
  PIN o[91]
    DIRECTION OUTPUT ;
    USE SIGNAL ;
    PORT
      LAYER M5 ;
        RECT  11.136 0 11.16 0.192 ;
    END
  END o[91]
  PIN o[92]
    DIRECTION OUTPUT ;
    USE SIGNAL ;
    PORT
      LAYER M3 ;
        RECT  11.232 0 11.25 0.144 ;
    END
  END o[92]
  PIN o[93]
    DIRECTION OUTPUT ;
    USE SIGNAL ;
    PORT
      LAYER M5 ;
        RECT  11.328 0 11.352 0.192 ;
    END
  END o[93]
  PIN o[94]
    DIRECTION OUTPUT ;
    USE SIGNAL ;
    PORT
      LAYER M3 ;
        RECT  11.412 0 11.43 0.144 ;
    END
  END o[94]
  PIN o[95]
    DIRECTION OUTPUT ;
    USE SIGNAL ;
    PORT
      LAYER M5 ;
        RECT  11.52 0 11.544 0.192 ;
    END
  END o[95]
  PIN o[96]
    DIRECTION OUTPUT ;
    USE SIGNAL ;
    PORT
      LAYER M3 ;
        RECT  11.628 0 11.646 0.144 ;
    END
  END o[96]
  PIN o[97]
    DIRECTION OUTPUT ;
    USE SIGNAL ;
    PORT
      LAYER M5 ;
        RECT  11.712 0 11.736 0.192 ;
    END
  END o[97]
  PIN o[98]
    DIRECTION OUTPUT ;
    USE SIGNAL ;
    PORT
      LAYER M3 ;
        RECT  11.808 0 11.826 0.144 ;
    END
  END o[98]
  PIN o[99]
    DIRECTION OUTPUT ;
    USE SIGNAL ;
    PORT
      LAYER M5 ;
        RECT  11.904 0 11.928 0.192 ;
    END
  END o[99]
  PIN o[9]
    DIRECTION OUTPUT ;
    USE SIGNAL ;
    PORT
      LAYER M5 ;
        RECT  3.072 0 3.096 0.192 ;
    END
  END o[9]
  PIN rs
    DIRECTION INPUT ;
    USE SIGNAL ;
    PORT
      LAYER M4 ;
        RECT  71.088 11.904 71.28 11.928 ;
    END
  END rs
  PIN VDD
    DIRECTION INOUT ;
    USE POWER ;
    PORT
      LAYER M5 ;
        RECT  67.392 2.151 67.512 15.129 ;
        RECT  64.692 2.151 64.812 15.129 ;
        RECT  61.992 2.151 62.112 15.129 ;
        RECT  59.292 2.151 59.412 15.129 ;
        RECT  56.592 2.151 56.712 15.129 ;
        RECT  53.892 2.151 54.012 15.129 ;
        RECT  51.192 2.151 51.312 15.129 ;
        RECT  48.492 2.151 48.612 15.129 ;
        RECT  45.792 2.151 45.912 15.129 ;
        RECT  43.092 2.151 43.212 15.129 ;
        RECT  40.392 2.151 40.512 15.129 ;
        RECT  37.692 2.151 37.812 15.129 ;
        RECT  34.992 2.151 35.112 15.129 ;
        RECT  32.292 2.151 32.412 15.129 ;
        RECT  29.592 2.151 29.712 15.129 ;
        RECT  26.892 2.151 27.012 15.129 ;
        RECT  24.192 2.151 24.312 15.129 ;
        RECT  21.492 2.151 21.612 15.129 ;
        RECT  18.792 2.151 18.912 15.129 ;
        RECT  16.092 2.151 16.212 15.129 ;
        RECT  13.392 2.151 13.512 15.129 ;
        RECT  10.692 2.151 10.812 15.129 ;
        RECT  7.992 2.151 8.112 15.129 ;
        RECT  5.292 2.151 5.412 15.129 ;
        RECT  2.592 2.151 2.712 15.129 ;
    END
  END VDD
  PIN VSS
    DIRECTION INOUT ;
    USE GROUND ;
    PORT
      LAYER M5 ;
        RECT  67.2 2.137 67.32 15.143 ;
        RECT  64.5 2.137 64.62 15.143 ;
        RECT  61.8 2.137 61.92 15.143 ;
        RECT  59.1 2.137 59.22 15.143 ;
        RECT  56.4 2.137 56.52 15.143 ;
        RECT  53.7 2.137 53.82 15.143 ;
        RECT  51 2.137 51.12 15.143 ;
        RECT  48.3 2.137 48.42 15.143 ;
        RECT  45.6 2.137 45.72 15.143 ;
        RECT  42.9 2.137 43.02 15.143 ;
        RECT  40.2 2.137 40.32 15.143 ;
        RECT  37.5 2.137 37.62 15.143 ;
        RECT  34.8 2.137 34.92 15.143 ;
        RECT  32.1 2.137 32.22 15.143 ;
        RECT  29.4 2.137 29.52 15.143 ;
        RECT  26.7 2.137 26.82 15.143 ;
        RECT  24 2.137 24.12 15.143 ;
        RECT  21.3 2.137 21.42 15.143 ;
        RECT  18.6 2.137 18.72 15.143 ;
        RECT  15.9 2.137 16.02 15.143 ;
        RECT  13.2 2.137 13.32 15.143 ;
        RECT  10.5 2.137 10.62 15.143 ;
        RECT  7.8 2.137 7.92 15.143 ;
        RECT  5.1 2.137 5.22 15.143 ;
        RECT  2.4 2.137 2.52 15.143 ;
    END
  END VSS
  OBS
    LAYER RVTN ;
     RECT  2.16 2.16 69.12 2.295 ;
     RECT  2.16 2.565 69.12 2.835 ;
     RECT  2.16 3.105 69.12 3.375 ;
     RECT  2.16 3.645 69.12 3.915 ;
     RECT  2.16 4.185 69.12 4.455 ;
     RECT  2.16 4.725 69.12 4.995 ;
     RECT  2.16 5.265 69.12 5.535 ;
     RECT  2.16 5.805 69.12 6.075 ;
     RECT  2.16 6.345 69.12 6.615 ;
     RECT  2.16 6.885 69.12 7.155 ;
     RECT  2.16 7.425 69.12 7.695 ;
     RECT  2.16 7.965 69.12 8.235 ;
     RECT  2.16 8.505 69.12 8.775 ;
     RECT  2.16 9.045 69.12 9.315 ;
     RECT  2.16 9.585 69.12 9.855 ;
     RECT  2.16 10.125 69.12 10.395 ;
     RECT  2.16 10.665 69.12 10.935 ;
     RECT  2.16 11.205 69.12 11.475 ;
     RECT  2.16 11.745 69.12 12.015 ;
     RECT  2.16 12.285 69.12 12.555 ;
     RECT  2.16 12.825 69.12 13.095 ;
     RECT  2.16 13.365 69.12 13.635 ;
     RECT  2.16 13.905 69.12 14.175 ;
     RECT  2.16 14.445 69.12 14.715 ;
     RECT  2.16 14.985 69.12 15.12 ;
    LAYER RVTP ;
     RECT  2.16 2.295 69.12 2.565 ;
     RECT  2.16 2.835 69.12 3.105 ;
     RECT  2.16 3.375 69.12 3.645 ;
     RECT  2.16 3.915 69.12 4.185 ;
     RECT  2.16 4.455 69.12 4.725 ;
     RECT  2.16 4.995 69.12 5.265 ;
     RECT  2.16 5.535 69.12 5.805 ;
     RECT  2.16 6.075 69.12 6.345 ;
     RECT  2.16 6.615 69.12 6.885 ;
     RECT  2.16 7.155 69.12 7.425 ;
     RECT  2.16 7.695 69.12 7.965 ;
     RECT  2.16 8.235 69.12 8.505 ;
     RECT  2.16 8.775 69.12 9.045 ;
     RECT  2.16 9.315 69.12 9.585 ;
     RECT  2.16 9.855 69.12 10.125 ;
     RECT  2.16 10.395 69.12 10.665 ;
     RECT  2.16 10.935 69.12 11.205 ;
     RECT  2.16 11.475 69.12 11.745 ;
     RECT  2.16 12.015 69.12 12.285 ;
     RECT  2.16 12.555 69.12 12.825 ;
     RECT  2.16 13.095 69.12 13.365 ;
     RECT  2.16 13.635 69.12 13.905 ;
     RECT  2.16 14.175 69.12 14.445 ;
     RECT  2.16 14.715 69.12 14.985 ;
    LAYER M1 ;
     RECT  2.16 2.151 69.12 15.129 ;
    LAYER M2 ;
     RECT  2.16 2.151 2.407 15.129 ;
     RECT  2.407 2.151 2.579 15.21 ;
     RECT  2.407 0.144 2.587 0.162 ;
     RECT  2.587 0.144 2.795 0.234 ;
     RECT  2.579 2.151 3.559 15.129 ;
     RECT  3.559 1.728 3.839 15.129 ;
     RECT  3.839 2.151 3.883 15.129 ;
     RECT  2.795 0.144 3.911 0.162 ;
     RECT  3.883 2.151 3.983 15.174 ;
     RECT  3.983 2.151 5.143 15.129 ;
     RECT  5.143 1.8 5.179 15.21 ;
     RECT  5.179 1.728 5.539 15.21 ;
     RECT  5.539 1.728 5.675 15.282 ;
     RECT  4.927 0.144 5.819 0.162 ;
     RECT  5.675 1.728 5.999 15.129 ;
     RECT  5.999 2.034 7.483 15.129 ;
     RECT  7.483 1.728 7.627 15.129 ;
     RECT  7.627 1.728 7.727 15.21 ;
     RECT  7.727 2.034 7.907 15.21 ;
     RECT  7.907 2.034 8.519 15.174 ;
     RECT  7.303 0.144 9.023 0.162 ;
     RECT  8.519 2.034 9.643 15.129 ;
     RECT  9.643 1.962 10.355 15.174 ;
     RECT  10.355 1.962 10.751 15.129 ;
     RECT  10.111 0.144 11.111 0.162 ;
     RECT  10.751 2.034 11.623 15.129 ;
     RECT  11.623 1.728 12.911 15.129 ;
     RECT  12.911 1.926 13.127 15.129 ;
     RECT  13.127 1.962 13.207 15.129 ;
     RECT  13.207 1.962 13.379 15.21 ;
     RECT  13.379 1.962 13.703 15.129 ;
     RECT  12.199 0.144 13.955 0.162 ;
     RECT  13.703 2.034 14.971 15.129 ;
     RECT  14.971 2.034 15.619 15.174 ;
     RECT  15.619 2.034 15.719 15.21 ;
     RECT  15.763 0.144 16.303 0.162 ;
     RECT  15.719 2.106 16.339 15.21 ;
     RECT  16.339 2.106 16.367 15.246 ;
     RECT  16.303 0.144 16.403 0.234 ;
     RECT  16.367 2.151 16.439 15.246 ;
     RECT  16.403 0.216 16.475 0.234 ;
     RECT  16.439 2.151 17.311 15.174 ;
     RECT  17.275 0.144 17.411 0.162 ;
     RECT  17.311 2.151 17.707 15.21 ;
     RECT  17.707 2.151 18.203 15.246 ;
     RECT  18.283 0.144 18.383 0.162 ;
     RECT  18.463 17.19 18.499 17.208 ;
     RECT  18.499 17.118 18.599 17.208 ;
     RECT  18.203 2.151 18.679 15.21 ;
     RECT  18.679 2.07 18.815 15.21 ;
     RECT  18.815 2.07 19.211 15.174 ;
     RECT  19.255 0.144 19.355 0.162 ;
     RECT  19.211 2.07 19.651 15.129 ;
     RECT  19.651 2.034 20.047 15.129 ;
     RECT  20.227 0.144 20.327 0.162 ;
     RECT  18.859 1.152 20.795 1.17 ;
     RECT  20.047 1.962 20.839 15.129 ;
     RECT  20.803 17.19 20.839 17.208 ;
     RECT  20.839 17.118 21.119 17.208 ;
     RECT  20.839 1.728 21.515 15.129 ;
     RECT  21.515 2.034 21.919 15.129 ;
     RECT  21.919 2.034 22.523 15.174 ;
     RECT  21.163 0.144 22.559 0.162 ;
     RECT  22.523 2.106 22.811 15.174 ;
     RECT  22.811 2.106 23.603 15.129 ;
     RECT  23.603 2.151 24.007 15.129 ;
     RECT  23.359 0.144 24.151 0.162 ;
     RECT  24.007 2.151 24.367 15.21 ;
     RECT  24.151 0.144 24.395 0.324 ;
     RECT  24.367 2.151 24.467 15.282 ;
     RECT  24.467 2.151 24.727 15.129 ;
     RECT  24.727 2.106 25.547 15.129 ;
     RECT  24.395 0.144 25.735 0.162 ;
     RECT  25.547 2.151 25.771 15.129 ;
     RECT  25.735 0.144 25.943 0.324 ;
     RECT  25.771 2.151 26.275 15.174 ;
     RECT  26.275 2.106 26.671 15.174 ;
     RECT  26.671 2.106 26.707 15.246 ;
     RECT  26.707 2.07 26.771 15.246 ;
     RECT  25.943 0.144 27.059 0.162 ;
     RECT  26.771 2.07 27.679 15.129 ;
     RECT  27.175 1.152 27.923 1.17 ;
     RECT  27.679 1.926 28.651 15.129 ;
     RECT  28.651 1.728 28.751 15.129 ;
     RECT  28.751 1.836 29.263 15.129 ;
     RECT  29.263 1.836 29.551 15.21 ;
     RECT  29.443 0.144 29.695 0.162 ;
     RECT  29.695 0.144 29.867 0.198 ;
     RECT  29.551 1.836 30.155 15.246 ;
     RECT  29.867 0.144 30.191 0.162 ;
     RECT  30.155 1.881 30.191 15.246 ;
     RECT  30.191 1.881 31.055 15.174 ;
     RECT  31.027 0.144 31.063 0.162 ;
     RECT  31.063 0.144 31.235 0.198 ;
     RECT  31.055 2.034 31.595 15.129 ;
     RECT  31.595 2.106 32.395 15.129 ;
     RECT  31.235 0.144 32.999 0.162 ;
     RECT  32.395 1.728 33.187 15.129 ;
     RECT  33.187 1.152 33.323 15.129 ;
     RECT  33.323 1.728 34.807 15.129 ;
     RECT  33.943 0.144 35.347 0.162 ;
     RECT  34.807 1.728 35.383 15.21 ;
     RECT  35.383 1.728 35.483 15.282 ;
     RECT  35.347 0.144 35.519 0.234 ;
     RECT  35.519 0.144 35.735 0.198 ;
     RECT  35.735 0.144 35.771 0.162 ;
     RECT  35.483 1.728 36.491 15.129 ;
     RECT  36.535 17.19 36.571 17.208 ;
     RECT  36.571 17.118 36.671 17.208 ;
     RECT  36.491 2.106 36.715 15.129 ;
     RECT  36.499 0.144 37.031 0.162 ;
     RECT  36.715 2.106 37.291 15.174 ;
     RECT  37.291 2.034 37.471 15.174 ;
     RECT  37.471 2.034 37.571 15.21 ;
     RECT  37.571 2.034 37.687 15.174 ;
     RECT  37.687 1.728 37.895 15.174 ;
     RECT  37.895 1.728 38.479 15.129 ;
     RECT  38.263 0.144 39.119 0.162 ;
     RECT  38.479 1.422 39.163 15.129 ;
     RECT  40.063 17.19 40.099 17.208 ;
     RECT  40.099 0.216 40.135 0.234 ;
     RECT  39.163 1.422 40.135 15.174 ;
     RECT  40.099 17.118 40.199 17.208 ;
     RECT  40.135 0.144 40.271 0.234 ;
     RECT  40.135 1.422 40.307 15.21 ;
     RECT  40.271 0.216 40.451 0.234 ;
     RECT  40.307 1.422 40.739 15.174 ;
     RECT  40.739 1.422 41.495 15.129 ;
     RECT  41.495 1.962 41.927 15.129 ;
     RECT  41.927 1.998 42.539 15.129 ;
     RECT  41.215 0.144 43.159 0.162 ;
     RECT  43.159 17.118 43.259 17.208 ;
     RECT  43.159 0.144 43.295 0.198 ;
     RECT  43.259 17.19 43.295 17.208 ;
     RECT  43.295 0.144 44.015 0.162 ;
     RECT  42.539 2.151 44.887 15.129 ;
     RECT  44.023 16.542 44.951 16.56 ;
     RECT  45.319 0.144 45.391 0.162 ;
     RECT  45.391 0.144 45.563 0.234 ;
     RECT  44.887 2.106 45.607 15.129 ;
     RECT  45.607 2.106 45.959 15.21 ;
     RECT  45.563 0.144 45.995 0.162 ;
     RECT  45.959 2.106 46.507 15.129 ;
     RECT  46.507 2.07 47.299 15.129 ;
     RECT  47.299 1.998 47.479 15.129 ;
     RECT  47.479 1.926 47.695 15.129 ;
     RECT  47.695 1.881 48.199 15.129 ;
     RECT  48.199 1.881 48.271 15.21 ;
     RECT  48.271 1.728 48.371 15.21 ;
     RECT  48.371 1.728 49.711 15.129 ;
     RECT  47.875 0.144 49.927 0.162 ;
     RECT  49.711 1.728 50.027 15.174 ;
     RECT  50.027 2.034 50.503 15.174 ;
     RECT  50.503 2.034 50.863 15.21 ;
     RECT  50.863 2.034 51.107 15.246 ;
     RECT  51.107 2.034 51.179 15.129 ;
     RECT  49.927 0.144 51.403 0.234 ;
     RECT  51.179 2.151 52.375 15.129 ;
     RECT  52.375 2.106 52.943 15.129 ;
     RECT  51.403 0.144 53.015 0.864 ;
     RECT  53.015 0.846 53.779 0.864 ;
     RECT  52.943 2.151 54.031 15.129 ;
     RECT  54.031 2.106 54.067 15.129 ;
     RECT  53.779 0.144 54.239 0.864 ;
     RECT  54.067 2.07 54.455 15.129 ;
     RECT  54.535 17.118 54.635 17.208 ;
     RECT  54.635 17.19 54.671 17.208 ;
     RECT  54.455 2.106 54.851 15.129 ;
     RECT  54.239 0.846 54.923 0.864 ;
     RECT  54.851 2.151 55.435 15.129 ;
     RECT  56.155 17.19 56.191 17.208 ;
     RECT  56.191 17.118 56.291 17.208 ;
     RECT  55.435 2.151 56.299 15.174 ;
     RECT  56.299 2.151 56.435 15.21 ;
     RECT  55.543 0.144 57.515 0.162 ;
     RECT  56.435 2.151 57.667 15.129 ;
     RECT  57.667 1.728 58.055 15.129 ;
     RECT  58.135 17.19 58.171 17.208 ;
     RECT  58.171 17.118 58.271 17.208 ;
     RECT  58.819 0.216 58.855 0.234 ;
     RECT  58.855 0.144 58.891 0.234 ;
     RECT  58.055 2.034 59.071 15.129 ;
     RECT  59.071 2.034 59.171 15.21 ;
     RECT  58.891 0.144 59.279 0.279 ;
     RECT  59.171 2.034 59.467 15.129 ;
     RECT  59.467 1.962 60.287 15.129 ;
     RECT  59.279 0.144 60.395 0.162 ;
     RECT  60.287 2.106 60.511 15.129 ;
     RECT  60.511 2.106 61.735 15.174 ;
     RECT  61.735 2.106 61.807 15.21 ;
     RECT  61.807 1.998 61.907 15.21 ;
     RECT  61.907 1.998 62.383 15.174 ;
     RECT  62.383 1.962 62.995 15.174 ;
     RECT  62.995 1.728 63.167 15.174 ;
     RECT  61.771 0.144 63.203 0.162 ;
     RECT  63.167 2.07 63.635 15.174 ;
     RECT  63.635 2.07 64.031 15.129 ;
     RECT  63.967 0.144 64.039 0.162 ;
     RECT  64.039 0.144 64.471 0.198 ;
     RECT  64.031 2.106 64.931 15.129 ;
     RECT  64.471 0.144 65.219 0.234 ;
     RECT  64.931 2.151 65.407 15.129 ;
     RECT  65.407 2.151 66.019 15.174 ;
     RECT  66.019 2.106 66.127 15.174 ;
     RECT  66.127 1.998 66.263 15.174 ;
     RECT  66.263 1.998 66.523 15.129 ;
     RECT  65.335 0.576 66.587 0.594 ;
     RECT  66.523 1.881 67.387 15.129 ;
     RECT  67.387 1.881 67.415 15.174 ;
     RECT  67.279 0.144 67.495 0.162 ;
     RECT  67.495 0.144 67.667 0.234 ;
     RECT  67.415 1.998 67.811 15.174 ;
     RECT  68.107 16.686 68.207 16.704 ;
     RECT  67.811 1.998 68.387 15.129 ;
     RECT  68.387 2.034 68.639 15.129 ;
     RECT  68.359 16.542 68.639 16.56 ;
     RECT  67.667 0.144 68.927 0.162 ;
     RECT  68.639 2.151 69.12 15.129 ;
     RECT  69.12 3.888 69.143 3.906 ;
     RECT  69.12 11.646 69.143 15.084 ;
     RECT  69.12 5.778 69.179 6.84 ;
     RECT  69.143 12.726 69.179 15.084 ;
     RECT  69.179 5.886 69.215 6.84 ;
     RECT  69.179 12.726 69.215 13.284 ;
     RECT  69.12 2.808 69.251 3.132 ;
     RECT  69.179 14.346 69.251 15.084 ;
     RECT  69.215 6.282 69.287 6.84 ;
     RECT  69.143 11.646 69.287 11.664 ;
     RECT  69.251 2.808 69.323 2.826 ;
     RECT  69.215 12.726 69.323 12.744 ;
     RECT  69.287 6.822 69.359 6.84 ;
     RECT  69.12 7.974 69.359 8.064 ;
     RECT  69.251 15.066 69.359 15.084 ;
     RECT  69.12 8.946 69.575 8.964 ;
    LAYER M3 ;
     RECT  2.196 0.108 69.066 0.173 ;
     RECT  2.196 0.173 69.03 2.803 ;
     RECT  2.196 2.803 69.318 4.649 ;
     RECT  36.576 4.649 69.318 5.261 ;
     RECT  2.196 4.649 35.838 5.611 ;
     RECT  36.576 5.261 57.762 5.611 ;
     RECT  2.196 5.611 57.762 6.691 ;
     RECT  58.572 5.261 69.318 6.691 ;
     RECT  2.196 6.691 69.318 6.817 ;
     RECT  2.196 6.817 69.354 8.941 ;
     RECT  2.196 8.941 69.57 9.509 ;
     RECT  2.415 9.509 69.57 11.371 ;
     RECT  2.376 11.371 69.57 11.509 ;
     RECT  2.34 11.509 69.57 11.785 ;
     RECT  2.196 11.785 69.57 11.933 ;
     RECT  2.196 11.933 69.354 15.089 ;
     RECT  2.196 15.089 69.102 16.589 ;
     RECT  2.196 16.589 68.994 17.148 ;
     RECT  18.468 17.148 18.594 17.213 ;
     RECT  20.808 17.148 21.114 17.213 ;
     RECT  36.54 17.148 36.666 17.213 ;
     RECT  40.068 17.148 40.194 17.213 ;
     RECT  43.164 17.148 43.29 17.213 ;
     RECT  54.54 17.148 54.666 17.213 ;
     RECT  56.16 17.148 56.286 17.213 ;
     RECT  58.14 17.148 58.266 17.213 ;
    LAYER M4 ;
     RECT  2.293 11.952 2.329 11.976 ;
     RECT  2.257 13.68 2.329 13.704 ;
     RECT  2.329 11.52 2.408 11.976 ;
     RECT  2.329 13.056 2.408 13.704 ;
     RECT  2.293 0.192 2.485 0.216 ;
     RECT  2.408 2.148 2.485 15.132 ;
     RECT  2.485 0.192 2.677 0.264 ;
     RECT  2.485 2.148 2.704 15.288 ;
     RECT  2.677 0.192 2.761 0.312 ;
     RECT  2.704 10.56 2.819 15.288 ;
     RECT  2.819 10.56 2.915 14.856 ;
     RECT  2.761 0.144 3.089 0.312 ;
     RECT  3.089 0.144 3.161 0.168 ;
     RECT  3.212 15.936 3.299 15.96 ;
     RECT  2.915 10.56 3.877 14.232 ;
     RECT  2.861 1.728 3.881 1.752 ;
     RECT  3.877 10.56 3.989 15.048 ;
     RECT  2.704 6.864 4.453 6.936 ;
     RECT  2.704 7.968 4.453 9.144 ;
     RECT  3.989 10.56 4.988 14.376 ;
     RECT  5.021 1.728 5.108 1.752 ;
     RECT  4.069 3.408 5.108 3.432 ;
     RECT  4.669 4.512 5.108 4.536 ;
     RECT  4.453 6.864 5.108 9.144 ;
     RECT  4.988 10.56 5.108 15.288 ;
     RECT  5.108 1.728 5.404 15.288 ;
     RECT  5.221 0.192 5.413 0.216 ;
     RECT  5.404 9.504 5.413 15.288 ;
     RECT  5.413 9.504 5.603 15.384 ;
     RECT  5.413 0.192 5.605 0.264 ;
     RECT  5.605 0.192 5.753 0.312 ;
     RECT  5.404 7.44 5.897 7.464 ;
     RECT  5.603 9.504 6.275 15.096 ;
     RECT  5.753 0.192 6.581 0.264 ;
     RECT  5.404 5.136 6.709 5.16 ;
     RECT  6.613 8.16 7.052 8.184 ;
     RECT  6.275 9.504 7.052 14.856 ;
     RECT  6.709 5.136 7.381 5.208 ;
     RECT  7.381 5.136 7.573 5.256 ;
     RECT  6.764 15.936 7.619 15.96 ;
     RECT  7.573 5.136 7.669 5.304 ;
     RECT  7.052 8.16 7.669 14.856 ;
     RECT  5.404 1.728 7.808 3.432 ;
     RECT  7.669 5.136 7.808 5.496 ;
     RECT  7.669 8.16 7.808 15.288 ;
     RECT  6.581 0.192 7.811 0.216 ;
     RECT  7.808 1.728 7.811 15.288 ;
     RECT  7.811 1.728 8.104 15.24 ;
     RECT  8.104 7.44 8.291 15.24 ;
     RECT  8.291 7.44 8.525 15.096 ;
     RECT  7.957 0.288 8.701 0.312 ;
     RECT  8.104 1.728 8.701 1.8 ;
     RECT  8.701 0.288 8.819 1.8 ;
     RECT  8.525 7.44 9.107 14.856 ;
     RECT  8.819 1.728 9.205 1.8 ;
     RECT  8.104 2.832 9.205 3.048 ;
     RECT  9.205 1.728 9.289 3.048 ;
     RECT  9.157 0.192 9.299 0.216 ;
     RECT  9.289 2.832 9.644 3.048 ;
     RECT  8.104 5.088 9.745 5.496 ;
     RECT  9.745 5.088 9.781 5.688 ;
     RECT  9.107 7.44 9.925 7.464 ;
     RECT  9.107 8.544 10.117 14.856 ;
     RECT  10.117 8.544 10.213 15 ;
     RECT  10.213 8.544 10.309 15.24 ;
     RECT  9.289 1.728 10.393 1.8 ;
     RECT  9.644 2.832 10.393 3.432 ;
     RECT  10.393 1.728 10.508 3.432 ;
     RECT  9.781 4.416 10.508 5.688 ;
     RECT  9.925 7.344 10.508 7.464 ;
     RECT  10.309 8.544 10.508 15.288 ;
     RECT  10.508 1.728 10.595 15.288 ;
     RECT  10.357 0.288 10.739 0.312 ;
     RECT  10.595 1.728 10.787 15.24 ;
     RECT  10.787 1.728 10.804 14.862 ;
     RECT  10.804 4.416 11.219 6.264 ;
     RECT  11.219 5.088 11.603 6.264 ;
     RECT  10.804 7.344 11.893 7.464 ;
     RECT  10.804 9.12 11.989 14.856 ;
     RECT  11.893 7.344 12.053 7.656 ;
     RECT  11.905 3.408 12.131 3.432 ;
     RECT  10.804 1.728 12.14 1.944 ;
     RECT  12.053 7.632 12.157 7.656 ;
     RECT  11.989 9.12 12.157 14.952 ;
     RECT  11.603 5.088 12.332 5.592 ;
     RECT  12.157 7.632 13.045 14.952 ;
     RECT  13.045 7.44 13.129 14.952 ;
     RECT  12.14 1.728 13.208 2.856 ;
     RECT  12.332 4.848 13.208 5.592 ;
     RECT  13.129 7.44 13.208 15.288 ;
     RECT  13.208 1.728 13.331 15.288 ;
     RECT  13.285 0.192 13.385 0.216 ;
     RECT  13.331 1.728 13.504 15.24 ;
     RECT  13.504 1.728 13.619 2.856 ;
     RECT  13.504 8.544 13.667 15.24 ;
     RECT  13.619 1.728 13.853 1.848 ;
     RECT  13.504 4.272 14.051 5.592 ;
     RECT  13.667 8.544 14.435 14.904 ;
     RECT  14.417 0.576 14.501 0.6 ;
     RECT  13.504 6.816 14.629 7.464 ;
     RECT  14.636 15.936 14.723 15.96 ;
     RECT  14.051 4.848 14.867 5.592 ;
     RECT  14.435 9.504 14.869 14.904 ;
     RECT  14.867 5.136 14.965 5.592 ;
     RECT  14.869 9.504 15.217 14.952 ;
     RECT  13.619 2.832 15.649 2.856 ;
     RECT  13.853 1.728 15.721 1.8 ;
     RECT  15.649 2.784 15.721 2.856 ;
     RECT  15.793 0.192 15.877 0.216 ;
     RECT  15.721 1.728 15.908 2.856 ;
     RECT  15.781 3.936 15.908 3.96 ;
     RECT  14.965 5.136 15.908 5.64 ;
     RECT  14.629 6.816 15.908 7.512 ;
     RECT  15.217 9.504 15.908 15.288 ;
     RECT  15.908 1.728 16.204 15.288 ;
     RECT  16.204 9.168 16.213 15.288 ;
     RECT  16.204 7.44 16.301 7.464 ;
     RECT  16.204 1.728 16.417 5.736 ;
     RECT  16.213 9.168 16.451 15.384 ;
     RECT  16.451 9.456 16.481 15.288 ;
     RECT  16.021 0.288 16.499 0.312 ;
     RECT  16.481 9.504 16.499 15.288 ;
     RECT  16.417 5.136 16.589 5.736 ;
     RECT  16.499 9.504 16.625 15 ;
     RECT  16.405 16.56 16.835 16.584 ;
     RECT  16.417 1.728 16.979 3.768 ;
     RECT  16.979 1.728 17.027 3.24 ;
     RECT  17.027 3.216 17.26 3.24 ;
     RECT  17.027 1.728 17.365 1.848 ;
     RECT  17.365 1.152 17.453 1.848 ;
     RECT  16.589 5.136 17.507 5.64 ;
     RECT  17.507 5.136 17.737 5.208 ;
     RECT  16.625 9.504 17.749 14.424 ;
     RECT  17.749 9.504 17.773 14.856 ;
     RECT  17.773 9.504 17.797 14.952 ;
     RECT  17.453 1.728 17.989 1.848 ;
     RECT  17.797 9.36 18.277 14.952 ;
     RECT  17.737 4.272 18.469 5.208 ;
     RECT  17.989 1.728 18.565 1.944 ;
     RECT  18.565 1.728 18.608 2.04 ;
     RECT  18.469 3.408 18.608 5.208 ;
     RECT  18.373 7.44 18.608 7.464 ;
     RECT  18.277 9.36 18.608 15.912 ;
     RECT  18.421 0.288 18.611 0.312 ;
     RECT  18.608 1.728 18.904 15.912 ;
     RECT  18.904 7.44 18.965 7.464 ;
     RECT  18.904 1.728 19.235 5.208 ;
     RECT  18.904 9.072 19.276 15.912 ;
     RECT  19.235 1.728 19.379 2.424 ;
     RECT  19.276 15.888 19.573 15.912 ;
     RECT  19.573 15.888 19.619 16.008 ;
     RECT  18.904 6.288 19.721 6.312 ;
     RECT  19.235 3.936 19.756 5.208 ;
     RECT  19.619 15.984 19.763 16.008 ;
     RECT  19.681 0.192 19.765 0.216 ;
     RECT  19.756 4.512 19.765 5.208 ;
     RECT  19.765 5.088 20.089 5.208 ;
     RECT  19.379 1.728 20.341 2.28 ;
     RECT  19.276 9.072 20.365 14.856 ;
     RECT  20.365 8.592 20.437 14.856 ;
     RECT  20.437 8.544 21.109 14.856 ;
     RECT  21.109 8.544 21.193 15.24 ;
     RECT  20.341 1.728 21.308 2.328 ;
     RECT  20.089 5.136 21.308 5.208 ;
     RECT  20.581 6.24 21.308 6.264 ;
     RECT  20.473 7.44 21.308 7.464 ;
     RECT  21.193 8.544 21.308 15.288 ;
     RECT  21.157 0.288 21.347 0.312 ;
     RECT  21.308 1.728 21.395 15.288 ;
     RECT  21.395 1.728 21.587 15.24 ;
     RECT  21.587 1.728 21.604 15.096 ;
     RECT  21.604 3.312 21.773 3.432 ;
     RECT  21.604 7.44 21.773 7.464 ;
     RECT  21.604 8.496 22.061 15.096 ;
     RECT  22.061 8.496 22.105 9.144 ;
     RECT  22.061 10.224 22.241 15.096 ;
     RECT  21.604 5.136 22.595 6.312 ;
     RECT  21.604 1.728 23.029 2.328 ;
     RECT  21.773 3.408 23.029 3.432 ;
     RECT  22.105 8.496 23.029 8.52 ;
     RECT  22.595 6.288 23.033 6.312 ;
     RECT  23.029 1.728 23.065 3.432 ;
     RECT  23.029 8.448 23.228 8.52 ;
     RECT  22.241 10.224 23.317 14.76 ;
     RECT  23.228 8.448 23.509 9.144 ;
     RECT  23.317 10.176 23.509 14.76 ;
     RECT  23.077 6.864 23.845 6.936 ;
     RECT  23.065 1.728 24.008 3.96 ;
     RECT  22.595 5.136 24.008 5.256 ;
     RECT  23.845 6.864 24.008 7.464 ;
     RECT  23.509 8.448 24.008 14.76 ;
     RECT  24.008 1.728 24.085 15.132 ;
     RECT  24.085 1.728 24.304 15.288 ;
     RECT  24.304 8.448 24.418 15.288 ;
     RECT  24.418 8.448 24.515 15.336 ;
     RECT  24.304 1.728 24.563 3.768 ;
     RECT  24.613 0.192 24.697 0.216 ;
     RECT  24.304 6.816 24.841 7.464 ;
     RECT  24.805 16.56 25.013 16.584 ;
     RECT  24.841 6.912 25.121 7.464 ;
     RECT  24.515 8.448 25.331 14.856 ;
     RECT  24.304 5.184 25.427 5.736 ;
     RECT  24.563 1.728 25.573 3.432 ;
     RECT  25.427 5.184 25.621 5.4 ;
     RECT  25.573 1.728 25.66 3.96 ;
     RECT  25.121 7.44 25.661 7.464 ;
     RECT  25.621 5.088 25.705 5.4 ;
     RECT  25.66 1.728 25.715 3.432 ;
     RECT  25.715 1.728 26.708 2.856 ;
     RECT  25.705 5.184 26.708 5.4 ;
     RECT  25.909 7.968 26.708 7.992 ;
     RECT  25.331 9.12 26.708 14.856 ;
     RECT  26.389 0.576 26.773 0.6 ;
     RECT  26.708 1.728 26.821 15.132 ;
     RECT  26.821 1.728 26.845 15.288 ;
     RECT  26.629 16.56 26.845 16.584 ;
     RECT  26.845 1.728 27.004 16.584 ;
     RECT  26.773 0.192 27.155 0.6 ;
     RECT  27.004 9.072 27.203 16.584 ;
     RECT  27.203 9.072 27.345 14.76 ;
     RECT  27.203 15.984 27.395 16.584 ;
     RECT  27.345 9.072 27.433 14.472 ;
     RECT  27.395 15.984 27.443 16.008 ;
     RECT  27.433 9.168 27.491 14.472 ;
     RECT  27.004 1.728 27.923 5.928 ;
     RECT  27.155 0.576 27.973 0.6 ;
     RECT  27.923 1.728 27.973 3.96 ;
     RECT  28.165 7.968 28.357 7.992 ;
     RECT  27.973 0.576 28.397 3.96 ;
     RECT  28.357 7.44 28.433 7.992 ;
     RECT  28.397 0.576 28.549 0.6 ;
     RECT  27.491 9.36 28.597 14.472 ;
     RECT  28.597 9.36 28.684 15.432 ;
     RECT  28.549 0.192 28.793 0.6 ;
     RECT  28.684 9.36 29.125 15.288 ;
     RECT  27.923 5.088 29.401 5.928 ;
     RECT  28.397 1.728 29.408 3.96 ;
     RECT  29.401 5.04 29.408 5.928 ;
     RECT  28.433 7.44 29.408 7.464 ;
     RECT  29.125 8.832 29.408 15.288 ;
     RECT  28.793 0.192 29.411 0.312 ;
     RECT  29.408 1.728 29.411 15.288 ;
     RECT  29.411 1.728 29.512 15.132 ;
     RECT  29.411 0.288 29.603 0.312 ;
     RECT  29.512 1.728 29.704 14.862 ;
     RECT  29.557 16.56 29.891 16.584 ;
     RECT  29.704 7.44 30.179 7.464 ;
     RECT  29.704 1.728 30.323 3.432 ;
     RECT  29.704 5.04 30.665 5.496 ;
     RECT  29.704 9.36 30.877 14.856 ;
     RECT  30.877 8.592 31.021 14.856 ;
     RECT  30.665 5.04 31.237 5.208 ;
     RECT  30.323 1.728 31.705 2.856 ;
     RECT  31.021 8.544 31.717 14.856 ;
     RECT  31.717 8.544 32.065 15 ;
     RECT  31.705 1.728 32.108 2.904 ;
     RECT  31.237 4.512 32.108 5.208 ;
     RECT  31.093 6.288 32.108 6.312 ;
     RECT  32.065 8.544 32.108 15.288 ;
     RECT  32.108 1.728 32.195 15.288 ;
     RECT  32.195 1.728 32.404 15.24 ;
     RECT  32.404 4.416 32.531 5.208 ;
     RECT  32.404 8.544 32.627 15.24 ;
     RECT  32.627 8.544 32.723 14.856 ;
     RECT  32.723 8.544 32.867 8.568 ;
     RECT  32.531 5.088 33.113 5.208 ;
     RECT  32.404 7.44 33.221 7.464 ;
     RECT  32.404 1.728 33.5 2.856 ;
     RECT  33.5 1.728 33.587 3.768 ;
     RECT  32.723 9.552 33.617 14.856 ;
     RECT  33.617 9.552 33.973 14.712 ;
     RECT  33.113 5.088 34.153 5.16 ;
     RECT  33.829 0.288 34.253 0.312 ;
     RECT  34.261 3.84 34.433 3.96 ;
     RECT  34.153 5.04 34.433 5.16 ;
     RECT  33.973 9.36 34.453 14.712 ;
     RECT  33.587 1.728 34.808 2.856 ;
     RECT  34.433 3.84 34.808 5.16 ;
     RECT  34.309 7.44 34.808 7.464 ;
     RECT  34.453 8.832 34.808 14.712 ;
     RECT  34.253 0.192 34.837 0.312 ;
     RECT  34.808 1.728 34.885 15.132 ;
     RECT  34.885 1.728 35.104 15.288 ;
     RECT  34.837 0.192 35.267 0.408 ;
     RECT  35.104 8.544 35.267 15.288 ;
     RECT  35.267 8.544 35.315 15.096 ;
     RECT  35.267 0.192 35.363 0.264 ;
     RECT  35.077 16.56 35.557 16.584 ;
     RECT  35.315 8.976 35.603 15.096 ;
     RECT  35.557 16.56 35.641 16.632 ;
     RECT  35.363 0.192 35.747 0.216 ;
     RECT  35.641 16.56 35.843 16.584 ;
     RECT  35.603 9.072 36.083 15.096 ;
     RECT  35.104 1.728 36.133 3.768 ;
     RECT  35.104 5.136 36.133 5.256 ;
     RECT  36.133 1.728 36.277 5.256 ;
     RECT  36.277 1.728 36.389 5.544 ;
     RECT  36.083 9.072 36.673 14.856 ;
     RECT  35.104 6.864 36.997 6.888 ;
     RECT  36.673 7.968 36.997 14.856 ;
     RECT  37.189 0.192 37.289 0.216 ;
     RECT  36.997 6.864 37.349 14.856 ;
     RECT  37.349 6.864 37.388 15.192 ;
     RECT  36.389 1.728 37.508 3.96 ;
     RECT  36.389 5.088 37.508 5.544 ;
     RECT  37.388 6.864 37.508 15.288 ;
     RECT  37.508 1.728 37.804 15.288 ;
     RECT  37.804 6.864 38.005 15.288 ;
     RECT  38.005 6.864 38.195 15.384 ;
     RECT  37.804 5.184 38.225 5.544 ;
     RECT  38.195 6.864 38.477 14.856 ;
     RECT  38.225 5.232 38.621 5.544 ;
     RECT  38.477 6.864 38.693 13.944 ;
     RECT  37.804 3.36 38.729 4.008 ;
     RECT  38.753 0.192 38.837 0.216 ;
     RECT  37.804 1.728 39.157 1.992 ;
     RECT  38.729 3.36 39.157 3.432 ;
     RECT  38.621 5.52 39.452 5.544 ;
     RECT  38.693 7.92 39.473 13.944 ;
     RECT  38.693 6.864 39.733 6.888 ;
     RECT  39.473 7.92 39.733 14.28 ;
     RECT  39.452 5.52 39.925 5.64 ;
     RECT  39.157 1.728 40.208 3.432 ;
     RECT  39.925 5.184 40.208 5.64 ;
     RECT  39.733 6.864 40.208 14.28 ;
     RECT  40.069 15.264 40.208 15.288 ;
     RECT  40.208 1.728 40.211 15.288 ;
     RECT  40.211 1.728 40.403 15.24 ;
     RECT  40.403 1.728 40.504 14.862 ;
     RECT  40.504 7.44 40.691 14.856 ;
     RECT  40.504 4.512 40.825 6.264 ;
     RECT  40.504 1.728 41.141 3.432 ;
     RECT  40.691 8.496 41.141 14.856 ;
     RECT  40.825 5.136 41.507 6.264 ;
     RECT  41.141 1.728 41.789 2.904 ;
     RECT  41.821 3.936 41.905 3.96 ;
     RECT  40.691 7.44 41.996 7.464 ;
     RECT  41.141 8.496 41.996 14.52 ;
     RECT  41.507 5.136 42.037 5.544 ;
     RECT  42.037 4.992 42.577 5.544 ;
     RECT  42.757 0.192 42.899 0.216 ;
     RECT  41.789 1.728 42.908 2.28 ;
     RECT  42.577 3.408 42.908 3.432 ;
     RECT  42.577 4.992 42.908 5.688 ;
     RECT  41.996 7.44 42.908 14.52 ;
     RECT  42.908 1.728 42.949 15.132 ;
     RECT  42.949 1.728 43.204 15.288 ;
     RECT  43.204 1.728 43.331 2.808 ;
     RECT  43.204 7.44 43.331 15.288 ;
     RECT  43.331 7.44 43.337 15.24 ;
     RECT  43.331 1.728 43.373 2.28 ;
     RECT  43.337 7.44 43.445 14.856 ;
     RECT  43.204 4.512 43.715 6.264 ;
     RECT  43.715 4.512 43.907 5.736 ;
     RECT  42.649 16.56 44.243 16.584 ;
     RECT  43.373 1.728 44.437 1.896 ;
     RECT  43.445 8.544 44.444 14.856 ;
     RECT  43.445 7.44 44.483 7.464 ;
     RECT  43.907 4.992 44.522 5.736 ;
     RECT  44.444 8.544 44.531 15.432 ;
     RECT  44.531 8.544 44.579 14.76 ;
     RECT  44.522 4.992 44.627 5.688 ;
     RECT  44.821 3.744 45.157 3.768 ;
     RECT  45.157 3.312 45.205 3.768 ;
     RECT  44.627 4.992 45.205 5.544 ;
     RECT  44.437 1.728 45.608 2.184 ;
     RECT  45.205 3.312 45.608 5.544 ;
     RECT  44.579 8.544 45.608 8.568 ;
     RECT  44.579 9.648 45.608 14.76 ;
     RECT  45.608 1.728 45.685 15.132 ;
     RECT  45.685 1.728 45.904 15.288 ;
     RECT  45.829 0.288 46.019 0.312 ;
     RECT  45.904 8.544 46.163 15.288 ;
     RECT  46.163 8.544 46.252 14.856 ;
     RECT  45.904 1.728 46.549 5.688 ;
     RECT  46.549 1.728 46.643 5.544 ;
     RECT  46.643 3.408 46.883 5.544 ;
     RECT  46.789 0.192 46.931 0.216 ;
     RECT  46.252 8.544 46.931 8.616 ;
     RECT  46.883 3.408 46.979 3.96 ;
     RECT  46.252 9.936 47.185 14.856 ;
     RECT  47.185 9.936 47.317 14.904 ;
     RECT  46.885 7.44 47.333 7.464 ;
     RECT  46.643 1.728 47.761 2.184 ;
     RECT  47.317 9.888 47.845 14.904 ;
     RECT  46.931 8.592 47.852 8.616 ;
     RECT  47.845 9.696 47.852 14.904 ;
     RECT  47.761 1.728 47.989 2.28 ;
     RECT  47.989 1.728 47.996 2.856 ;
     RECT  46.979 3.936 47.996 3.96 ;
     RECT  47.852 8.592 48.133 14.904 ;
     RECT  48.133 8.592 48.275 15.288 ;
     RECT  47.996 1.728 48.308 3.96 ;
     RECT  46.883 4.992 48.308 5.544 ;
     RECT  48.275 8.592 48.308 15.24 ;
     RECT  47.989 0.192 48.565 0.216 ;
     RECT  48.308 1.728 48.604 15.24 ;
     RECT  48.565 0.192 48.755 0.312 ;
     RECT  47.941 16.56 48.755 16.584 ;
     RECT  48.604 15.216 48.803 15.24 ;
     RECT  48.755 0.192 48.995 0.216 ;
     RECT  48.604 1.728 49.036 2.952 ;
     RECT  48.956 17.04 49.069 17.064 ;
     RECT  48.604 8.544 49.331 14.232 ;
     RECT  49.331 9.12 49.573 14.232 ;
     RECT  49.573 9.12 49.66 14.904 ;
     RECT  49.036 2.832 49.717 2.952 ;
     RECT  49.66 9.12 49.825 14.424 ;
     RECT  49.849 7.44 49.955 7.464 ;
     RECT  48.604 4.992 50.137 5.544 ;
     RECT  49.036 1.728 50.149 1.8 ;
     RECT  49.717 2.832 50.149 3.048 ;
     RECT  50.149 1.152 50.533 3.048 ;
     RECT  50.533 0.816 50.705 3.048 ;
     RECT  49.825 9.696 50.725 14.424 ;
     RECT  50.705 0.192 50.789 3.048 ;
     RECT  50.137 4.992 50.869 5.832 ;
     RECT  50.789 0.288 50.929 3.048 ;
     RECT  50.725 9.696 50.965 15.24 ;
     RECT  50.929 0.288 51.008 3.864 ;
     RECT  50.869 4.992 51.008 6.216 ;
     RECT  50.636 8.544 51.008 8.568 ;
     RECT  50.965 9.696 51.008 15.288 ;
     RECT  51.008 0.288 51.155 15.288 ;
     RECT  51.155 0.816 51.293 15.288 ;
     RECT  51.293 0.816 51.304 14.862 ;
     RECT  51.304 9.072 51.443 9.096 ;
     RECT  51.304 10.176 51.689 14.856 ;
     RECT  51.685 16.56 51.769 16.584 ;
     RECT  51.689 10.176 51.833 14.424 ;
     RECT  51.304 0.816 51.875 3.96 ;
     RECT  51.875 0.816 52.253 1.752 ;
     RECT  52.253 0.192 52.337 1.752 ;
     RECT  51.304 4.992 52.595 5.832 ;
     RECT  51.875 2.832 52.643 3.96 ;
     RECT  52.741 15.936 52.841 15.96 ;
     RECT  52.643 3.216 52.94 3.96 ;
     RECT  52.595 4.992 52.94 5.736 ;
     RECT  51.833 10.176 53.017 14.28 ;
     RECT  53.017 6.96 53.053 6.984 ;
     RECT  52.337 0.528 53.077 1.752 ;
     RECT  53.017 10.176 53.077 14.52 ;
     RECT  53.077 10.176 53.161 14.856 ;
     RECT  53.161 9.696 53.317 14.856 ;
     RECT  53.077 0.528 53.441 1.8 ;
     RECT  53.441 0.192 53.525 1.8 ;
     RECT  53.317 9.696 53.557 14.904 ;
     RECT  53.525 0.816 53.665 1.8 ;
     RECT  53.665 0.816 53.708 2.04 ;
     RECT  52.94 3.216 53.708 5.736 ;
     RECT  53.053 6.864 53.708 6.984 ;
     RECT  53.557 9.264 53.708 14.904 ;
     RECT  53.708 0.816 54.004 15.288 ;
     RECT  54.004 7.392 54.131 15.288 ;
     RECT  54.131 15.264 54.137 15.288 ;
     RECT  54.004 0.816 54.317 2.952 ;
     RECT  54.317 0.816 54.497 2.856 ;
     RECT  54.131 7.392 54.533 14.28 ;
     RECT  53.557 16.56 54.611 16.584 ;
     RECT  54.004 4.896 54.785 5.544 ;
     RECT  54.533 8.496 54.829 14.28 ;
     RECT  54.829 8.496 55.037 13.992 ;
     RECT  54.533 7.392 55.139 7.416 ;
     RECT  54.497 1.728 55.621 2.856 ;
     RECT  55.621 1.152 55.829 2.856 ;
     RECT  55.037 8.928 56.041 13.992 ;
     RECT  55.285 15.072 56.041 15.096 ;
     RECT  56.156 0.528 56.293 0.6 ;
     RECT  55.829 1.728 56.408 2.856 ;
     RECT  55.321 3.936 56.408 3.96 ;
     RECT  54.785 4.992 56.408 5.544 ;
     RECT  56.041 8.928 56.408 15.096 ;
     RECT  56.293 0.192 56.435 0.6 ;
     RECT  56.408 1.728 56.485 15.132 ;
     RECT  56.485 1.728 56.704 15.288 ;
     RECT  56.704 4.848 56.915 5.736 ;
     RECT  56.435 0.576 56.981 0.6 ;
     RECT  56.704 7.968 57.011 15.288 ;
     RECT  57.011 7.968 57.017 14.856 ;
     RECT  57.017 7.968 57.347 7.992 ;
     RECT  56.704 1.728 57.673 2.856 ;
     RECT  57.017 9.024 57.779 14.856 ;
     RECT  56.915 4.848 57.805 5.544 ;
     RECT  57.805 3.408 57.889 3.432 ;
     RECT  57.805 4.464 58.069 5.544 ;
     RECT  57.779 10.224 58.069 14.856 ;
     RECT  58.549 0.192 58.691 0.216 ;
     RECT  58.069 10.224 58.741 15.096 ;
     RECT  57.779 9.024 58.837 9.144 ;
     RECT  58.741 10.176 58.837 15.096 ;
     RECT  58.837 9.024 58.885 15.096 ;
     RECT  57.673 1.728 58.981 2.28 ;
     RECT  58.069 3.648 59.029 5.544 ;
     RECT  58.981 1.728 59.108 2.328 ;
     RECT  59.029 3.312 59.108 5.544 ;
     RECT  58.885 9.024 59.108 15.288 ;
     RECT  59.108 1.728 59.221 15.288 ;
     RECT  59.221 1.728 59.404 16.008 ;
     RECT  58.981 0.288 59.651 0.312 ;
     RECT  59.404 8.976 59.699 16.008 ;
     RECT  59.404 1.728 59.897 5.736 ;
     RECT  59.699 8.976 59.969 14.424 ;
     RECT  59.699 15.984 60.419 16.008 ;
     RECT  59.897 1.728 60.611 5.544 ;
     RECT  59.969 9.024 60.865 14.424 ;
     RECT  60.611 3.936 61.153 5.544 ;
     RECT  60.865 9.024 61.253 14.808 ;
     RECT  59.404 7.44 61.369 7.464 ;
     RECT  61.253 8.496 61.369 14.808 ;
     RECT  61.369 7.44 61.477 14.808 ;
     RECT  61.381 0.192 61.523 0.216 ;
     RECT  60.611 1.728 61.621 2.424 ;
     RECT  61.153 3.936 61.621 6.264 ;
     RECT  61.477 7.44 61.621 14.856 ;
     RECT  61.237 15.936 61.621 15.96 ;
     RECT  61.621 1.728 61.808 6.264 ;
     RECT  61.621 7.44 61.808 15.96 ;
     RECT  61.901 0.576 61.985 0.6 ;
     RECT  61.808 1.728 62.104 15.96 ;
     RECT  62.104 1.728 62.435 6.216 ;
     RECT  62.104 7.44 62.489 15.96 ;
     RECT  62.489 8.304 62.705 15.96 ;
     RECT  62.435 3.888 62.741 6.216 ;
     RECT  62.705 15.936 62.771 15.96 ;
     RECT  62.677 0.192 62.849 0.216 ;
     RECT  63.061 16.56 63.145 16.584 ;
     RECT  62.741 4.992 63.347 6.216 ;
     RECT  62.435 1.728 63.829 2.856 ;
     RECT  62.741 3.888 63.884 3.96 ;
     RECT  63.347 4.992 63.884 5.496 ;
     RECT  62.705 8.304 63.925 14.76 ;
     RECT  63.925 8.304 64.309 14.856 ;
     RECT  63.884 3.888 64.393 5.496 ;
     RECT  64.309 8.304 64.465 14.952 ;
     RECT  63.829 1.728 64.508 2.904 ;
     RECT  64.393 3.888 64.508 6.12 ;
     RECT  64.465 7.392 64.508 14.952 ;
     RECT  64.316 15.936 64.508 15.96 ;
     RECT  64.508 1.728 64.804 15.96 ;
     RECT  64.645 0.192 64.979 0.216 ;
     RECT  64.804 4.512 65.053 15.96 ;
     RECT  65.053 15.936 65.221 15.96 ;
     RECT  65.221 15.936 65.305 16.584 ;
     RECT  65.305 15.936 65.315 15.96 ;
     RECT  65.053 4.512 65.449 14.952 ;
     RECT  65.449 4.992 65.603 14.952 ;
     RECT  65.603 4.992 65.729 14.904 ;
     RECT  65.729 4.992 66.131 6.264 ;
     RECT  66.581 0.192 66.665 0.216 ;
     RECT  65.729 7.632 66.853 14.904 ;
     RECT  66.853 7.392 66.949 14.904 ;
     RECT  66.805 0.576 66.989 0.6 ;
     RECT  66.853 16.56 67.024 16.584 ;
     RECT  66.949 6.816 67.093 15.48 ;
     RECT  64.804 1.728 67.208 3.432 ;
     RECT  66.131 4.992 67.208 5.736 ;
     RECT  67.093 6.768 67.208 15.48 ;
     RECT  67.208 1.728 67.381 15.48 ;
     RECT  67.381 1.152 67.504 15.48 ;
     RECT  67.504 1.152 67.709 3 ;
     RECT  67.504 11.952 67.715 15.48 ;
     RECT  67.709 2.736 67.781 3 ;
     RECT  67.715 11.952 67.925 15.432 ;
     RECT  67.925 15.408 67.955 15.432 ;
     RECT  67.925 11.952 67.997 14.424 ;
     RECT  67.709 1.152 68.029 1.752 ;
     RECT  67.504 6.768 68.105 10.92 ;
     RECT  67.997 12.864 68.105 14.28 ;
     RECT  68.029 1.104 68.209 1.752 ;
     RECT  68.105 10.08 68.285 10.92 ;
     RECT  68.209 0.192 68.321 1.752 ;
     RECT  68.321 1.728 68.387 1.752 ;
     RECT  68.285 10.08 68.501 10.44 ;
     RECT  68.501 10.08 68.573 10.104 ;
     RECT  68.105 12.864 68.573 13.224 ;
     RECT  67.024 16.56 68.653 16.632 ;
     RECT  68.573 13.2 68.681 13.224 ;
     RECT  68.105 6.768 68.717 9.048 ;
     RECT  68.717 6.768 68.723 7.704 ;
     RECT  68.717 8.736 68.753 9.048 ;
     RECT  68.105 14.256 68.761 14.28 ;
     RECT  67.781 2.736 68.857 2.904 ;
     RECT  68.857 2.256 68.861 2.904 ;
     RECT  68.753 8.736 68.897 8.76 ;
     RECT  68.723 6.768 68.915 6.792 ;
     RECT  67.504 4.992 69.001 5.448 ;
     RECT  68.861 2.256 69.011 2.28 ;
     RECT  68.321 0.192 69.02 0.6 ;
     RECT  69.02 0.144 69.041 0.6 ;
     RECT  68.965 14.832 69.049 14.856 ;
     RECT  69.041 0.144 69.107 0.168 ;
     RECT  69.001 4.56 69.107 5.448 ;
     RECT  68.653 16.56 69.148 16.584 ;
     RECT  69.107 5.424 71.1 5.448 ;
     RECT  69.541 11.904 71.1 11.928 ;
    LAYER M5 ;
     RECT  69.072 0.133 69.096 0.144 ;
     RECT  2.304 0.144 69.096 0.227 ;
     RECT  2.496 0.227 69.096 0.275 ;
     RECT  2.688 0.275 69.096 0.323 ;
     RECT  2.88 0.323 69.096 1.763 ;
     RECT  2.88 1.763 33.48 1.811 ;
     RECT  9.216 1.811 17.016 1.955 ;
     RECT  18 1.811 33.48 1.955 ;
     RECT  18.384 1.955 33.48 2.099 ;
     RECT  2.88 1.811 8.232 2.137 ;
     RECT  26.7 2.099 33.48 2.195 ;
     RECT  34.464 1.763 67.656 2.195 ;
     RECT  18.384 2.099 25.656 2.291 ;
     RECT  58.656 2.195 67.656 2.291 ;
     RECT  67.2 2.291 67.656 2.773 ;
     RECT  68.784 1.763 69.096 2.773 ;
     RECT  2.4 2.137 8.232 2.821 ;
     RECT  9.216 1.955 10.812 2.821 ;
     RECT  28.368 2.195 33.48 2.821 ;
     RECT  34.464 2.195 44.088 2.821 ;
     RECT  58.8 2.291 66.216 2.915 ;
     RECT  67.2 2.773 69.096 2.915 ;
     RECT  11.904 1.955 17.016 3.205 ;
     RECT  26.7 2.195 27.144 3.205 ;
     RECT  28.368 2.821 44.088 3.205 ;
     RECT  45.216 2.195 57.624 3.301 ;
     RECT  18.384 2.291 25.272 3.397 ;
     RECT  45.168 3.301 57.624 3.397 ;
     RECT  58.8 2.915 63.528 3.397 ;
     RECT  64.5 2.915 66.216 3.443 ;
     RECT  26.7 3.205 44.088 3.733 ;
     RECT  45.168 3.397 63.528 3.733 ;
     RECT  26.7 3.733 63.528 3.877 ;
     RECT  64.5 3.443 65.928 3.877 ;
     RECT  11.904 3.205 17.208 4.261 ;
     RECT  18.384 3.397 25.704 4.261 ;
     RECT  2.4 2.821 10.812 4.405 ;
     RECT  11.904 4.261 25.704 4.405 ;
     RECT  68.976 2.915 69.096 4.595 ;
     RECT  2.4 4.405 25.704 5.365 ;
     RECT  26.7 3.877 65.928 5.365 ;
     RECT  2.4 5.365 65.928 5.653 ;
     RECT  67.2 2.915 67.848 5.653 ;
     RECT  68.976 4.595 69 6.757 ;
     RECT  2.4 5.653 67.848 6.805 ;
     RECT  68.88 6.757 69 6.805 ;
     RECT  2.4 6.805 69 6.947 ;
     RECT  2.4 6.947 3.288 7.957 ;
     RECT  4.272 6.947 69 7.957 ;
     RECT  2.4 7.957 69 9.155 ;
     RECT  2.4 9.155 2.712 11.269 ;
     RECT  4.032 9.155 69 11.269 ;
     RECT  2.4 11.269 69 11.941 ;
     RECT  2.304 11.941 69 14.867 ;
     RECT  2.304 14.867 68.904 16.549 ;
     RECT  2.304 16.549 69.096 17.104 ;
  END
END dsfd_dvrlyh_682_NS
END LIBRARY
